VERSION 5.7 ;
  NOWIREEXTENSIONATPIN ON ;
  DIVIDERCHAR "/" ;
  BUSBITCHARS "[]" ;
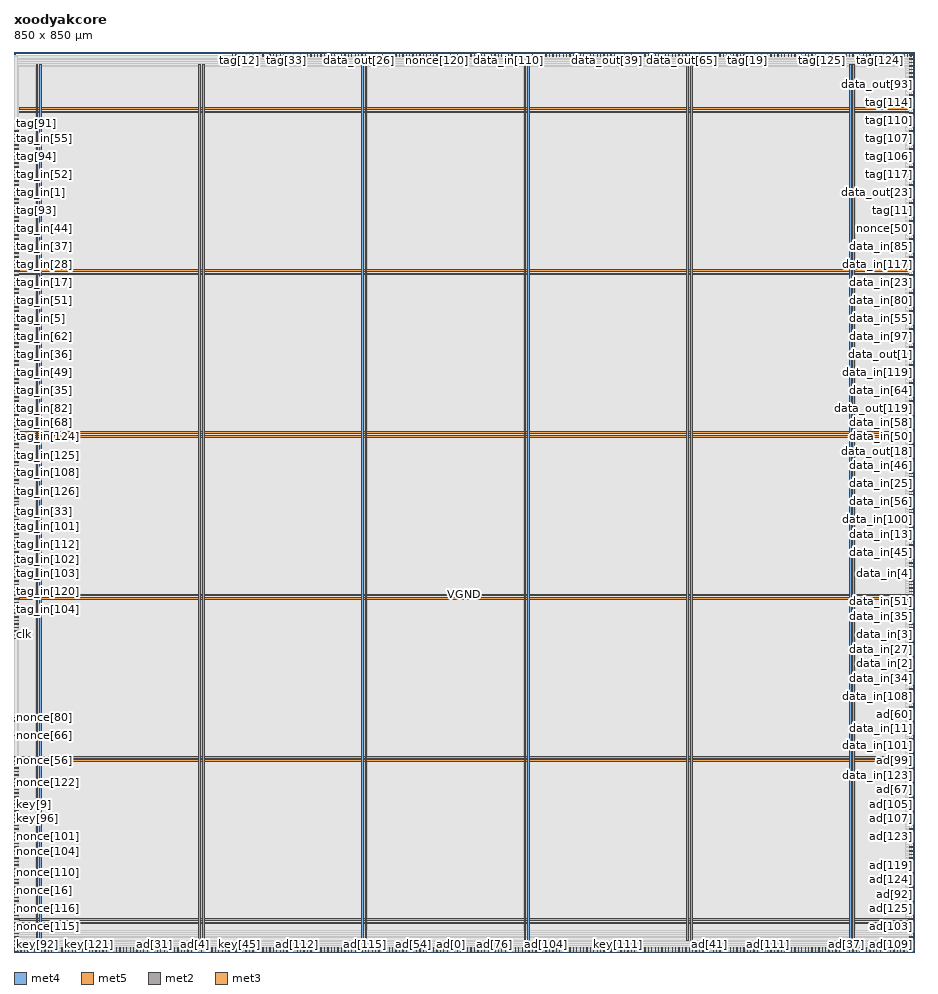
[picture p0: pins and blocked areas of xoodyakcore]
MACRO xoodyakcore
  CLASS BLOCK ;
  FOREIGN xoodyakcore ;
  ORIGIN 0.000 0.000 ;
  SIZE 850.000 BY 850.000 ;
  PIN VGND
    DIRECTION INOUT ;
    USE GROUND ;
    PORT
      LAYER met4 ;
        RECT 24.340 10.640 25.940 838.000 ;
    END
    PORT
      LAYER met4 ;
        RECT 177.940 10.640 179.540 838.000 ;
    END
    PORT
      LAYER met4 ;
        RECT 331.540 10.640 333.140 838.000 ;
    END
    PORT
      LAYER met4 ;
        RECT 485.140 10.640 486.740 838.000 ;
    END
    PORT
      LAYER met4 ;
        RECT 638.740 10.640 640.340 838.000 ;
    END
    PORT
      LAYER met4 ;
        RECT 792.340 10.640 793.940 838.000 ;
    END
    PORT
      LAYER met5 ;
        RECT 5.280 30.030 844.340 31.630 ;
    END
    PORT
      LAYER met5 ;
        RECT 5.280 183.210 844.340 184.810 ;
    END
    PORT
      LAYER met5 ;
        RECT 5.280 336.390 844.340 337.990 ;
    END
    PORT
      LAYER met5 ;
        RECT 5.280 489.570 844.340 491.170 ;
    END
    PORT
      LAYER met5 ;
        RECT 5.280 642.750 844.340 644.350 ;
    END
    PORT
      LAYER met5 ;
        RECT 5.280 795.930 844.340 797.530 ;
    END
  END VGND
  PIN VPWR
    DIRECTION INOUT ;
    USE POWER ;
    PORT
      LAYER met4 ;
        RECT 21.040 10.640 22.640 838.000 ;
    END
    PORT
      LAYER met4 ;
        RECT 174.640 10.640 176.240 838.000 ;
    END
    PORT
      LAYER met4 ;
        RECT 328.240 10.640 329.840 838.000 ;
    END
    PORT
      LAYER met4 ;
        RECT 481.840 10.640 483.440 838.000 ;
    END
    PORT
      LAYER met4 ;
        RECT 635.440 10.640 637.040 838.000 ;
    END
    PORT
      LAYER met4 ;
        RECT 789.040 10.640 790.640 838.000 ;
    END
    PORT
      LAYER met5 ;
        RECT 5.280 26.730 844.340 28.330 ;
    END
    PORT
      LAYER met5 ;
        RECT 5.280 179.910 844.340 181.510 ;
    END
    PORT
      LAYER met5 ;
        RECT 5.280 333.090 844.340 334.690 ;
    END
    PORT
      LAYER met5 ;
        RECT 5.280 486.270 844.340 487.870 ;
    END
    PORT
      LAYER met5 ;
        RECT 5.280 639.450 844.340 641.050 ;
    END
    PORT
      LAYER met5 ;
        RECT 5.280 792.630 844.340 794.230 ;
    END
  END VPWR
  PIN ad[0]
    DIRECTION INPUT ;
    USE SIGNAL ;
    ANTENNAGATEAREA 0.196500 ;
    PORT
      LAYER met2 ;
        RECT 412.250 0.000 412.530 4.000 ;
    END
  END ad[0]
  PIN ad[100]
    DIRECTION INPUT ;
    USE SIGNAL ;
    ANTENNAGATEAREA 0.196500 ;
    PORT
      LAYER met2 ;
        RECT 135.330 0.000 135.610 4.000 ;
    END
  END ad[100]
  PIN ad[101]
    DIRECTION INPUT ;
    USE SIGNAL ;
    ANTENNAGATEAREA 0.159000 ;
    PORT
      LAYER met2 ;
        RECT 808.310 0.000 808.590 4.000 ;
    END
  END ad[101]
  PIN ad[102]
    DIRECTION INPUT ;
    USE SIGNAL ;
    ANTENNAGATEAREA 0.213000 ;
    PORT
      LAYER met3 ;
        RECT 846.000 78.240 850.000 78.840 ;
    END
  END ad[102]
  PIN ad[103]
    DIRECTION INPUT ;
    USE SIGNAL ;
    ANTENNAGATEAREA 0.247500 ;
    PORT
      LAYER met3 ;
        RECT 846.000 30.640 850.000 31.240 ;
    END
  END ad[103]
  PIN ad[104]
    DIRECTION INPUT ;
    USE SIGNAL ;
    ANTENNAGATEAREA 0.196500 ;
    PORT
      LAYER met2 ;
        RECT 502.410 0.000 502.690 4.000 ;
    END
  END ad[104]
  PIN ad[105]
    DIRECTION INPUT ;
    USE SIGNAL ;
    ANTENNAGATEAREA 0.213000 ;
    PORT
      LAYER met3 ;
        RECT 846.000 139.440 850.000 140.040 ;
    END
  END ad[105]
  PIN ad[106]
    DIRECTION INPUT ;
    USE SIGNAL ;
    ANTENNAGATEAREA 0.196500 ;
    PORT
      LAYER met2 ;
        RECT 225.490 0.000 225.770 4.000 ;
    END
  END ad[106]
  PIN ad[107]
    DIRECTION INPUT ;
    USE SIGNAL ;
    ANTENNAGATEAREA 0.213000 ;
    PORT
      LAYER met3 ;
        RECT 846.000 125.840 850.000 126.440 ;
    END
  END ad[107]
  PIN ad[108]
    DIRECTION INPUT ;
    USE SIGNAL ;
    ANTENNAGATEAREA 0.196500 ;
    PORT
      LAYER met2 ;
        RECT 447.670 0.000 447.950 4.000 ;
    END
  END ad[108]
  PIN ad[109]
    DIRECTION INPUT ;
    USE SIGNAL ;
    ANTENNAGATEAREA 0.159000 ;
    PORT
      LAYER met2 ;
        RECT 830.850 0.000 831.130 4.000 ;
    END
  END ad[109]
  PIN ad[10]
    DIRECTION INPUT ;
    USE SIGNAL ;
    ANTENNAGATEAREA 0.196500 ;
    PORT
      LAYER met2 ;
        RECT 251.250 0.000 251.530 4.000 ;
    END
  END ad[10]
  PIN ad[110]
    DIRECTION INPUT ;
    USE SIGNAL ;
    ANTENNAGATEAREA 0.196500 ;
    PORT
      LAYER met2 ;
        RECT 363.950 0.000 364.230 4.000 ;
    END
  END ad[110]
  PIN ad[111]
    DIRECTION INPUT ;
    USE SIGNAL ;
    ANTENNAGATEAREA 0.196500 ;
    PORT
      LAYER met2 ;
        RECT 711.710 0.000 711.990 4.000 ;
    END
  END ad[111]
  PIN ad[112]
    DIRECTION INPUT ;
    USE SIGNAL ;
    ANTENNAGATEAREA 0.196500 ;
    PORT
      LAYER met2 ;
        RECT 267.350 0.000 267.630 4.000 ;
    END
  END ad[112]
  PIN ad[113]
    DIRECTION INPUT ;
    USE SIGNAL ;
    ANTENNAGATEAREA 0.159000 ;
    PORT
      LAYER met3 ;
        RECT 846.000 200.640 850.000 201.240 ;
    END
  END ad[113]
  PIN ad[114]
    DIRECTION INPUT ;
    USE SIGNAL ;
    ANTENNAGATEAREA 0.196500 ;
    PORT
      LAYER met2 ;
        RECT 788.990 0.000 789.270 4.000 ;
    END
  END ad[114]
  PIN ad[115]
    DIRECTION INPUT ;
    USE SIGNAL ;
    ANTENNAGATEAREA 0.196500 ;
    PORT
      LAYER met2 ;
        RECT 331.750 0.000 332.030 4.000 ;
    END
  END ad[115]
  PIN ad[116]
    DIRECTION INPUT ;
    USE SIGNAL ;
    ANTENNAGATEAREA 0.196500 ;
    PORT
      LAYER met2 ;
        RECT 386.490 0.000 386.770 4.000 ;
    END
  END ad[116]
  PIN ad[117]
    DIRECTION INPUT ;
    USE SIGNAL ;
    ANTENNAGATEAREA 0.196500 ;
    PORT
      LAYER met2 ;
        RECT 109.570 0.000 109.850 4.000 ;
    END
  END ad[117]
  PIN ad[118]
    DIRECTION INPUT ;
    USE SIGNAL ;
    ANTENNAGATEAREA 0.196500 ;
    PORT
      LAYER met2 ;
        RECT 512.070 0.000 512.350 4.000 ;
    END
  END ad[118]
  PIN ad[119]
    DIRECTION INPUT ;
    USE SIGNAL ;
    ANTENNAGATEAREA 0.159000 ;
    PORT
      LAYER met3 ;
        RECT 846.000 81.640 850.000 82.240 ;
    END
  END ad[119]
  PIN ad[11]
    DIRECTION INPUT ;
    USE SIGNAL ;
    ANTENNAGATEAREA 0.196500 ;
    PORT
      LAYER met2 ;
        RECT 798.650 0.000 798.930 4.000 ;
    END
  END ad[11]
  PIN ad[120]
    DIRECTION INPUT ;
    USE SIGNAL ;
    ANTENNAGATEAREA 0.213000 ;
    PORT
      LAYER met3 ;
        RECT 846.000 13.640 850.000 14.240 ;
    END
  END ad[120]
  PIN ad[121]
    DIRECTION INPUT ;
    USE SIGNAL ;
    ANTENNAGATEAREA 0.196500 ;
    PORT
      LAYER met2 ;
        RECT 286.670 0.000 286.950 4.000 ;
    END
  END ad[121]
  PIN ad[122]
    DIRECTION INPUT ;
    USE SIGNAL ;
    ANTENNAGATEAREA 0.196500 ;
    PORT
      LAYER met2 ;
        RECT 743.910 0.000 744.190 4.000 ;
    END
  END ad[122]
  PIN ad[123]
    DIRECTION INPUT ;
    USE SIGNAL ;
    ANTENNAGATEAREA 0.213000 ;
    PORT
      LAYER met3 ;
        RECT 846.000 115.640 850.000 116.240 ;
    END
  END ad[123]
  PIN ad[124]
    DIRECTION INPUT ;
    USE SIGNAL ;
    ANTENNAGATEAREA 0.213000 ;
    PORT
      LAYER met3 ;
        RECT 846.000 68.040 850.000 68.640 ;
    END
  END ad[124]
  PIN ad[125]
    DIRECTION INPUT ;
    USE SIGNAL ;
    ANTENNAGATEAREA 0.213000 ;
    PORT
      LAYER met3 ;
        RECT 846.000 40.840 850.000 41.440 ;
    END
  END ad[125]
  PIN ad[126]
    DIRECTION INPUT ;
    USE SIGNAL ;
    ANTENNAGATEAREA 0.196500 ;
    PORT
      LAYER met2 ;
        RECT 29.070 0.000 29.350 4.000 ;
    END
  END ad[126]
  PIN ad[127]
    DIRECTION INPUT ;
    USE SIGNAL ;
    ANTENNAGATEAREA 0.196500 ;
    PORT
      LAYER met2 ;
        RECT 219.050 0.000 219.330 4.000 ;
    END
  END ad[127]
  PIN ad[12]
    DIRECTION INPUT ;
    USE SIGNAL ;
    ANTENNAGATEAREA 0.196500 ;
    PORT
      LAYER met2 ;
        RECT 444.450 0.000 444.730 4.000 ;
    END
  END ad[12]
  PIN ad[13]
    DIRECTION INPUT ;
    USE SIGNAL ;
    ANTENNAGATEAREA 0.196500 ;
    PORT
      LAYER met2 ;
        RECT 718.150 0.000 718.430 4.000 ;
    END
  END ad[13]
  PIN ad[14]
    DIRECTION INPUT ;
    USE SIGNAL ;
    ANTENNAGATEAREA 0.196500 ;
    PORT
      LAYER met2 ;
        RECT 199.730 0.000 200.010 4.000 ;
    END
  END ad[14]
  PIN ad[15]
    DIRECTION INPUT ;
    USE SIGNAL ;
    ANTENNAGATEAREA 0.196500 ;
    PORT
      LAYER met2 ;
        RECT 814.750 0.000 815.030 4.000 ;
    END
  END ad[15]
  PIN ad[16]
    DIRECTION INPUT ;
    USE SIGNAL ;
    ANTENNAGATEAREA 0.196500 ;
    PORT
      LAYER met2 ;
        RECT 344.630 0.000 344.910 4.000 ;
    END
  END ad[16]
  PIN ad[17]
    DIRECTION INPUT ;
    USE SIGNAL ;
    ANTENNAGATEAREA 0.196500 ;
    PORT
      LAYER met2 ;
        RECT 682.730 0.000 683.010 4.000 ;
    END
  END ad[17]
  PIN ad[18]
    DIRECTION INPUT ;
    USE SIGNAL ;
    ANTENNAGATEAREA 0.196500 ;
    PORT
      LAYER met2 ;
        RECT 782.550 0.000 782.830 4.000 ;
    END
  END ad[18]
  PIN ad[19]
    DIRECTION INPUT ;
    USE SIGNAL ;
    ANTENNAGATEAREA 0.196500 ;
    PORT
      LAYER met2 ;
        RECT 347.850 0.000 348.130 4.000 ;
    END
  END ad[19]
  PIN ad[1]
    DIRECTION INPUT ;
    USE SIGNAL ;
    ANTENNAGATEAREA 0.196500 ;
    PORT
      LAYER met2 ;
        RECT 495.970 0.000 496.250 4.000 ;
    END
  END ad[1]
  PIN ad[20]
    DIRECTION INPUT ;
    USE SIGNAL ;
    ANTENNAGATEAREA 0.196500 ;
    PORT
      LAYER met2 ;
        RECT 299.550 0.000 299.830 4.000 ;
    END
  END ad[20]
  PIN ad[21]
    DIRECTION INPUT ;
    USE SIGNAL ;
    ANTENNAGATEAREA 0.196500 ;
    PORT
      LAYER met2 ;
        RECT 248.030 0.000 248.310 4.000 ;
    END
  END ad[21]
  PIN ad[22]
    DIRECTION INPUT ;
    USE SIGNAL ;
    ANTENNAGATEAREA 0.196500 ;
    PORT
      LAYER met2 ;
        RECT 260.910 0.000 261.190 4.000 ;
    END
  END ad[22]
  PIN ad[23]
    DIRECTION INPUT ;
    USE SIGNAL ;
    ANTENNAGATEAREA 0.196500 ;
    PORT
      LAYER met2 ;
        RECT 521.730 0.000 522.010 4.000 ;
    END
  END ad[23]
  PIN ad[24]
    DIRECTION INPUT ;
    USE SIGNAL ;
    ANTENNAGATEAREA 0.196500 ;
    PORT
      LAYER met2 ;
        RECT 418.690 0.000 418.970 4.000 ;
    END
  END ad[24]
  PIN ad[25]
    DIRECTION INPUT ;
    USE SIGNAL ;
    ANTENNAGATEAREA 0.196500 ;
    PORT
      LAYER met2 ;
        RECT 125.670 0.000 125.950 4.000 ;
    END
  END ad[25]
  PIN ad[26]
    DIRECTION INPUT ;
    USE SIGNAL ;
    ANTENNAGATEAREA 0.196500 ;
    PORT
      LAYER met2 ;
        RECT 756.790 0.000 757.070 4.000 ;
    END
  END ad[26]
  PIN ad[27]
    DIRECTION INPUT ;
    USE SIGNAL ;
    ANTENNAGATEAREA 0.196500 ;
    PORT
      LAYER met3 ;
        RECT 846.000 44.240 850.000 44.840 ;
    END
  END ad[27]
  PIN ad[28]
    DIRECTION INPUT ;
    USE SIGNAL ;
    ANTENNAGATEAREA 0.196500 ;
    PORT
      LAYER met3 ;
        RECT 846.000 102.040 850.000 102.640 ;
    END
  END ad[28]
  PIN ad[29]
    DIRECTION INPUT ;
    USE SIGNAL ;
    ANTENNAGATEAREA 0.196500 ;
    PORT
      LAYER met3 ;
        RECT 846.000 183.640 850.000 184.240 ;
    END
  END ad[29]
  PIN ad[2]
    DIRECTION INPUT ;
    USE SIGNAL ;
    ANTENNAGATEAREA 0.196500 ;
    PORT
      LAYER met2 ;
        RECT 383.270 0.000 383.550 4.000 ;
    END
  END ad[2]
  PIN ad[30]
    DIRECTION INPUT ;
    USE SIGNAL ;
    ANTENNAGATEAREA 0.196500 ;
    PORT
      LAYER met2 ;
        RECT 328.530 0.000 328.810 4.000 ;
    END
  END ad[30]
  PIN ad[31]
    DIRECTION INPUT ;
    USE SIGNAL ;
    ANTENNAGATEAREA 0.196500 ;
    PORT
      LAYER met2 ;
        RECT 132.110 0.000 132.390 4.000 ;
    END
  END ad[31]
  PIN ad[32]
    DIRECTION INPUT ;
    USE SIGNAL ;
    ANTENNAGATEAREA 0.196500 ;
    PORT
      LAYER met2 ;
        RECT 428.350 0.000 428.630 4.000 ;
    END
  END ad[32]
  PIN ad[33]
    DIRECTION INPUT ;
    USE SIGNAL ;
    ANTENNAGATEAREA 0.196500 ;
    PORT
      LAYER met2 ;
        RECT 254.470 0.000 254.750 4.000 ;
    END
  END ad[33]
  PIN ad[34]
    DIRECTION INPUT ;
    USE SIGNAL ;
    ANTENNAGATEAREA 0.196500 ;
    PORT
      LAYER met2 ;
        RECT 396.150 0.000 396.430 4.000 ;
    END
  END ad[34]
  PIN ad[35]
    DIRECTION INPUT ;
    USE SIGNAL ;
    ANTENNAGATEAREA 0.196500 ;
    PORT
      LAYER met3 ;
        RECT 846.000 37.440 850.000 38.040 ;
    END
  END ad[35]
  PIN ad[36]
    DIRECTION INPUT ;
    USE SIGNAL ;
    ANTENNAGATEAREA 0.196500 ;
    PORT
      LAYER met2 ;
        RECT 231.930 0.000 232.210 4.000 ;
    END
  END ad[36]
  PIN ad[37]
    DIRECTION INPUT ;
    USE SIGNAL ;
    ANTENNAGATEAREA 0.213000 ;
    PORT
      LAYER met2 ;
        RECT 785.770 0.000 786.050 4.000 ;
    END
  END ad[37]
  PIN ad[38]
    DIRECTION INPUT ;
    USE SIGNAL ;
    ANTENNAGATEAREA 0.196500 ;
    PORT
      LAYER met2 ;
        RECT 708.490 0.000 708.770 4.000 ;
    END
  END ad[38]
  PIN ad[39]
    DIRECTION INPUT ;
    USE SIGNAL ;
    ANTENNAGATEAREA 0.196500 ;
    PORT
      LAYER met2 ;
        RECT 766.450 0.000 766.730 4.000 ;
    END
  END ad[39]
  PIN ad[3]
    DIRECTION INPUT ;
    USE SIGNAL ;
    ANTENNAGATEAREA 0.196500 ;
    PORT
      LAYER met3 ;
        RECT 846.000 27.240 850.000 27.840 ;
    END
  END ad[3]
  PIN ad[40]
    DIRECTION INPUT ;
    USE SIGNAL ;
    ANTENNAGATEAREA 0.196500 ;
    PORT
      LAYER met2 ;
        RECT 505.630 0.000 505.910 4.000 ;
    END
  END ad[40]
  PIN ad[41]
    DIRECTION INPUT ;
    USE SIGNAL ;
    ANTENNAGATEAREA 0.196500 ;
    PORT
      LAYER met2 ;
        RECT 656.970 0.000 657.250 4.000 ;
    END
  END ad[41]
  PIN ad[42]
    DIRECTION INPUT ;
    USE SIGNAL ;
    ANTENNAGATEAREA 0.196500 ;
    PORT
      LAYER met2 ;
        RECT 128.890 0.000 129.170 4.000 ;
    END
  END ad[42]
  PIN ad[43]
    DIRECTION INPUT ;
    USE SIGNAL ;
    ANTENNAGATEAREA 0.196500 ;
    PORT
      LAYER met2 ;
        RECT 763.230 0.000 763.510 4.000 ;
    END
  END ad[43]
  PIN ad[44]
    DIRECTION INPUT ;
    USE SIGNAL ;
    ANTENNAGATEAREA 0.196500 ;
    PORT
      LAYER met2 ;
        RECT 450.890 0.000 451.170 4.000 ;
    END
  END ad[44]
  PIN ad[45]
    DIRECTION INPUT ;
    USE SIGNAL ;
    ANTENNAGATEAREA 0.196500 ;
    PORT
      LAYER met2 ;
        RECT 702.050 0.000 702.330 4.000 ;
    END
  END ad[45]
  PIN ad[46]
    DIRECTION INPUT ;
    USE SIGNAL ;
    ANTENNAGATEAREA 0.196500 ;
    PORT
      LAYER met2 ;
        RECT 241.590 0.000 241.870 4.000 ;
    END
  END ad[46]
  PIN ad[47]
    DIRECTION INPUT ;
    USE SIGNAL ;
    ANTENNAGATEAREA 0.196500 ;
    PORT
      LAYER met2 ;
        RECT 676.290 0.000 676.570 4.000 ;
    END
  END ad[47]
  PIN ad[48]
    DIRECTION INPUT ;
    USE SIGNAL ;
    ANTENNAGATEAREA 0.196500 ;
    PORT
      LAYER met2 ;
        RECT 244.810 0.000 245.090 4.000 ;
    END
  END ad[48]
  PIN ad[49]
    DIRECTION INPUT ;
    USE SIGNAL ;
    ANTENNAGATEAREA 0.196500 ;
    PORT
      LAYER met2 ;
        RECT 666.630 0.000 666.910 4.000 ;
    END
  END ad[49]
  PIN ad[4]
    DIRECTION INPUT ;
    USE SIGNAL ;
    ANTENNAGATEAREA 0.196500 ;
    PORT
      LAYER met2 ;
        RECT 170.750 0.000 171.030 4.000 ;
    END
  END ad[4]
  PIN ad[50]
    DIRECTION INPUT ;
    USE SIGNAL ;
    ANTENNAGATEAREA 0.196500 ;
    PORT
      LAYER met2 ;
        RECT 821.190 0.000 821.470 4.000 ;
    END
  END ad[50]
  PIN ad[51]
    DIRECTION INPUT ;
    USE SIGNAL ;
    ANTENNAGATEAREA 0.196500 ;
    PORT
      LAYER met2 ;
        RECT 157.870 0.000 158.150 4.000 ;
    END
  END ad[51]
  PIN ad[52]
    DIRECTION INPUT ;
    USE SIGNAL ;
    ANTENNAGATEAREA 0.196500 ;
    PORT
      LAYER met2 ;
        RECT 476.650 0.000 476.930 4.000 ;
    END
  END ad[52]
  PIN ad[53]
    DIRECTION INPUT ;
    USE SIGNAL ;
    ANTENNAGATEAREA 0.196500 ;
    PORT
      LAYER met2 ;
        RECT 180.410 0.000 180.690 4.000 ;
    END
  END ad[53]
  PIN ad[54]
    DIRECTION INPUT ;
    USE SIGNAL ;
    ANTENNAGATEAREA 0.196500 ;
    PORT
      LAYER met2 ;
        RECT 376.830 0.000 377.110 4.000 ;
    END
  END ad[54]
  PIN ad[55]
    DIRECTION INPUT ;
    USE SIGNAL ;
    ANTENNAGATEAREA 0.196500 ;
    PORT
      LAYER met2 ;
        RECT 750.350 0.000 750.630 4.000 ;
    END
  END ad[55]
  PIN ad[56]
    DIRECTION INPUT ;
    USE SIGNAL ;
    ANTENNAGATEAREA 0.196500 ;
    PORT
      LAYER met2 ;
        RECT 421.910 0.000 422.190 4.000 ;
    END
  END ad[56]
  PIN ad[57]
    DIRECTION INPUT ;
    USE SIGNAL ;
    ANTENNAGATEAREA 0.196500 ;
    PORT
      LAYER met2 ;
        RECT 334.970 0.000 335.250 4.000 ;
    END
  END ad[57]
  PIN ad[58]
    DIRECTION INPUT ;
    USE SIGNAL ;
    ANTENNAGATEAREA 0.196500 ;
    PORT
      LAYER met2 ;
        RECT 811.530 0.000 811.810 4.000 ;
    END
  END ad[58]
  PIN ad[59]
    DIRECTION INPUT ;
    USE SIGNAL ;
    ANTENNAGATEAREA 0.196500 ;
    PORT
      LAYER met3 ;
        RECT 846.000 122.440 850.000 123.040 ;
    END
  END ad[59]
  PIN ad[5]
    DIRECTION INPUT ;
    USE SIGNAL ;
    ANTENNAGATEAREA 0.196500 ;
    PORT
      LAYER met2 ;
        RECT 731.030 0.000 731.310 4.000 ;
    END
  END ad[5]
  PIN ad[60]
    DIRECTION INPUT ;
    USE SIGNAL ;
    ANTENNAGATEAREA 0.196500 ;
    PORT
      LAYER met3 ;
        RECT 846.000 224.440 850.000 225.040 ;
    END
  END ad[60]
  PIN ad[61]
    DIRECTION INPUT ;
    USE SIGNAL ;
    ANTENNAGATEAREA 0.196500 ;
    PORT
      LAYER met3 ;
        RECT 846.000 227.840 850.000 228.440 ;
    END
  END ad[61]
  PIN ad[62]
    DIRECTION INPUT ;
    USE SIGNAL ;
    ANTENNAGATEAREA 0.196500 ;
    PORT
      LAYER met2 ;
        RECT 402.590 0.000 402.870 4.000 ;
    END
  END ad[62]
  PIN ad[63]
    DIRECTION INPUT ;
    USE SIGNAL ;
    ANTENNAGATEAREA 0.196500 ;
    PORT
      LAYER met2 ;
        RECT 119.230 0.000 119.510 4.000 ;
    END
  END ad[63]
  PIN ad[64]
    DIRECTION INPUT ;
    USE SIGNAL ;
    ANTENNAGATEAREA 0.196500 ;
    PORT
      LAYER met2 ;
        RECT 425.130 0.000 425.410 4.000 ;
    END
  END ad[64]
  PIN ad[65]
    DIRECTION INPUT ;
    USE SIGNAL ;
    ANTENNAGATEAREA 0.126000 ;
    PORT
      LAYER met2 ;
        RECT 202.950 0.000 203.230 4.000 ;
    END
  END ad[65]
  PIN ad[66]
    DIRECTION INPUT ;
    USE SIGNAL ;
    ANTENNAGATEAREA 0.196500 ;
    PORT
      LAYER met2 ;
        RECT 222.270 0.000 222.550 4.000 ;
    END
  END ad[66]
  PIN ad[67]
    DIRECTION INPUT ;
    USE SIGNAL ;
    ANTENNAGATEAREA 0.196500 ;
    PORT
      LAYER met3 ;
        RECT 846.000 153.040 850.000 153.640 ;
    END
  END ad[67]
  PIN ad[68]
    DIRECTION INPUT ;
    USE SIGNAL ;
    ANTENNAGATEAREA 0.196500 ;
    PORT
      LAYER met2 ;
        RECT 309.210 0.000 309.490 4.000 ;
    END
  END ad[68]
  PIN ad[69]
    DIRECTION INPUT ;
    USE SIGNAL ;
    ANTENNAGATEAREA 0.196500 ;
    PORT
      LAYER met2 ;
        RECT 528.170 0.000 528.450 4.000 ;
    END
  END ad[69]
  PIN ad[6]
    DIRECTION INPUT ;
    USE SIGNAL ;
    ANTENNAGATEAREA 0.196500 ;
    PORT
      LAYER met2 ;
        RECT 772.890 0.000 773.170 4.000 ;
    END
  END ad[6]
  PIN ad[70]
    DIRECTION INPUT ;
    USE SIGNAL ;
    ANTENNAGATEAREA 0.196500 ;
    PORT
      LAYER met2 ;
        RECT 753.570 0.000 753.850 4.000 ;
    END
  END ad[70]
  PIN ad[71]
    DIRECTION INPUT ;
    USE SIGNAL ;
    ANTENNAGATEAREA 0.196500 ;
    PORT
      LAYER met2 ;
        RECT 846.950 0.000 847.230 4.000 ;
    END
  END ad[71]
  PIN ad[72]
    DIRECTION INPUT ;
    USE SIGNAL ;
    ANTENNAGATEAREA 0.196500 ;
    PORT
      LAYER met2 ;
        RECT 515.290 0.000 515.570 4.000 ;
    END
  END ad[72]
  PIN ad[73]
    DIRECTION INPUT ;
    USE SIGNAL ;
    ANTENNAGATEAREA 0.196500 ;
    PORT
      LAYER met2 ;
        RECT 760.010 0.000 760.290 4.000 ;
    END
  END ad[73]
  PIN ad[74]
    DIRECTION INPUT ;
    USE SIGNAL ;
    ANTENNAGATEAREA 0.196500 ;
    PORT
      LAYER met2 ;
        RECT 173.970 0.000 174.250 4.000 ;
    END
  END ad[74]
  PIN ad[75]
    DIRECTION INPUT ;
    USE SIGNAL ;
    ANTENNAGATEAREA 0.196500 ;
    PORT
      LAYER met2 ;
        RECT 837.290 0.000 837.570 4.000 ;
    END
  END ad[75]
  PIN ad[76]
    DIRECTION INPUT ;
    USE SIGNAL ;
    ANTENNAGATEAREA 0.196500 ;
    PORT
      LAYER met2 ;
        RECT 454.110 0.000 454.390 4.000 ;
    END
  END ad[76]
  PIN ad[77]
    DIRECTION INPUT ;
    USE SIGNAL ;
    ANTENNAGATEAREA 0.196500 ;
    PORT
      LAYER met2 ;
        RECT 695.610 0.000 695.890 4.000 ;
    END
  END ad[77]
  PIN ad[78]
    DIRECTION INPUT ;
    USE SIGNAL ;
    ANTENNAGATEAREA 0.196500 ;
    PORT
      LAYER met2 ;
        RECT 315.650 0.000 315.930 4.000 ;
    END
  END ad[78]
  PIN ad[79]
    DIRECTION INPUT ;
    USE SIGNAL ;
    ANTENNAGATEAREA 0.196500 ;
    PORT
      LAYER met2 ;
        RECT 673.070 0.000 673.350 4.000 ;
    END
  END ad[79]
  PIN ad[7]
    DIRECTION INPUT ;
    USE SIGNAL ;
    ANTENNAGATEAREA 0.196500 ;
    PORT
      LAYER met2 ;
        RECT 792.210 0.000 792.490 4.000 ;
    END
  END ad[7]
  PIN ad[80]
    DIRECTION INPUT ;
    USE SIGNAL ;
    ANTENNAGATEAREA 0.196500 ;
    PORT
      LAYER met2 ;
        RECT 238.370 0.000 238.650 4.000 ;
    END
  END ad[80]
  PIN ad[81]
    DIRECTION INPUT ;
    USE SIGNAL ;
    ANTENNAGATEAREA 0.196500 ;
    PORT
      LAYER met2 ;
        RECT 705.270 0.000 705.550 4.000 ;
    END
  END ad[81]
  PIN ad[82]
    DIRECTION INPUT ;
    USE SIGNAL ;
    ANTENNAGATEAREA 0.196500 ;
    PORT
      LAYER met2 ;
        RECT 714.930 0.000 715.210 4.000 ;
    END
  END ad[82]
  PIN ad[83]
    DIRECTION INPUT ;
    USE SIGNAL ;
    ANTENNAGATEAREA 0.196500 ;
    PORT
      LAYER met2 ;
        RECT 296.330 0.000 296.610 4.000 ;
    END
  END ad[83]
  PIN ad[84]
    DIRECTION INPUT ;
    USE SIGNAL ;
    ANTENNAGATEAREA 0.196500 ;
    PORT
      LAYER met2 ;
        RECT 486.310 0.000 486.590 4.000 ;
    END
  END ad[84]
  PIN ad[85]
    DIRECTION INPUT ;
    USE SIGNAL ;
    ANTENNAGATEAREA 0.196500 ;
    PORT
      LAYER met2 ;
        RECT 154.650 0.000 154.930 4.000 ;
    END
  END ad[85]
  PIN ad[86]
    DIRECTION INPUT ;
    USE SIGNAL ;
    ANTENNAGATEAREA 0.196500 ;
    PORT
      LAYER met2 ;
        RECT 518.510 0.000 518.790 4.000 ;
    END
  END ad[86]
  PIN ad[87]
    DIRECTION INPUT ;
    USE SIGNAL ;
    ANTENNAGATEAREA 0.159000 ;
    PORT
      LAYER met2 ;
        RECT 843.730 0.000 844.010 4.000 ;
    END
  END ad[87]
  PIN ad[88]
    DIRECTION INPUT ;
    USE SIGNAL ;
    ANTENNAGATEAREA 0.196500 ;
    PORT
      LAYER met2 ;
        RECT 431.570 0.000 431.850 4.000 ;
    END
  END ad[88]
  PIN ad[89]
    DIRECTION INPUT ;
    USE SIGNAL ;
    ANTENNAGATEAREA 0.196500 ;
    PORT
      LAYER met2 ;
        RECT 392.930 0.000 393.210 4.000 ;
    END
  END ad[89]
  PIN ad[8]
    DIRECTION INPUT ;
    USE SIGNAL ;
    ANTENNAGATEAREA 0.196500 ;
    PORT
      LAYER met2 ;
        RECT 499.190 0.000 499.470 4.000 ;
    END
  END ad[8]
  PIN ad[90]
    DIRECTION INPUT ;
    USE SIGNAL ;
    ANTENNAGATEAREA 0.196500 ;
    PORT
      LAYER met2 ;
        RECT 724.590 0.000 724.870 4.000 ;
    END
  END ad[90]
  PIN ad[91]
    DIRECTION INPUT ;
    USE SIGNAL ;
    ANTENNAGATEAREA 0.196500 ;
    PORT
      LAYER met3 ;
        RECT 846.000 34.040 850.000 34.640 ;
    END
  END ad[91]
  PIN ad[92]
    DIRECTION INPUT ;
    USE SIGNAL ;
    ANTENNAGATEAREA 0.196500 ;
    PORT
      LAYER met3 ;
        RECT 846.000 54.440 850.000 55.040 ;
    END
  END ad[92]
  PIN ad[93]
    DIRECTION INPUT ;
    USE SIGNAL ;
    ANTENNAGATEAREA 0.196500 ;
    PORT
      LAYER met3 ;
        RECT 846.000 71.440 850.000 72.040 ;
    END
  END ad[93]
  PIN ad[94]
    DIRECTION INPUT ;
    USE SIGNAL ;
    ANTENNAGATEAREA 0.196500 ;
    PORT
      LAYER met2 ;
        RECT 409.030 0.000 409.310 4.000 ;
    END
  END ad[94]
  PIN ad[95]
    DIRECTION INPUT ;
    USE SIGNAL ;
    ANTENNAGATEAREA 0.196500 ;
    PORT
      LAYER met2 ;
        RECT 196.510 0.000 196.790 4.000 ;
    END
  END ad[95]
  PIN ad[96]
    DIRECTION INPUT ;
    USE SIGNAL ;
    ANTENNAGATEAREA 0.196500 ;
    PORT
      LAYER met2 ;
        RECT 399.370 0.000 399.650 4.000 ;
    END
  END ad[96]
  PIN ad[97]
    DIRECTION INPUT ;
    USE SIGNAL ;
    ANTENNAGATEAREA 0.196500 ;
    PORT
      LAYER met2 ;
        RECT 38.730 0.000 39.010 4.000 ;
    END
  END ad[97]
  PIN ad[98]
    DIRECTION INPUT ;
    USE SIGNAL ;
    ANTENNAGATEAREA 0.213000 ;
    PORT
      LAYER met2 ;
        RECT 283.450 0.000 283.730 4.000 ;
    END
  END ad[98]
  PIN ad[99]
    DIRECTION INPUT ;
    USE SIGNAL ;
    ANTENNAGATEAREA 0.159000 ;
    PORT
      LAYER met3 ;
        RECT 846.000 180.240 850.000 180.840 ;
    END
  END ad[99]
  PIN ad[9]
    DIRECTION INPUT ;
    USE SIGNAL ;
    ANTENNAGATEAREA 0.196500 ;
    PORT
      LAYER met2 ;
        RECT 824.410 0.000 824.690 4.000 ;
    END
  END ad[9]
  PIN ad_length[0]
    DIRECTION INPUT ;
    USE SIGNAL ;
    ANTENNAGATEAREA 0.213000 ;
    PORT
      LAYER met3 ;
        RECT 846.000 3.440 850.000 4.040 ;
    END
  END ad_length[0]
  PIN ad_length[1]
    DIRECTION INPUT ;
    USE SIGNAL ;
    ANTENNAGATEAREA 0.213000 ;
    PORT
      LAYER met3 ;
        RECT 846.000 6.840 850.000 7.440 ;
    END
  END ad_length[1]
  PIN ad_length[2]
    DIRECTION INPUT ;
    USE SIGNAL ;
    ANTENNAGATEAREA 0.213000 ;
    PORT
      LAYER met3 ;
        RECT 846.000 17.040 850.000 17.640 ;
    END
  END ad_length[2]
  PIN ad_length[3]
    DIRECTION INPUT ;
    USE SIGNAL ;
    ANTENNAGATEAREA 0.213000 ;
    PORT
      LAYER met3 ;
        RECT 846.000 0.040 850.000 0.640 ;
    END
  END ad_length[3]
  PIN ad_length[4]
    DIRECTION INPUT ;
    USE SIGNAL ;
    ANTENNAGATEAREA 0.159000 ;
    PORT
      LAYER met3 ;
        RECT 846.000 394.440 850.000 395.040 ;
    END
  END ad_length[4]
  PIN clk
    DIRECTION INPUT ;
    USE SIGNAL ;
    ANTENNAGATEAREA 0.852000 ;
    PORT
      LAYER met3 ;
        RECT 0.000 299.240 4.000 299.840 ;
    END
  END clk
  PIN data_in[0]
    DIRECTION INPUT ;
    USE SIGNAL ;
    ANTENNAGATEAREA 0.196500 ;
    PORT
      LAYER met3 ;
        RECT 846.000 591.640 850.000 592.240 ;
    END
  END data_in[0]
  PIN data_in[100]
    DIRECTION INPUT ;
    USE SIGNAL ;
    ANTENNAGATEAREA 0.196500 ;
    PORT
      LAYER met3 ;
        RECT 846.000 408.040 850.000 408.640 ;
    END
  END data_in[100]
  PIN data_in[101]
    DIRECTION INPUT ;
    USE SIGNAL ;
    ANTENNAGATEAREA 0.196500 ;
    PORT
      LAYER met3 ;
        RECT 846.000 187.040 850.000 187.640 ;
    END
  END data_in[101]
  PIN data_in[102]
    DIRECTION INPUT ;
    USE SIGNAL ;
    ANTENNAGATEAREA 0.196500 ;
    PORT
      LAYER met3 ;
        RECT 846.000 261.840 850.000 262.440 ;
    END
  END data_in[102]
  PIN data_in[103]
    DIRECTION INPUT ;
    USE SIGNAL ;
    ANTENNAGATEAREA 0.196500 ;
    PORT
      LAYER met3 ;
        RECT 846.000 370.640 850.000 371.240 ;
    END
  END data_in[103]
  PIN data_in[104]
    DIRECTION INPUT ;
    USE SIGNAL ;
    ANTENNAGATEAREA 0.196500 ;
    PORT
      LAYER met3 ;
        RECT 846.000 567.840 850.000 568.440 ;
    END
  END data_in[104]
  PIN data_in[105]
    DIRECTION INPUT ;
    USE SIGNAL ;
    ANTENNAGATEAREA 0.196500 ;
    PORT
      LAYER met3 ;
        RECT 846.000 336.640 850.000 337.240 ;
    END
  END data_in[105]
  PIN data_in[106]
    DIRECTION INPUT ;
    USE SIGNAL ;
    ANTENNAGATEAREA 0.196500 ;
    PORT
      LAYER met3 ;
        RECT 846.000 136.040 850.000 136.640 ;
    END
  END data_in[106]
  PIN data_in[107]
    DIRECTION INPUT ;
    USE SIGNAL ;
    ANTENNAGATEAREA 0.196500 ;
    PORT
      LAYER met3 ;
        RECT 846.000 85.040 850.000 85.640 ;
    END
  END data_in[107]
  PIN data_in[108]
    DIRECTION INPUT ;
    USE SIGNAL ;
    ANTENNAGATEAREA 0.196500 ;
    PORT
      LAYER met3 ;
        RECT 846.000 241.440 850.000 242.040 ;
    END
  END data_in[108]
  PIN data_in[109]
    DIRECTION INPUT ;
    USE SIGNAL ;
    ANTENNAGATEAREA 0.196500 ;
    PORT
      LAYER met3 ;
        RECT 846.000 404.640 850.000 405.240 ;
    END
  END data_in[109]
  PIN data_in[10]
    DIRECTION INPUT ;
    USE SIGNAL ;
    ANTENNAGATEAREA 0.196500 ;
    PORT
      LAYER met3 ;
        RECT 846.000 176.840 850.000 177.440 ;
    END
  END data_in[10]
  PIN data_in[110]
    DIRECTION INPUT ;
    USE SIGNAL ;
    ANTENNAGATEAREA 0.196500 ;
    PORT
      LAYER met2 ;
        RECT 466.990 846.000 467.270 850.000 ;
    END
  END data_in[110]
  PIN data_in[111]
    DIRECTION INPUT ;
    USE SIGNAL ;
    ANTENNAGATEAREA 0.196500 ;
    PORT
      LAYER met3 ;
        RECT 846.000 544.040 850.000 544.640 ;
    END
  END data_in[111]
  PIN data_in[112]
    DIRECTION INPUT ;
    USE SIGNAL ;
    ANTENNAGATEAREA 0.196500 ;
    PORT
      LAYER met3 ;
        RECT 846.000 618.840 850.000 619.440 ;
    END
  END data_in[112]
  PIN data_in[113]
    DIRECTION INPUT ;
    USE SIGNAL ;
    ANTENNAGATEAREA 0.196500 ;
    PORT
      LAYER met3 ;
        RECT 846.000 231.240 850.000 231.840 ;
    END
  END data_in[113]
  PIN data_in[114]
    DIRECTION INPUT ;
    USE SIGNAL ;
    ANTENNAGATEAREA 0.126000 ;
    PORT
      LAYER met3 ;
        RECT 846.000 601.840 850.000 602.440 ;
    END
  END data_in[114]
  PIN data_in[115]
    DIRECTION INPUT ;
    USE SIGNAL ;
    ANTENNAGATEAREA 0.126000 ;
    PORT
      LAYER met3 ;
        RECT 846.000 142.840 850.000 143.440 ;
    END
  END data_in[115]
  PIN data_in[116]
    DIRECTION INPUT ;
    USE SIGNAL ;
    ANTENNAGATEAREA 0.196500 ;
    PORT
      LAYER met3 ;
        RECT 846.000 95.240 850.000 95.840 ;
    END
  END data_in[116]
  PIN data_in[117]
    DIRECTION INPUT ;
    USE SIGNAL ;
    ANTENNAGATEAREA 0.196500 ;
    PORT
      LAYER met3 ;
        RECT 846.000 649.440 850.000 650.040 ;
    END
  END data_in[117]
  PIN data_in[118]
    DIRECTION INPUT ;
    USE SIGNAL ;
    ANTENNAGATEAREA 0.196500 ;
    PORT
      LAYER met3 ;
        RECT 846.000 561.040 850.000 561.640 ;
    END
  END data_in[118]
  PIN data_in[119]
    DIRECTION INPUT ;
    USE SIGNAL ;
    ANTENNAGATEAREA 0.196500 ;
    PORT
      LAYER met3 ;
        RECT 846.000 547.440 850.000 548.040 ;
    END
  END data_in[119]
  PIN data_in[11]
    DIRECTION INPUT ;
    USE SIGNAL ;
    ANTENNAGATEAREA 0.196500 ;
    PORT
      LAYER met3 ;
        RECT 846.000 210.840 850.000 211.440 ;
    END
  END data_in[11]
  PIN data_in[120]
    DIRECTION INPUT ;
    USE SIGNAL ;
    ANTENNAGATEAREA 0.196500 ;
    PORT
      LAYER met3 ;
        RECT 846.000 411.440 850.000 412.040 ;
    END
  END data_in[120]
  PIN data_in[121]
    DIRECTION INPUT ;
    USE SIGNAL ;
    ANTENNAGATEAREA 0.196500 ;
    PORT
      LAYER met3 ;
        RECT 846.000 540.640 850.000 541.240 ;
    END
  END data_in[121]
  PIN data_in[122]
    DIRECTION INPUT ;
    USE SIGNAL ;
    ANTENNAGATEAREA 0.196500 ;
    PORT
      LAYER met3 ;
        RECT 846.000 595.040 850.000 595.640 ;
    END
  END data_in[122]
  PIN data_in[123]
    DIRECTION INPUT ;
    USE SIGNAL ;
    ANTENNAGATEAREA 0.196500 ;
    PORT
      LAYER met3 ;
        RECT 846.000 166.640 850.000 167.240 ;
    END
  END data_in[123]
  PIN data_in[124]
    DIRECTION INPUT ;
    USE SIGNAL ;
    ANTENNAGATEAREA 0.213000 ;
    PORT
      LAYER met2 ;
        RECT 450.890 846.000 451.170 850.000 ;
    END
  END data_in[124]
  PIN data_in[125]
    DIRECTION INPUT ;
    USE SIGNAL ;
    ANTENNAGATEAREA 0.196500 ;
    PORT
      LAYER met3 ;
        RECT 846.000 159.840 850.000 160.440 ;
    END
  END data_in[125]
  PIN data_in[126]
    DIRECTION INPUT ;
    USE SIGNAL ;
    ANTENNAGATEAREA 0.126000 ;
    PORT
      LAYER met3 ;
        RECT 846.000 238.040 850.000 238.640 ;
    END
  END data_in[126]
  PIN data_in[127]
    DIRECTION INPUT ;
    USE SIGNAL ;
    ANTENNAGATEAREA 0.196500 ;
    PORT
      LAYER met3 ;
        RECT 846.000 360.440 850.000 361.040 ;
    END
  END data_in[127]
  PIN data_in[12]
    DIRECTION INPUT ;
    USE SIGNAL ;
    ANTENNAGATEAREA 0.196500 ;
    PORT
      LAYER met3 ;
        RECT 846.000 204.040 850.000 204.640 ;
    END
  END data_in[12]
  PIN data_in[13]
    DIRECTION INPUT ;
    USE SIGNAL ;
    ANTENNAGATEAREA 0.196500 ;
    PORT
      LAYER met3 ;
        RECT 846.000 401.240 850.000 401.840 ;
    END
  END data_in[13]
  PIN data_in[14]
    DIRECTION INPUT ;
    USE SIGNAL ;
    ANTENNAGATEAREA 0.196500 ;
    PORT
      LAYER met3 ;
        RECT 846.000 506.640 850.000 507.240 ;
    END
  END data_in[14]
  PIN data_in[15]
    DIRECTION INPUT ;
    USE SIGNAL ;
    ANTENNAGATEAREA 0.196500 ;
    PORT
      LAYER met3 ;
        RECT 846.000 496.440 850.000 497.040 ;
    END
  END data_in[15]
  PIN data_in[16]
    DIRECTION INPUT ;
    USE SIGNAL ;
    ANTENNAGATEAREA 0.196500 ;
    PORT
      LAYER met3 ;
        RECT 846.000 510.040 850.000 510.640 ;
    END
  END data_in[16]
  PIN data_in[17]
    DIRECTION INPUT ;
    USE SIGNAL ;
    ANTENNAGATEAREA 0.196500 ;
    PORT
      LAYER met3 ;
        RECT 846.000 248.240 850.000 248.840 ;
    END
  END data_in[17]
  PIN data_in[18]
    DIRECTION INPUT ;
    USE SIGNAL ;
    ANTENNAGATEAREA 0.196500 ;
    PORT
      LAYER met3 ;
        RECT 846.000 397.840 850.000 398.440 ;
    END
  END data_in[18]
  PIN data_in[19]
    DIRECTION INPUT ;
    USE SIGNAL ;
    ANTENNAGATEAREA 0.196500 ;
    PORT
      LAYER met3 ;
        RECT 846.000 326.440 850.000 327.040 ;
    END
  END data_in[19]
  PIN data_in[1]
    DIRECTION INPUT ;
    USE SIGNAL ;
    ANTENNAGATEAREA 0.196500 ;
    PORT
      LAYER met3 ;
        RECT 846.000 659.640 850.000 660.240 ;
    END
  END data_in[1]
  PIN data_in[20]
    DIRECTION INPUT ;
    USE SIGNAL ;
    ANTENNAGATEAREA 0.196500 ;
    PORT
      LAYER met3 ;
        RECT 846.000 57.840 850.000 58.440 ;
    END
  END data_in[20]
  PIN data_in[21]
    DIRECTION INPUT ;
    USE SIGNAL ;
    ANTENNAGATEAREA 0.196500 ;
    PORT
      LAYER met3 ;
        RECT 846.000 550.840 850.000 551.440 ;
    END
  END data_in[21]
  PIN data_in[22]
    DIRECTION INPUT ;
    USE SIGNAL ;
    ANTENNAGATEAREA 0.196500 ;
    PORT
      LAYER met3 ;
        RECT 846.000 462.440 850.000 463.040 ;
    END
  END data_in[22]
  PIN data_in[23]
    DIRECTION INPUT ;
    USE SIGNAL ;
    ANTENNAGATEAREA 0.196500 ;
    PORT
      LAYER met3 ;
        RECT 846.000 632.440 850.000 633.040 ;
    END
  END data_in[23]
  PIN data_in[24]
    DIRECTION INPUT ;
    USE SIGNAL ;
    ANTENNAGATEAREA 0.196500 ;
    PORT
      LAYER met3 ;
        RECT 846.000 438.640 850.000 439.240 ;
    END
  END data_in[24]
  PIN data_in[25]
    DIRECTION INPUT ;
    USE SIGNAL ;
    ANTENNAGATEAREA 0.196500 ;
    PORT
      LAYER met3 ;
        RECT 846.000 442.040 850.000 442.640 ;
    END
  END data_in[25]
  PIN data_in[26]
    DIRECTION INPUT ;
    USE SIGNAL ;
    ANTENNAGATEAREA 0.196500 ;
    PORT
      LAYER met3 ;
        RECT 846.000 445.440 850.000 446.040 ;
    END
  END data_in[26]
  PIN data_in[27]
    DIRECTION INPUT ;
    USE SIGNAL ;
    ANTENNAGATEAREA 0.196500 ;
    PORT
      LAYER met3 ;
        RECT 846.000 285.640 850.000 286.240 ;
    END
  END data_in[27]
  PIN data_in[28]
    DIRECTION INPUT ;
    USE SIGNAL ;
    ANTENNAGATEAREA 0.196500 ;
    PORT
      LAYER met3 ;
        RECT 846.000 608.640 850.000 609.240 ;
    END
  END data_in[28]
  PIN data_in[29]
    DIRECTION INPUT ;
    USE SIGNAL ;
    ANTENNAGATEAREA 0.196500 ;
    PORT
      LAYER met3 ;
        RECT 846.000 61.240 850.000 61.840 ;
    END
  END data_in[29]
  PIN data_in[2]
    DIRECTION INPUT ;
    USE SIGNAL ;
    ANTENNAGATEAREA 0.196500 ;
    PORT
      LAYER met3 ;
        RECT 846.000 272.040 850.000 272.640 ;
    END
  END data_in[2]
  PIN data_in[30]
    DIRECTION INPUT ;
    USE SIGNAL ;
    ANTENNAGATEAREA 0.196500 ;
    PORT
      LAYER met3 ;
        RECT 846.000 173.440 850.000 174.040 ;
    END
  END data_in[30]
  PIN data_in[31]
    DIRECTION INPUT ;
    USE SIGNAL ;
    ANTENNAGATEAREA 0.159000 ;
    PORT
      LAYER met3 ;
        RECT 846.000 10.240 850.000 10.840 ;
    END
  END data_in[31]
  PIN data_in[32]
    DIRECTION INPUT ;
    USE SIGNAL ;
    ANTENNAGATEAREA 0.196500 ;
    PORT
      LAYER met3 ;
        RECT 846.000 656.240 850.000 656.840 ;
    END
  END data_in[32]
  PIN data_in[33]
    DIRECTION INPUT ;
    USE SIGNAL ;
    ANTENNAGATEAREA 0.196500 ;
    PORT
      LAYER met3 ;
        RECT 846.000 516.840 850.000 517.440 ;
    END
  END data_in[33]
  PIN data_in[34]
    DIRECTION INPUT ;
    USE SIGNAL ;
    ANTENNAGATEAREA 0.196500 ;
    PORT
      LAYER met3 ;
        RECT 846.000 265.240 850.000 265.840 ;
    END
  END data_in[34]
  PIN data_in[35]
    DIRECTION INPUT ;
    USE SIGNAL ;
    ANTENNAGATEAREA 0.196500 ;
    PORT
      LAYER met3 ;
        RECT 846.000 316.240 850.000 316.840 ;
    END
  END data_in[35]
  PIN data_in[36]
    DIRECTION INPUT ;
    USE SIGNAL ;
    ANTENNAGATEAREA 0.196500 ;
    PORT
      LAYER met3 ;
        RECT 846.000 380.840 850.000 381.440 ;
    END
  END data_in[36]
  PIN data_in[37]
    DIRECTION INPUT ;
    USE SIGNAL ;
    ANTENNAGATEAREA 0.196500 ;
    PORT
      LAYER met3 ;
        RECT 846.000 170.040 850.000 170.640 ;
    END
  END data_in[37]
  PIN data_in[38]
    DIRECTION INPUT ;
    USE SIGNAL ;
    ANTENNAGATEAREA 0.196500 ;
    PORT
      LAYER met3 ;
        RECT 846.000 91.840 850.000 92.440 ;
    END
  END data_in[38]
  PIN data_in[39]
    DIRECTION INPUT ;
    USE SIGNAL ;
    ANTENNAGATEAREA 0.196500 ;
    PORT
      LAYER met3 ;
        RECT 846.000 663.040 850.000 663.640 ;
    END
  END data_in[39]
  PIN data_in[3]
    DIRECTION INPUT ;
    USE SIGNAL ;
    ANTENNAGATEAREA 0.196500 ;
    PORT
      LAYER met3 ;
        RECT 846.000 299.240 850.000 299.840 ;
    END
  END data_in[3]
  PIN data_in[40]
    DIRECTION INPUT ;
    USE SIGNAL ;
    ANTENNAGATEAREA 0.196500 ;
    PORT
      LAYER met3 ;
        RECT 846.000 523.640 850.000 524.240 ;
    END
  END data_in[40]
  PIN data_in[41]
    DIRECTION INPUT ;
    USE SIGNAL ;
    ANTENNAGATEAREA 0.196500 ;
    PORT
      LAYER met3 ;
        RECT 846.000 353.640 850.000 354.240 ;
    END
  END data_in[41]
  PIN data_in[42]
    DIRECTION INPUT ;
    USE SIGNAL ;
    ANTENNAGATEAREA 0.196500 ;
    PORT
      LAYER met3 ;
        RECT 846.000 74.840 850.000 75.440 ;
    END
  END data_in[42]
  PIN data_in[43]
    DIRECTION INPUT ;
    USE SIGNAL ;
    ANTENNAGATEAREA 0.196500 ;
    PORT
      LAYER met3 ;
        RECT 846.000 258.440 850.000 259.040 ;
    END
  END data_in[43]
  PIN data_in[44]
    DIRECTION INPUT ;
    USE SIGNAL ;
    ANTENNAGATEAREA 0.196500 ;
    PORT
      LAYER met3 ;
        RECT 846.000 207.440 850.000 208.040 ;
    END
  END data_in[44]
  PIN data_in[45]
    DIRECTION INPUT ;
    USE SIGNAL ;
    ANTENNAGATEAREA 0.196500 ;
    PORT
      LAYER met3 ;
        RECT 846.000 384.240 850.000 384.840 ;
    END
  END data_in[45]
  PIN data_in[46]
    DIRECTION INPUT ;
    USE SIGNAL ;
    ANTENNAGATEAREA 0.196500 ;
    PORT
      LAYER met3 ;
        RECT 846.000 459.040 850.000 459.640 ;
    END
  END data_in[46]
  PIN data_in[47]
    DIRECTION INPUT ;
    USE SIGNAL ;
    ANTENNAGATEAREA 0.213000 ;
    PORT
      LAYER met2 ;
        RECT 309.210 846.000 309.490 850.000 ;
    END
  END data_in[47]
  PIN data_in[48]
    DIRECTION INPUT ;
    USE SIGNAL ;
    ANTENNAGATEAREA 0.196500 ;
    PORT
      LAYER met3 ;
        RECT 846.000 557.640 850.000 558.240 ;
    END
  END data_in[48]
  PIN data_in[49]
    DIRECTION INPUT ;
    USE SIGNAL ;
    ANTENNAGATEAREA 0.196500 ;
    PORT
      LAYER met3 ;
        RECT 846.000 255.040 850.000 255.640 ;
    END
  END data_in[49]
  PIN data_in[4]
    DIRECTION INPUT ;
    USE SIGNAL ;
    ANTENNAGATEAREA 0.196500 ;
    PORT
      LAYER met3 ;
        RECT 846.000 357.040 850.000 357.640 ;
    END
  END data_in[4]
  PIN data_in[50]
    DIRECTION INPUT ;
    USE SIGNAL ;
    ANTENNAGATEAREA 0.196500 ;
    PORT
      LAYER met3 ;
        RECT 846.000 486.240 850.000 486.840 ;
    END
  END data_in[50]
  PIN data_in[51]
    DIRECTION INPUT ;
    USE SIGNAL ;
    ANTENNAGATEAREA 0.196500 ;
    PORT
      LAYER met3 ;
        RECT 846.000 323.040 850.000 323.640 ;
    END
  END data_in[51]
  PIN data_in[52]
    DIRECTION INPUT ;
    USE SIGNAL ;
    ANTENNAGATEAREA 0.196500 ;
    PORT
      LAYER met3 ;
        RECT 846.000 64.640 850.000 65.240 ;
    END
  END data_in[52]
  PIN data_in[53]
    DIRECTION INPUT ;
    USE SIGNAL ;
    ANTENNAGATEAREA 0.196500 ;
    PORT
      LAYER met3 ;
        RECT 846.000 493.040 850.000 493.640 ;
    END
  END data_in[53]
  PIN data_in[54]
    DIRECTION INPUT ;
    USE SIGNAL ;
    ANTENNAGATEAREA 0.126000 ;
    PORT
      LAYER met3 ;
        RECT 846.000 669.840 850.000 670.440 ;
    END
  END data_in[54]
  PIN data_in[55]
    DIRECTION INPUT ;
    USE SIGNAL ;
    ANTENNAGATEAREA 0.196500 ;
    PORT
      LAYER met3 ;
        RECT 846.000 598.440 850.000 599.040 ;
    END
  END data_in[55]
  PIN data_in[56]
    DIRECTION INPUT ;
    USE SIGNAL ;
    ANTENNAGATEAREA 0.196500 ;
    PORT
      LAYER met3 ;
        RECT 846.000 418.240 850.000 418.840 ;
    END
  END data_in[56]
  PIN data_in[57]
    DIRECTION INPUT ;
    USE SIGNAL ;
    ANTENNAGATEAREA 0.196500 ;
    PORT
      LAYER met3 ;
        RECT 846.000 588.240 850.000 588.840 ;
    END
  END data_in[57]
  PIN data_in[58]
    DIRECTION INPUT ;
    USE SIGNAL ;
    ANTENNAGATEAREA 0.196500 ;
    PORT
      LAYER met3 ;
        RECT 846.000 499.840 850.000 500.440 ;
    END
  END data_in[58]
  PIN data_in[59]
    DIRECTION INPUT ;
    USE SIGNAL ;
    ANTENNAGATEAREA 0.196500 ;
    PORT
      LAYER met3 ;
        RECT 846.000 282.240 850.000 282.840 ;
    END
  END data_in[59]
  PIN data_in[5]
    DIRECTION INPUT ;
    USE SIGNAL ;
    ANTENNAGATEAREA 0.196500 ;
    PORT
      LAYER met3 ;
        RECT 846.000 234.640 850.000 235.240 ;
    END
  END data_in[5]
  PIN data_in[60]
    DIRECTION INPUT ;
    USE SIGNAL ;
    ANTENNAGATEAREA 0.196500 ;
    PORT
      LAYER met3 ;
        RECT 846.000 625.640 850.000 626.240 ;
    END
  END data_in[60]
  PIN data_in[61]
    DIRECTION INPUT ;
    USE SIGNAL ;
    ANTENNAGATEAREA 0.196500 ;
    PORT
      LAYER met3 ;
        RECT 846.000 132.640 850.000 133.240 ;
    END
  END data_in[61]
  PIN data_in[62]
    DIRECTION INPUT ;
    USE SIGNAL ;
    ANTENNAGATEAREA 0.196500 ;
    PORT
      LAYER met3 ;
        RECT 846.000 105.440 850.000 106.040 ;
    END
  END data_in[62]
  PIN data_in[63]
    DIRECTION INPUT ;
    USE SIGNAL ;
    ANTENNAGATEAREA 0.196500 ;
    PORT
      LAYER met3 ;
        RECT 846.000 431.840 850.000 432.440 ;
    END
  END data_in[63]
  PIN data_in[64]
    DIRECTION INPUT ;
    USE SIGNAL ;
    ANTENNAGATEAREA 0.196500 ;
    PORT
      LAYER met3 ;
        RECT 846.000 530.440 850.000 531.040 ;
    END
  END data_in[64]
  PIN data_in[65]
    DIRECTION INPUT ;
    USE SIGNAL ;
    ANTENNAGATEAREA 0.196500 ;
    PORT
      LAYER met3 ;
        RECT 846.000 584.840 850.000 585.440 ;
    END
  END data_in[65]
  PIN data_in[66]
    DIRECTION INPUT ;
    USE SIGNAL ;
    ANTENNAGATEAREA 0.196500 ;
    PORT
      LAYER met3 ;
        RECT 846.000 278.840 850.000 279.440 ;
    END
  END data_in[66]
  PIN data_in[67]
    DIRECTION INPUT ;
    USE SIGNAL ;
    ANTENNAGATEAREA 0.196500 ;
    PORT
      LAYER met3 ;
        RECT 846.000 306.040 850.000 306.640 ;
    END
  END data_in[67]
  PIN data_in[68]
    DIRECTION INPUT ;
    USE SIGNAL ;
    ANTENNAGATEAREA 0.196500 ;
    PORT
      LAYER met3 ;
        RECT 846.000 367.240 850.000 367.840 ;
    END
  END data_in[68]
  PIN data_in[69]
    DIRECTION INPUT ;
    USE SIGNAL ;
    ANTENNAGATEAREA 0.196500 ;
    PORT
      LAYER met3 ;
        RECT 846.000 129.240 850.000 129.840 ;
    END
  END data_in[69]
  PIN data_in[6]
    DIRECTION INPUT ;
    USE SIGNAL ;
    ANTENNAGATEAREA 0.196500 ;
    PORT
      LAYER met3 ;
        RECT 846.000 112.240 850.000 112.840 ;
    END
  END data_in[6]
  PIN data_in[70]
    DIRECTION INPUT ;
    USE SIGNAL ;
    ANTENNAGATEAREA 0.126000 ;
    PORT
      LAYER met3 ;
        RECT 846.000 251.640 850.000 252.240 ;
    END
  END data_in[70]
  PIN data_in[71]
    DIRECTION INPUT ;
    USE SIGNAL ;
    ANTENNAGATEAREA 0.213000 ;
    PORT
      LAYER met3 ;
        RECT 846.000 374.040 850.000 374.640 ;
    END
  END data_in[71]
  PIN data_in[72]
    DIRECTION INPUT ;
    USE SIGNAL ;
    ANTENNAGATEAREA 0.126000 ;
    PORT
      LAYER met3 ;
        RECT 846.000 479.440 850.000 480.040 ;
    END
  END data_in[72]
  PIN data_in[73]
    DIRECTION INPUT ;
    USE SIGNAL ;
    ANTENNAGATEAREA 0.196500 ;
    PORT
      LAYER met3 ;
        RECT 846.000 343.440 850.000 344.040 ;
    END
  END data_in[73]
  PIN data_in[74]
    DIRECTION INPUT ;
    USE SIGNAL ;
    ANTENNAGATEAREA 0.196500 ;
    PORT
      LAYER met3 ;
        RECT 846.000 98.640 850.000 99.240 ;
    END
  END data_in[74]
  PIN data_in[75]
    DIRECTION INPUT ;
    USE SIGNAL ;
    ANTENNAGATEAREA 0.196500 ;
    PORT
      LAYER met3 ;
        RECT 846.000 214.240 850.000 214.840 ;
    END
  END data_in[75]
  PIN data_in[76]
    DIRECTION INPUT ;
    USE SIGNAL ;
    ANTENNAGATEAREA 0.196500 ;
    PORT
      LAYER met3 ;
        RECT 846.000 221.040 850.000 221.640 ;
    END
  END data_in[76]
  PIN data_in[77]
    DIRECTION INPUT ;
    USE SIGNAL ;
    ANTENNAGATEAREA 0.196500 ;
    PORT
      LAYER met3 ;
        RECT 846.000 465.840 850.000 466.440 ;
    END
  END data_in[77]
  PIN data_in[78]
    DIRECTION INPUT ;
    USE SIGNAL ;
    ANTENNAGATEAREA 0.196500 ;
    PORT
      LAYER met3 ;
        RECT 846.000 448.840 850.000 449.440 ;
    END
  END data_in[78]
  PIN data_in[79]
    DIRECTION INPUT ;
    USE SIGNAL ;
    ANTENNAGATEAREA 0.196500 ;
    PORT
      LAYER met3 ;
        RECT 846.000 574.640 850.000 575.240 ;
    END
  END data_in[79]
  PIN data_in[7]
    DIRECTION INPUT ;
    USE SIGNAL ;
    ANTENNAGATEAREA 0.196500 ;
    PORT
      LAYER met3 ;
        RECT 846.000 676.640 850.000 677.240 ;
    END
  END data_in[7]
  PIN data_in[80]
    DIRECTION INPUT ;
    USE SIGNAL ;
    ANTENNAGATEAREA 0.196500 ;
    PORT
      LAYER met3 ;
        RECT 846.000 615.440 850.000 616.040 ;
    END
  END data_in[80]
  PIN data_in[81]
    DIRECTION INPUT ;
    USE SIGNAL ;
    ANTENNAGATEAREA 0.196500 ;
    PORT
      LAYER met3 ;
        RECT 846.000 149.640 850.000 150.240 ;
    END
  END data_in[81]
  PIN data_in[82]
    DIRECTION INPUT ;
    USE SIGNAL ;
    ANTENNAGATEAREA 0.196500 ;
    PORT
      LAYER met3 ;
        RECT 846.000 391.040 850.000 391.640 ;
    END
  END data_in[82]
  PIN data_in[83]
    DIRECTION INPUT ;
    USE SIGNAL ;
    ANTENNAGATEAREA 0.196500 ;
    PORT
      LAYER met3 ;
        RECT 846.000 329.840 850.000 330.440 ;
    END
  END data_in[83]
  PIN data_in[84]
    DIRECTION INPUT ;
    USE SIGNAL ;
    ANTENNAGATEAREA 0.196500 ;
    PORT
      LAYER met3 ;
        RECT 846.000 108.840 850.000 109.440 ;
    END
  END data_in[84]
  PIN data_in[85]
    DIRECTION INPUT ;
    USE SIGNAL ;
    ANTENNAGATEAREA 0.196500 ;
    PORT
      LAYER met3 ;
        RECT 846.000 666.440 850.000 667.040 ;
    END
  END data_in[85]
  PIN data_in[86]
    DIRECTION INPUT ;
    USE SIGNAL ;
    ANTENNAGATEAREA 0.196500 ;
    PORT
      LAYER met3 ;
        RECT 846.000 425.040 850.000 425.640 ;
    END
  END data_in[86]
  PIN data_in[87]
    DIRECTION INPUT ;
    USE SIGNAL ;
    ANTENNAGATEAREA 0.196500 ;
    PORT
      LAYER met3 ;
        RECT 846.000 554.240 850.000 554.840 ;
    END
  END data_in[87]
  PIN data_in[88]
    DIRECTION INPUT ;
    USE SIGNAL ;
    ANTENNAGATEAREA 0.196500 ;
    PORT
      LAYER met3 ;
        RECT 846.000 414.840 850.000 415.440 ;
    END
  END data_in[88]
  PIN data_in[89]
    DIRECTION INPUT ;
    USE SIGNAL ;
    ANTENNAGATEAREA 0.196500 ;
    PORT
      LAYER met3 ;
        RECT 846.000 482.840 850.000 483.440 ;
    END
  END data_in[89]
  PIN data_in[8]
    DIRECTION INPUT ;
    USE SIGNAL ;
    ANTENNAGATEAREA 0.196500 ;
    PORT
      LAYER met3 ;
        RECT 846.000 612.040 850.000 612.640 ;
    END
  END data_in[8]
  PIN data_in[90]
    DIRECTION INPUT ;
    USE SIGNAL ;
    ANTENNAGATEAREA 0.196500 ;
    PORT
      LAYER met3 ;
        RECT 846.000 455.640 850.000 456.240 ;
    END
  END data_in[90]
  PIN data_in[91]
    DIRECTION INPUT ;
    USE SIGNAL ;
    ANTENNAGATEAREA 0.196500 ;
    PORT
      LAYER met3 ;
        RECT 846.000 275.440 850.000 276.040 ;
    END
  END data_in[91]
  PIN data_in[92]
    DIRECTION INPUT ;
    USE SIGNAL ;
    ANTENNAGATEAREA 0.196500 ;
    PORT
      LAYER met3 ;
        RECT 846.000 537.240 850.000 537.840 ;
    END
  END data_in[92]
  PIN data_in[93]
    DIRECTION INPUT ;
    USE SIGNAL ;
    ANTENNAGATEAREA 0.196500 ;
    PORT
      LAYER met3 ;
        RECT 846.000 309.440 850.000 310.040 ;
    END
  END data_in[93]
  PIN data_in[94]
    DIRECTION INPUT ;
    USE SIGNAL ;
    ANTENNAGATEAREA 0.196500 ;
    PORT
      LAYER met3 ;
        RECT 846.000 47.640 850.000 48.240 ;
    END
  END data_in[94]
  PIN data_in[95]
    DIRECTION INPUT ;
    USE SIGNAL ;
    ANTENNAGATEAREA 0.196500 ;
    PORT
      LAYER met3 ;
        RECT 846.000 387.640 850.000 388.240 ;
    END
  END data_in[95]
  PIN data_in[96]
    DIRECTION INPUT ;
    USE SIGNAL ;
    ANTENNAGATEAREA 0.196500 ;
    PORT
      LAYER met3 ;
        RECT 846.000 622.240 850.000 622.840 ;
    END
  END data_in[96]
  PIN data_in[97]
    DIRECTION INPUT ;
    USE SIGNAL ;
    ANTENNAGATEAREA 0.196500 ;
    PORT
      LAYER met3 ;
        RECT 846.000 581.440 850.000 582.040 ;
    END
  END data_in[97]
  PIN data_in[98]
    DIRECTION INPUT ;
    USE SIGNAL ;
    ANTENNAGATEAREA 0.196500 ;
    PORT
      LAYER met3 ;
        RECT 846.000 289.040 850.000 289.640 ;
    END
  END data_in[98]
  PIN data_in[99]
    DIRECTION INPUT ;
    USE SIGNAL ;
    ANTENNAGATEAREA 0.196500 ;
    PORT
      LAYER met3 ;
        RECT 846.000 302.640 850.000 303.240 ;
    END
  END data_in[99]
  PIN data_in[9]
    DIRECTION INPUT ;
    USE SIGNAL ;
    ANTENNAGATEAREA 0.196500 ;
    PORT
      LAYER met3 ;
        RECT 846.000 340.040 850.000 340.640 ;
    END
  END data_in[9]
  PIN data_length[0]
    DIRECTION INPUT ;
    USE SIGNAL ;
    ANTENNAGATEAREA 0.159000 ;
    PORT
      LAYER met3 ;
        RECT 846.000 163.240 850.000 163.840 ;
    END
  END data_length[0]
  PIN data_length[1]
    DIRECTION INPUT ;
    USE SIGNAL ;
    ANTENNAGATEAREA 0.213000 ;
    PORT
      LAYER met3 ;
        RECT 846.000 20.440 850.000 21.040 ;
    END
  END data_length[1]
  PIN data_length[2]
    DIRECTION INPUT ;
    USE SIGNAL ;
    ANTENNAGATEAREA 0.196500 ;
    PORT
      LAYER met3 ;
        RECT 846.000 377.440 850.000 378.040 ;
    END
  END data_length[2]
  PIN data_length[3]
    DIRECTION INPUT ;
    USE SIGNAL ;
    ANTENNAGATEAREA 0.196500 ;
    PORT
      LAYER met3 ;
        RECT 846.000 363.840 850.000 364.440 ;
    END
  END data_length[3]
  PIN data_length[4]
    DIRECTION INPUT ;
    USE SIGNAL ;
    ANTENNAGATEAREA 0.126000 ;
    PORT
      LAYER met3 ;
        RECT 846.000 652.840 850.000 653.440 ;
    END
  END data_length[4]
  PIN data_out[0]
    DIRECTION OUTPUT ;
    USE SIGNAL ;
    ANTENNADIFFAREA 0.445500 ;
    PORT
      LAYER met3 ;
        RECT 846.000 642.640 850.000 643.240 ;
    END
  END data_out[0]
  PIN data_out[100]
    DIRECTION OUTPUT ;
    USE SIGNAL ;
    ANTENNADIFFAREA 0.445500 ;
    PORT
      LAYER met2 ;
        RECT 351.070 846.000 351.350 850.000 ;
    END
  END data_out[100]
  PIN data_out[101]
    DIRECTION OUTPUT ;
    USE SIGNAL ;
    ANTENNADIFFAREA 0.445500 ;
    PORT
      LAYER met3 ;
        RECT 846.000 295.840 850.000 296.440 ;
    END
  END data_out[101]
  PIN data_out[102]
    DIRECTION OUTPUT ;
    USE SIGNAL ;
    ANTENNADIFFAREA 0.445500 ;
    PORT
      LAYER met3 ;
        RECT 846.000 51.040 850.000 51.640 ;
    END
  END data_out[102]
  PIN data_out[103]
    DIRECTION OUTPUT ;
    USE SIGNAL ;
    ANTENNADIFFAREA 0.445500 ;
    PORT
      LAYER met3 ;
        RECT 846.000 489.640 850.000 490.240 ;
    END
  END data_out[103]
  PIN data_out[104]
    DIRECTION OUTPUT ;
    USE SIGNAL ;
    ANTENNADIFFAREA 0.445500 ;
    PORT
      LAYER met3 ;
        RECT 846.000 629.040 850.000 629.640 ;
    END
  END data_out[104]
  PIN data_out[105]
    DIRECTION OUTPUT ;
    USE SIGNAL ;
    ANTENNADIFFAREA 0.445500 ;
    PORT
      LAYER met3 ;
        RECT 846.000 333.240 850.000 333.840 ;
    END
  END data_out[105]
  PIN data_out[106]
    DIRECTION OUTPUT ;
    USE SIGNAL ;
    ANTENNADIFFAREA 0.445500 ;
    PORT
      LAYER met3 ;
        RECT 846.000 146.240 850.000 146.840 ;
    END
  END data_out[106]
  PIN data_out[107]
    DIRECTION OUTPUT ;
    USE SIGNAL ;
    ANTENNADIFFAREA 0.445500 ;
    PORT
      LAYER met3 ;
        RECT 846.000 156.440 850.000 157.040 ;
    END
  END data_out[107]
  PIN data_out[108]
    DIRECTION OUTPUT ;
    USE SIGNAL ;
    ANTENNADIFFAREA 0.445500 ;
    PORT
      LAYER met3 ;
        RECT 846.000 193.840 850.000 194.440 ;
    END
  END data_out[108]
  PIN data_out[109]
    DIRECTION OUTPUT ;
    USE SIGNAL ;
    ANTENNADIFFAREA 0.445500 ;
    PORT
      LAYER met3 ;
        RECT 846.000 520.240 850.000 520.840 ;
    END
  END data_out[109]
  PIN data_out[10]
    DIRECTION OUTPUT ;
    USE SIGNAL ;
    ANTENNADIFFAREA 0.445500 ;
    PORT
      LAYER met3 ;
        RECT 846.000 119.040 850.000 119.640 ;
    END
  END data_out[10]
  PIN data_out[110]
    DIRECTION OUTPUT ;
    USE SIGNAL ;
    ANTENNADIFFAREA 0.445500 ;
    PORT
      LAYER met3 ;
        RECT 846.000 435.240 850.000 435.840 ;
    END
  END data_out[110]
  PIN data_out[111]
    DIRECTION OUTPUT ;
    USE SIGNAL ;
    ANTENNADIFFAREA 0.445500 ;
    PORT
      LAYER met3 ;
        RECT 846.000 527.040 850.000 527.640 ;
    END
  END data_out[111]
  PIN data_out[112]
    DIRECTION OUTPUT ;
    USE SIGNAL ;
    ANTENNADIFFAREA 0.445500 ;
    PORT
      LAYER met3 ;
        RECT 846.000 476.040 850.000 476.640 ;
    END
  END data_out[112]
  PIN data_out[113]
    DIRECTION OUTPUT ;
    USE SIGNAL ;
    ANTENNADIFFAREA 0.445500 ;
    PORT
      LAYER met3 ;
        RECT 846.000 268.640 850.000 269.240 ;
    END
  END data_out[113]
  PIN data_out[114]
    DIRECTION OUTPUT ;
    USE SIGNAL ;
    ANTENNADIFFAREA 0.445500 ;
    PORT
      LAYER met3 ;
        RECT 846.000 469.240 850.000 469.840 ;
    END
  END data_out[114]
  PIN data_out[115]
    DIRECTION OUTPUT ;
    USE SIGNAL ;
    ANTENNADIFFAREA 0.445500 ;
    PORT
      LAYER met3 ;
        RECT 846.000 312.840 850.000 313.440 ;
    END
  END data_out[115]
  PIN data_out[116]
    DIRECTION OUTPUT ;
    USE SIGNAL ;
    ANTENNADIFFAREA 0.445500 ;
    PORT
      LAYER met3 ;
        RECT 846.000 190.440 850.000 191.040 ;
    END
  END data_out[116]
  PIN data_out[117]
    DIRECTION OUTPUT ;
    USE SIGNAL ;
    ANTENNADIFFAREA 0.445500 ;
    PORT
      LAYER met3 ;
        RECT 846.000 452.240 850.000 452.840 ;
    END
  END data_out[117]
  PIN data_out[118]
    DIRECTION OUTPUT ;
    USE SIGNAL ;
    ANTENNADIFFAREA 0.445500 ;
    PORT
      LAYER met3 ;
        RECT 846.000 673.240 850.000 673.840 ;
    END
  END data_out[118]
  PIN data_out[119]
    DIRECTION OUTPUT ;
    USE SIGNAL ;
    ANTENNADIFFAREA 0.445500 ;
    PORT
      LAYER met3 ;
        RECT 846.000 513.440 850.000 514.040 ;
    END
  END data_out[119]
  PIN data_out[11]
    DIRECTION OUTPUT ;
    USE SIGNAL ;
    ANTENNADIFFAREA 0.445500 ;
    PORT
      LAYER met3 ;
        RECT 846.000 244.840 850.000 245.440 ;
    END
  END data_out[11]
  PIN data_out[120]
    DIRECTION OUTPUT ;
    USE SIGNAL ;
    ANTENNADIFFAREA 0.445500 ;
    PORT
      LAYER met3 ;
        RECT 846.000 421.640 850.000 422.240 ;
    END
  END data_out[120]
  PIN data_out[121]
    DIRECTION OUTPUT ;
    USE SIGNAL ;
    ANTENNADIFFAREA 0.445500 ;
    PORT
      LAYER met3 ;
        RECT 846.000 503.240 850.000 503.840 ;
    END
  END data_out[121]
  PIN data_out[122]
    DIRECTION OUTPUT ;
    USE SIGNAL ;
    ANTENNADIFFAREA 0.445500 ;
    PORT
      LAYER met3 ;
        RECT 846.000 578.040 850.000 578.640 ;
    END
  END data_out[122]
  PIN data_out[123]
    DIRECTION OUTPUT ;
    USE SIGNAL ;
    ANTENNADIFFAREA 0.445500 ;
    PORT
      LAYER met3 ;
        RECT 846.000 292.440 850.000 293.040 ;
    END
  END data_out[123]
  PIN data_out[124]
    DIRECTION OUTPUT ;
    USE SIGNAL ;
    ANTENNADIFFAREA 0.445500 ;
    PORT
      LAYER met3 ;
        RECT 846.000 646.040 850.000 646.640 ;
    END
  END data_out[124]
  PIN data_out[125]
    DIRECTION OUTPUT ;
    USE SIGNAL ;
    ANTENNADIFFAREA 0.445500 ;
    PORT
      LAYER met3 ;
        RECT 846.000 350.240 850.000 350.840 ;
    END
  END data_out[125]
  PIN data_out[126]
    DIRECTION OUTPUT ;
    USE SIGNAL ;
    ANTENNADIFFAREA 0.445500 ;
    PORT
      LAYER met3 ;
        RECT 846.000 23.840 850.000 24.440 ;
    END
  END data_out[126]
  PIN data_out[127]
    DIRECTION OUTPUT ;
    USE SIGNAL ;
    ANTENNADIFFAREA 0.445500 ;
    PORT
      LAYER met3 ;
        RECT 846.000 346.840 850.000 347.440 ;
    END
  END data_out[127]
  PIN data_out[12]
    DIRECTION OUTPUT ;
    USE SIGNAL ;
    ANTENNADIFFAREA 0.445500 ;
    PORT
      LAYER met3 ;
        RECT 846.000 217.640 850.000 218.240 ;
    END
  END data_out[12]
  PIN data_out[13]
    DIRECTION OUTPUT ;
    USE SIGNAL ;
    ANTENNADIFFAREA 0.445500 ;
    PORT
      LAYER met3 ;
        RECT 846.000 605.240 850.000 605.840 ;
    END
  END data_out[13]
  PIN data_out[14]
    DIRECTION OUTPUT ;
    USE SIGNAL ;
    ANTENNADIFFAREA 0.445500 ;
    PORT
      LAYER met3 ;
        RECT 846.000 571.240 850.000 571.840 ;
    END
  END data_out[14]
  PIN data_out[15]
    DIRECTION OUTPUT ;
    USE SIGNAL ;
    ANTENNADIFFAREA 0.445500 ;
    PORT
      LAYER met3 ;
        RECT 846.000 533.840 850.000 534.440 ;
    END
  END data_out[15]
  PIN data_out[16]
    DIRECTION OUTPUT ;
    USE SIGNAL ;
    ANTENNADIFFAREA 0.445500 ;
    PORT
      LAYER met3 ;
        RECT 846.000 639.240 850.000 639.840 ;
    END
  END data_out[16]
  PIN data_out[17]
    DIRECTION OUTPUT ;
    USE SIGNAL ;
    ANTENNADIFFAREA 0.445500 ;
    PORT
      LAYER met3 ;
        RECT 846.000 197.240 850.000 197.840 ;
    END
  END data_out[17]
  PIN data_out[18]
    DIRECTION OUTPUT ;
    USE SIGNAL ;
    ANTENNADIFFAREA 0.445500 ;
    PORT
      LAYER met3 ;
        RECT 846.000 472.640 850.000 473.240 ;
    END
  END data_out[18]
  PIN data_out[19]
    DIRECTION OUTPUT ;
    USE SIGNAL ;
    ANTENNADIFFAREA 0.445500 ;
    PORT
      LAYER met3 ;
        RECT 846.000 319.640 850.000 320.240 ;
    END
  END data_out[19]
  PIN data_out[1]
    DIRECTION OUTPUT ;
    USE SIGNAL ;
    ANTENNADIFFAREA 0.445500 ;
    PORT
      LAYER met3 ;
        RECT 846.000 564.440 850.000 565.040 ;
    END
  END data_out[1]
  PIN data_out[20]
    DIRECTION OUTPUT ;
    USE SIGNAL ;
    ANTENNADIFFAREA 0.445500 ;
    PORT
      LAYER met3 ;
        RECT 846.000 88.440 850.000 89.040 ;
    END
  END data_out[20]
  PIN data_out[21]
    DIRECTION OUTPUT ;
    USE SIGNAL ;
    ANTENNADIFFAREA 0.445500 ;
    PORT
      LAYER met3 ;
        RECT 846.000 635.840 850.000 636.440 ;
    END
  END data_out[21]
  PIN data_out[22]
    DIRECTION OUTPUT ;
    USE SIGNAL ;
    ANTENNADIFFAREA 0.445500 ;
    PORT
      LAYER met3 ;
        RECT 846.000 428.440 850.000 429.040 ;
    END
  END data_out[22]
  PIN data_out[23]
    DIRECTION OUTPUT ;
    USE SIGNAL ;
    ANTENNADIFFAREA 0.445500 ;
    PORT
      LAYER met3 ;
        RECT 846.000 717.440 850.000 718.040 ;
    END
  END data_out[23]
  PIN data_out[24]
    DIRECTION OUTPUT ;
    USE SIGNAL ;
    ANTENNADIFFAREA 0.445500 ;
    PORT
      LAYER met2 ;
        RECT 454.110 846.000 454.390 850.000 ;
    END
  END data_out[24]
  PIN data_out[25]
    DIRECTION OUTPUT ;
    USE SIGNAL ;
    ANTENNADIFFAREA 0.445500 ;
    PORT
      LAYER met2 ;
        RECT 669.850 0.000 670.130 4.000 ;
    END
  END data_out[25]
  PIN data_out[26]
    DIRECTION OUTPUT ;
    USE SIGNAL ;
    ANTENNADIFFAREA 0.445500 ;
    PORT
      LAYER met2 ;
        RECT 325.310 846.000 325.590 850.000 ;
    END
  END data_out[26]
  PIN data_out[27]
    DIRECTION OUTPUT ;
    USE SIGNAL ;
    ANTENNADIFFAREA 0.445500 ;
    PORT
      LAYER met2 ;
        RECT 740.690 0.000 740.970 4.000 ;
    END
  END data_out[27]
  PIN data_out[28]
    DIRECTION OUTPUT ;
    USE SIGNAL ;
    ANTENNADIFFAREA 0.445500 ;
    PORT
      LAYER met3 ;
        RECT 846.000 805.840 850.000 806.440 ;
    END
  END data_out[28]
  PIN data_out[29]
    DIRECTION OUTPUT ;
    USE SIGNAL ;
    ANTENNADIFFAREA 0.445500 ;
    PORT
      LAYER met2 ;
        RECT 663.410 0.000 663.690 4.000 ;
    END
  END data_out[29]
  PIN data_out[2]
    DIRECTION OUTPUT ;
    USE SIGNAL ;
    ANTENNADIFFAREA 0.445500 ;
    PORT
      LAYER met2 ;
        RECT 827.630 0.000 827.910 4.000 ;
    END
  END data_out[2]
  PIN data_out[30]
    DIRECTION OUTPUT ;
    USE SIGNAL ;
    ANTENNADIFFAREA 0.445500 ;
    PORT
      LAYER met2 ;
        RECT 727.810 0.000 728.090 4.000 ;
    END
  END data_out[30]
  PIN data_out[31]
    DIRECTION OUTPUT ;
    USE SIGNAL ;
    ANTENNADIFFAREA 0.445500 ;
    PORT
      LAYER met2 ;
        RECT 660.190 0.000 660.470 4.000 ;
    END
  END data_out[31]
  PIN data_out[32]
    DIRECTION OUTPUT ;
    USE SIGNAL ;
    ANTENNADIFFAREA 0.445500 ;
    PORT
      LAYER met2 ;
        RECT 653.750 0.000 654.030 4.000 ;
    END
  END data_out[32]
  PIN data_out[33]
    DIRECTION OUTPUT ;
    USE SIGNAL ;
    ANTENNADIFFAREA 0.445500 ;
    PORT
      LAYER met3 ;
        RECT 846.000 724.240 850.000 724.840 ;
    END
  END data_out[33]
  PIN data_out[34]
    DIRECTION OUTPUT ;
    USE SIGNAL ;
    ANTENNADIFFAREA 0.445500 ;
    PORT
      LAYER met2 ;
        RECT 747.130 0.000 747.410 4.000 ;
    END
  END data_out[34]
  PIN data_out[35]
    DIRECTION OUTPUT ;
    USE SIGNAL ;
    ANTENNADIFFAREA 0.445500 ;
    PORT
      LAYER met2 ;
        RECT 795.430 0.000 795.710 4.000 ;
    END
  END data_out[35]
  PIN data_out[36]
    DIRECTION OUTPUT ;
    USE SIGNAL ;
    ANTENNADIFFAREA 0.445500 ;
    PORT
      LAYER met2 ;
        RECT 776.110 0.000 776.390 4.000 ;
    END
  END data_out[36]
  PIN data_out[37]
    DIRECTION OUTPUT ;
    USE SIGNAL ;
    ANTENNADIFFAREA 0.445500 ;
    PORT
      LAYER met2 ;
        RECT 734.250 0.000 734.530 4.000 ;
    END
  END data_out[37]
  PIN data_out[38]
    DIRECTION OUTPUT ;
    USE SIGNAL ;
    ANTENNADIFFAREA 0.445500 ;
    PORT
      LAYER met2 ;
        RECT 801.870 0.000 802.150 4.000 ;
    END
  END data_out[38]
  PIN data_out[39]
    DIRECTION OUTPUT ;
    USE SIGNAL ;
    ANTENNADIFFAREA 0.445500 ;
    PORT
      LAYER met2 ;
        RECT 560.370 846.000 560.650 850.000 ;
    END
  END data_out[39]
  PIN data_out[3]
    DIRECTION OUTPUT ;
    USE SIGNAL ;
    ANTENNADIFFAREA 0.445500 ;
    PORT
      LAYER met2 ;
        RECT 769.670 0.000 769.950 4.000 ;
    END
  END data_out[3]
  PIN data_out[40]
    DIRECTION OUTPUT ;
    USE SIGNAL ;
    ANTENNADIFFAREA 0.445500 ;
    PORT
      LAYER met3 ;
        RECT 846.000 754.840 850.000 755.440 ;
    END
  END data_out[40]
  PIN data_out[41]
    DIRECTION OUTPUT ;
    USE SIGNAL ;
    ANTENNADIFFAREA 0.445500 ;
    PORT
      LAYER met2 ;
        RECT 805.090 0.000 805.370 4.000 ;
    END
  END data_out[41]
  PIN data_out[42]
    DIRECTION OUTPUT ;
    USE SIGNAL ;
    ANTENNADIFFAREA 0.445500 ;
    PORT
      LAYER met2 ;
        RECT 647.310 0.000 647.590 4.000 ;
    END
  END data_out[42]
  PIN data_out[43]
    DIRECTION OUTPUT ;
    USE SIGNAL ;
    ANTENNADIFFAREA 0.445500 ;
    PORT
      LAYER met2 ;
        RECT 840.510 0.000 840.790 4.000 ;
    END
  END data_out[43]
  PIN data_out[44]
    DIRECTION OUTPUT ;
    USE SIGNAL ;
    ANTENNADIFFAREA 0.445500 ;
    PORT
      LAYER met2 ;
        RECT 679.510 0.000 679.790 4.000 ;
    END
  END data_out[44]
  PIN data_out[45]
    DIRECTION OUTPUT ;
    USE SIGNAL ;
    ANTENNADIFFAREA 0.445500 ;
    PORT
      LAYER met2 ;
        RECT 689.170 0.000 689.450 4.000 ;
    END
  END data_out[45]
  PIN data_out[46]
    DIRECTION OUTPUT ;
    USE SIGNAL ;
    ANTENNADIFFAREA 0.445500 ;
    PORT
      LAYER met3 ;
        RECT 846.000 782.040 850.000 782.640 ;
    END
  END data_out[46]
  PIN data_out[47]
    DIRECTION OUTPUT ;
    USE SIGNAL ;
    ANTENNADIFFAREA 0.445500 ;
    PORT
      LAYER met2 ;
        RECT 264.130 846.000 264.410 850.000 ;
    END
  END data_out[47]
  PIN data_out[48]
    DIRECTION OUTPUT ;
    USE SIGNAL ;
    ANTENNADIFFAREA 0.445500 ;
    PORT
      LAYER met2 ;
        RECT 698.830 0.000 699.110 4.000 ;
    END
  END data_out[48]
  PIN data_out[49]
    DIRECTION OUTPUT ;
    USE SIGNAL ;
    ANTENNADIFFAREA 0.445500 ;
    PORT
      LAYER met2 ;
        RECT 834.070 0.000 834.350 4.000 ;
    END
  END data_out[49]
  PIN data_out[4]
    DIRECTION OUTPUT ;
    USE SIGNAL ;
    ANTENNADIFFAREA 0.445500 ;
    PORT
      LAYER met2 ;
        RECT 817.970 0.000 818.250 4.000 ;
    END
  END data_out[4]
  PIN data_out[50]
    DIRECTION OUTPUT ;
    USE SIGNAL ;
    ANTENNADIFFAREA 0.445500 ;
    PORT
      LAYER met2 ;
        RECT 721.370 0.000 721.650 4.000 ;
    END
  END data_out[50]
  PIN data_out[51]
    DIRECTION OUTPUT ;
    USE SIGNAL ;
    ANTENNADIFFAREA 0.445500 ;
    PORT
      LAYER met2 ;
        RECT 779.330 0.000 779.610 4.000 ;
    END
  END data_out[51]
  PIN data_out[52]
    DIRECTION OUTPUT ;
    USE SIGNAL ;
    ANTENNADIFFAREA 0.445500 ;
    PORT
      LAYER met2 ;
        RECT 650.530 0.000 650.810 4.000 ;
    END
  END data_out[52]
  PIN data_out[53]
    DIRECTION OUTPUT ;
    USE SIGNAL ;
    ANTENNADIFFAREA 0.445500 ;
    PORT
      LAYER met3 ;
        RECT 846.000 795.640 850.000 796.240 ;
    END
  END data_out[53]
  PIN data_out[54]
    DIRECTION OUTPUT ;
    USE SIGNAL ;
    ANTENNADIFFAREA 0.445500 ;
    PORT
      LAYER met2 ;
        RECT 644.090 0.000 644.370 4.000 ;
    END
  END data_out[54]
  PIN data_out[55]
    DIRECTION OUTPUT ;
    USE SIGNAL ;
    ANTENNADIFFAREA 0.445500 ;
    PORT
      LAYER met3 ;
        RECT 846.000 758.240 850.000 758.840 ;
    END
  END data_out[55]
  PIN data_out[56]
    DIRECTION OUTPUT ;
    USE SIGNAL ;
    ANTENNADIFFAREA 0.445500 ;
    PORT
      LAYER met2 ;
        RECT 254.470 846.000 254.750 850.000 ;
    END
  END data_out[56]
  PIN data_out[57]
    DIRECTION OUTPUT ;
    USE SIGNAL ;
    ANTENNADIFFAREA 0.445500 ;
    PORT
      LAYER met3 ;
        RECT 846.000 771.840 850.000 772.440 ;
    END
  END data_out[57]
  PIN data_out[58]
    DIRECTION OUTPUT ;
    USE SIGNAL ;
    ANTENNADIFFAREA 0.445500 ;
    PORT
      LAYER met2 ;
        RECT 489.530 846.000 489.810 850.000 ;
    END
  END data_out[58]
  PIN data_out[59]
    DIRECTION OUTPUT ;
    USE SIGNAL ;
    ANTENNADIFFAREA 0.445500 ;
    PORT
      LAYER met2 ;
        RECT 737.470 0.000 737.750 4.000 ;
    END
  END data_out[59]
  PIN data_out[5]
    DIRECTION OUTPUT ;
    USE SIGNAL ;
    ANTENNADIFFAREA 0.445500 ;
    PORT
      LAYER met2 ;
        RECT 685.950 0.000 686.230 4.000 ;
    END
  END data_out[5]
  PIN data_out[60]
    DIRECTION OUTPUT ;
    USE SIGNAL ;
    ANTENNADIFFAREA 0.445500 ;
    PORT
      LAYER met3 ;
        RECT 846.000 775.240 850.000 775.840 ;
    END
  END data_out[60]
  PIN data_out[61]
    DIRECTION OUTPUT ;
    USE SIGNAL ;
    ANTENNADIFFAREA 0.445500 ;
    PORT
      LAYER met2 ;
        RECT 692.390 0.000 692.670 4.000 ;
    END
  END data_out[61]
  PIN data_out[62]
    DIRECTION OUTPUT ;
    USE SIGNAL ;
    ANTENNADIFFAREA 0.445500 ;
    PORT
      LAYER met2 ;
        RECT 32.290 0.000 32.570 4.000 ;
    END
  END data_out[62]
  PIN data_out[63]
    DIRECTION OUTPUT ;
    USE SIGNAL ;
    ANTENNADIFFAREA 0.445500 ;
    PORT
      LAYER met2 ;
        RECT 322.090 846.000 322.370 850.000 ;
    END
  END data_out[63]
  PIN data_out[64]
    DIRECTION OUTPUT ;
    USE SIGNAL ;
    ANTENNADIFFAREA 0.445500 ;
    PORT
      LAYER met3 ;
        RECT 846.000 812.640 850.000 813.240 ;
    END
  END data_out[64]
  PIN data_out[65]
    DIRECTION OUTPUT ;
    USE SIGNAL ;
    ANTENNADIFFAREA 0.445500 ;
    PORT
      LAYER met2 ;
        RECT 631.210 846.000 631.490 850.000 ;
    END
  END data_out[65]
  PIN data_out[66]
    DIRECTION OUTPUT ;
    USE SIGNAL ;
    ANTENNADIFFAREA 0.445500 ;
    PORT
      LAYER met3 ;
        RECT 846.000 686.840 850.000 687.440 ;
    END
  END data_out[66]
  PIN data_out[67]
    DIRECTION OUTPUT ;
    USE SIGNAL ;
    ANTENNADIFFAREA 0.445500 ;
    PORT
      LAYER met3 ;
        RECT 846.000 720.840 850.000 721.440 ;
    END
  END data_out[67]
  PIN data_out[68]
    DIRECTION OUTPUT ;
    USE SIGNAL ;
    ANTENNADIFFAREA 0.445500 ;
    PORT
      LAYER met2 ;
        RECT 328.530 846.000 328.810 850.000 ;
    END
  END data_out[68]
  PIN data_out[69]
    DIRECTION OUTPUT ;
    USE SIGNAL ;
    ANTENNADIFFAREA 0.445500 ;
    PORT
      LAYER met2 ;
        RECT 74.150 0.000 74.430 4.000 ;
    END
  END data_out[69]
  PIN data_out[6]
    DIRECTION OUTPUT ;
    USE SIGNAL ;
    ANTENNADIFFAREA 0.445500 ;
    PORT
      LAYER met2 ;
        RECT 3.310 0.000 3.590 4.000 ;
    END
  END data_out[6]
  PIN data_out[70]
    DIRECTION OUTPUT ;
    USE SIGNAL ;
    ANTENNADIFFAREA 0.445500 ;
    PORT
      LAYER met2 ;
        RECT 627.990 0.000 628.270 4.000 ;
    END
  END data_out[70]
  PIN data_out[71]
    DIRECTION OUTPUT ;
    USE SIGNAL ;
    ANTENNADIFFAREA 0.445500 ;
    PORT
      LAYER met2 ;
        RECT 553.930 846.000 554.210 850.000 ;
    END
  END data_out[71]
  PIN data_out[72]
    DIRECTION OUTPUT ;
    USE SIGNAL ;
    ANTENNADIFFAREA 0.445500 ;
    PORT
      LAYER met2 ;
        RECT 267.350 846.000 267.630 850.000 ;
    END
  END data_out[72]
  PIN data_out[73]
    DIRECTION OUTPUT ;
    USE SIGNAL ;
    ANTENNADIFFAREA 0.445500 ;
    PORT
      LAYER met3 ;
        RECT 846.000 809.240 850.000 809.840 ;
    END
  END data_out[73]
  PIN data_out[74]
    DIRECTION OUTPUT ;
    USE SIGNAL ;
    ANTENNADIFFAREA 0.445500 ;
    PORT
      LAYER met2 ;
        RECT 16.190 0.000 16.470 4.000 ;
    END
  END data_out[74]
  PIN data_out[75]
    DIRECTION OUTPUT ;
    USE SIGNAL ;
    ANTENNADIFFAREA 0.445500 ;
    PORT
      LAYER met2 ;
        RECT 6.530 0.000 6.810 4.000 ;
    END
  END data_out[75]
  PIN data_out[76]
    DIRECTION OUTPUT ;
    USE SIGNAL ;
    ANTENNADIFFAREA 0.445500 ;
    PORT
      LAYER met2 ;
        RECT 9.750 0.000 10.030 4.000 ;
    END
  END data_out[76]
  PIN data_out[77]
    DIRECTION OUTPUT ;
    USE SIGNAL ;
    ANTENNADIFFAREA 0.445500 ;
    PORT
      LAYER met3 ;
        RECT 846.000 697.040 850.000 697.640 ;
    END
  END data_out[77]
  PIN data_out[78]
    DIRECTION OUTPUT ;
    USE SIGNAL ;
    ANTENNADIFFAREA 0.445500 ;
    PORT
      LAYER met3 ;
        RECT 846.000 693.640 850.000 694.240 ;
    END
  END data_out[78]
  PIN data_out[79]
    DIRECTION OUTPUT ;
    USE SIGNAL ;
    ANTENNADIFFAREA 0.445500 ;
    PORT
      LAYER met2 ;
        RECT 219.050 846.000 219.330 850.000 ;
    END
  END data_out[79]
  PIN data_out[7]
    DIRECTION OUTPUT ;
    USE SIGNAL ;
    ANTENNADIFFAREA 0.445500 ;
    PORT
      LAYER met2 ;
        RECT 260.910 846.000 261.190 850.000 ;
    END
  END data_out[7]
  PIN data_out[80]
    DIRECTION OUTPUT ;
    USE SIGNAL ;
    ANTENNADIFFAREA 0.445500 ;
    PORT
      LAYER met3 ;
        RECT 846.000 748.040 850.000 748.640 ;
    END
  END data_out[80]
  PIN data_out[81]
    DIRECTION OUTPUT ;
    USE SIGNAL ;
    ANTENNADIFFAREA 0.445500 ;
    PORT
      LAYER met2 ;
        RECT 0.090 0.000 0.370 4.000 ;
    END
  END data_out[81]
  PIN data_out[82]
    DIRECTION OUTPUT ;
    USE SIGNAL ;
    ANTENNADIFFAREA 0.445500 ;
    PORT
      LAYER met3 ;
        RECT 846.000 731.040 850.000 731.640 ;
    END
  END data_out[82]
  PIN data_out[83]
    DIRECTION OUTPUT ;
    USE SIGNAL ;
    ANTENNADIFFAREA 0.445500 ;
    PORT
      LAYER met3 ;
        RECT 846.000 690.240 850.000 690.840 ;
    END
  END data_out[83]
  PIN data_out[84]
    DIRECTION OUTPUT ;
    USE SIGNAL ;
    ANTENNADIFFAREA 0.445500 ;
    PORT
      LAYER met2 ;
        RECT 61.270 0.000 61.550 4.000 ;
    END
  END data_out[84]
  PIN data_out[85]
    DIRECTION OUTPUT ;
    USE SIGNAL ;
    ANTENNADIFFAREA 0.445500 ;
    PORT
      LAYER met3 ;
        RECT 846.000 816.040 850.000 816.640 ;
    END
  END data_out[85]
  PIN data_out[86]
    DIRECTION OUTPUT ;
    USE SIGNAL ;
    ANTENNADIFFAREA 0.445500 ;
    PORT
      LAYER met2 ;
        RECT 634.430 846.000 634.710 850.000 ;
    END
  END data_out[86]
  PIN data_out[87]
    DIRECTION OUTPUT ;
    USE SIGNAL ;
    ANTENNADIFFAREA 0.445500 ;
    PORT
      LAYER met3 ;
        RECT 846.000 741.240 850.000 741.840 ;
    END
  END data_out[87]
  PIN data_out[88]
    DIRECTION OUTPUT ;
    USE SIGNAL ;
    ANTENNADIFFAREA 0.445500 ;
    PORT
      LAYER met2 ;
        RECT 570.030 846.000 570.310 850.000 ;
    END
  END data_out[88]
  PIN data_out[89]
    DIRECTION OUTPUT ;
    USE SIGNAL ;
    ANTENNADIFFAREA 0.445500 ;
    PORT
      LAYER met2 ;
        RECT 363.950 846.000 364.230 850.000 ;
    END
  END data_out[89]
  PIN data_out[8]
    DIRECTION OUTPUT ;
    USE SIGNAL ;
    ANTENNADIFFAREA 0.445500 ;
    PORT
      LAYER met2 ;
        RECT 318.870 846.000 319.150 850.000 ;
    END
  END data_out[8]
  PIN data_out[90]
    DIRECTION OUTPUT ;
    USE SIGNAL ;
    ANTENNADIFFAREA 0.445500 ;
    PORT
      LAYER met2 ;
        RECT 251.250 846.000 251.530 850.000 ;
    END
  END data_out[90]
  PIN data_out[91]
    DIRECTION OUTPUT ;
    USE SIGNAL ;
    ANTENNADIFFAREA 0.445500 ;
    PORT
      LAYER met3 ;
        RECT 846.000 839.840 850.000 840.440 ;
    END
  END data_out[91]
  PIN data_out[92]
    DIRECTION OUTPUT ;
    USE SIGNAL ;
    ANTENNADIFFAREA 0.445500 ;
    PORT
      LAYER met3 ;
        RECT 846.000 744.640 850.000 745.240 ;
    END
  END data_out[92]
  PIN data_out[93]
    DIRECTION OUTPUT ;
    USE SIGNAL ;
    ANTENNADIFFAREA 0.445500 ;
    PORT
      LAYER met3 ;
        RECT 846.000 819.440 850.000 820.040 ;
    END
  END data_out[93]
  PIN data_out[94]
    DIRECTION OUTPUT ;
    USE SIGNAL ;
    ANTENNADIFFAREA 0.445500 ;
    PORT
      LAYER met2 ;
        RECT 331.750 846.000 332.030 850.000 ;
    END
  END data_out[94]
  PIN data_out[95]
    DIRECTION OUTPUT ;
    USE SIGNAL ;
    ANTENNADIFFAREA 0.445500 ;
    PORT
      LAYER met2 ;
        RECT 576.470 846.000 576.750 850.000 ;
    END
  END data_out[95]
  PIN data_out[96]
    DIRECTION OUTPUT ;
    USE SIGNAL ;
    ANTENNADIFFAREA 0.445500 ;
    PORT
      LAYER met3 ;
        RECT 846.000 846.640 850.000 847.240 ;
    END
  END data_out[96]
  PIN data_out[97]
    DIRECTION OUTPUT ;
    USE SIGNAL ;
    ANTENNADIFFAREA 0.445500 ;
    PORT
      LAYER met2 ;
        RECT 547.490 846.000 547.770 850.000 ;
    END
  END data_out[97]
  PIN data_out[98]
    DIRECTION OUTPUT ;
    USE SIGNAL ;
    ANTENNADIFFAREA 0.445500 ;
    PORT
      LAYER met2 ;
        RECT 22.630 0.000 22.910 4.000 ;
    END
  END data_out[98]
  PIN data_out[99]
    DIRECTION OUTPUT ;
    USE SIGNAL ;
    ANTENNADIFFAREA 0.445500 ;
    PORT
      LAYER met3 ;
        RECT 846.000 826.240 850.000 826.840 ;
    END
  END data_out[99]
  PIN data_out[9]
    DIRECTION OUTPUT ;
    USE SIGNAL ;
    ANTENNADIFFAREA 0.445500 ;
    PORT
      LAYER met3 ;
        RECT 846.000 822.840 850.000 823.440 ;
    END
  END data_out[9]
  PIN done
    DIRECTION OUTPUT ;
    USE SIGNAL ;
    ANTENNADIFFAREA 0.445500 ;
    PORT
      LAYER met2 ;
        RECT 383.270 846.000 383.550 850.000 ;
    END
  END done
  PIN ena
    DIRECTION INPUT ;
    USE SIGNAL ;
    ANTENNAGATEAREA 0.213000 ;
    PORT
      LAYER met2 ;
        RECT 409.030 846.000 409.310 850.000 ;
    END
  END ena
  PIN key[0]
    DIRECTION INPUT ;
    USE SIGNAL ;
    ANTENNAGATEAREA 0.196500 ;
    PORT
      LAYER met2 ;
        RECT 405.810 0.000 406.090 4.000 ;
    END
  END key[0]
  PIN key[100]
    DIRECTION INPUT ;
    USE SIGNAL ;
    ANTENNAGATEAREA 0.196500 ;
    PORT
      LAYER met2 ;
        RECT 83.810 0.000 84.090 4.000 ;
    END
  END key[100]
  PIN key[101]
    DIRECTION INPUT ;
    USE SIGNAL ;
    ANTENNAGATEAREA 0.213000 ;
    PORT
      LAYER met2 ;
        RECT 64.490 0.000 64.770 4.000 ;
    END
  END key[101]
  PIN key[102]
    DIRECTION INPUT ;
    USE SIGNAL ;
    ANTENNAGATEAREA 0.196500 ;
    PORT
      LAYER met2 ;
        RECT 566.810 0.000 567.090 4.000 ;
    END
  END key[102]
  PIN key[103]
    DIRECTION INPUT ;
    USE SIGNAL ;
    ANTENNAGATEAREA 0.159000 ;
    PORT
      LAYER met2 ;
        RECT 412.250 846.000 412.530 850.000 ;
    END
  END key[103]
  PIN key[104]
    DIRECTION INPUT ;
    USE SIGNAL ;
    ANTENNAGATEAREA 0.213000 ;
    PORT
      LAYER met2 ;
        RECT 87.030 0.000 87.310 4.000 ;
    END
  END key[104]
  PIN key[105]
    DIRECTION INPUT ;
    USE SIGNAL ;
    ANTENNAGATEAREA 0.159000 ;
    PORT
      LAYER met2 ;
        RECT 209.390 846.000 209.670 850.000 ;
    END
  END key[105]
  PIN key[106]
    DIRECTION INPUT ;
    USE SIGNAL ;
    ANTENNAGATEAREA 0.196500 ;
    PORT
      LAYER met2 ;
        RECT 206.170 0.000 206.450 4.000 ;
    END
  END key[106]
  PIN key[107]
    DIRECTION INPUT ;
    USE SIGNAL ;
    ANTENNAGATEAREA 0.247500 ;
    PORT
      LAYER met2 ;
        RECT 25.850 0.000 26.130 4.000 ;
    END
  END key[107]
  PIN key[108]
    DIRECTION INPUT ;
    USE SIGNAL ;
    ANTENNAGATEAREA 0.196500 ;
    PORT
      LAYER met2 ;
        RECT 434.790 0.000 435.070 4.000 ;
    END
  END key[108]
  PIN key[109]
    DIRECTION INPUT ;
    USE SIGNAL ;
    ANTENNAGATEAREA 0.196500 ;
    PORT
      LAYER met2 ;
        RECT 531.390 0.000 531.670 4.000 ;
    END
  END key[109]
  PIN key[10]
    DIRECTION INPUT ;
    USE SIGNAL ;
    ANTENNAGATEAREA 0.196500 ;
    PORT
      LAYER met2 ;
        RECT 228.710 0.000 228.990 4.000 ;
    END
  END key[10]
  PIN key[110]
    DIRECTION INPUT ;
    USE SIGNAL ;
    ANTENNAGATEAREA 0.196500 ;
    PORT
      LAYER met2 ;
        RECT 360.730 0.000 361.010 4.000 ;
    END
  END key[110]
  PIN key[111]
    DIRECTION INPUT ;
    USE SIGNAL ;
    ANTENNAGATEAREA 0.196500 ;
    PORT
      LAYER met2 ;
        RECT 570.030 0.000 570.310 4.000 ;
    END
  END key[111]
  PIN key[112]
    DIRECTION INPUT ;
    USE SIGNAL ;
    ANTENNAGATEAREA 0.196500 ;
    PORT
      LAYER met2 ;
        RECT 325.310 0.000 325.590 4.000 ;
    END
  END key[112]
  PIN key[113]
    DIRECTION INPUT ;
    USE SIGNAL ;
    ANTENNAGATEAREA 0.247500 ;
    PORT
      LAYER met2 ;
        RECT 96.690 0.000 96.970 4.000 ;
    END
  END key[113]
  PIN key[114]
    DIRECTION INPUT ;
    USE SIGNAL ;
    ANTENNAGATEAREA 0.196500 ;
    PORT
      LAYER met2 ;
        RECT 573.250 0.000 573.530 4.000 ;
    END
  END key[114]
  PIN key[115]
    DIRECTION INPUT ;
    USE SIGNAL ;
    ANTENNAGATEAREA 0.196500 ;
    PORT
      LAYER met2 ;
        RECT 141.770 0.000 142.050 4.000 ;
    END
  END key[115]
  PIN key[116]
    DIRECTION INPUT ;
    USE SIGNAL ;
    ANTENNAGATEAREA 0.196500 ;
    PORT
      LAYER met2 ;
        RECT 466.990 0.000 467.270 4.000 ;
    END
  END key[116]
  PIN key[117]
    DIRECTION INPUT ;
    USE SIGNAL ;
    ANTENNAGATEAREA 0.196500 ;
    PORT
      LAYER met2 ;
        RECT 54.830 0.000 55.110 4.000 ;
    END
  END key[117]
  PIN key[118]
    DIRECTION INPUT ;
    USE SIGNAL ;
    ANTENNAGATEAREA 0.196500 ;
    PORT
      LAYER met2 ;
        RECT 508.850 0.000 509.130 4.000 ;
    END
  END key[118]
  PIN key[119]
    DIRECTION INPUT ;
    USE SIGNAL ;
    ANTENNAGATEAREA 0.196500 ;
    PORT
      LAYER met2 ;
        RECT 541.050 0.000 541.330 4.000 ;
    END
  END key[119]
  PIN key[11]
    DIRECTION INPUT ;
    USE SIGNAL ;
    ANTENNAGATEAREA 0.196500 ;
    PORT
      LAYER met2 ;
        RECT 618.330 0.000 618.610 4.000 ;
    END
  END key[11]
  PIN key[120]
    DIRECTION INPUT ;
    USE SIGNAL ;
    ANTENNAGATEAREA 0.159000 ;
    PORT
      LAYER met2 ;
        RECT 116.010 0.000 116.290 4.000 ;
    END
  END key[120]
  PIN key[121]
    DIRECTION INPUT ;
    USE SIGNAL ;
    ANTENNAGATEAREA 0.196500 ;
    PORT
      LAYER met2 ;
        RECT 70.930 0.000 71.210 4.000 ;
    END
  END key[121]
  PIN key[122]
    DIRECTION INPUT ;
    USE SIGNAL ;
    ANTENNAGATEAREA 0.196500 ;
    PORT
      LAYER met2 ;
        RECT 615.110 0.000 615.390 4.000 ;
    END
  END key[122]
  PIN key[123]
    DIRECTION INPUT ;
    USE SIGNAL ;
    ANTENNAGATEAREA 0.196500 ;
    PORT
      LAYER met2 ;
        RECT 524.950 0.000 525.230 4.000 ;
    END
  END key[123]
  PIN key[124]
    DIRECTION INPUT ;
    USE SIGNAL ;
    ANTENNAGATEAREA 0.159000 ;
    PORT
      LAYER met2 ;
        RECT 322.090 0.000 322.370 4.000 ;
    END
  END key[124]
  PIN key[125]
    DIRECTION INPUT ;
    USE SIGNAL ;
    ANTENNAGATEAREA 0.159000 ;
    PORT
      LAYER met2 ;
        RECT 112.790 0.000 113.070 4.000 ;
    END
  END key[125]
  PIN key[126]
    DIRECTION INPUT ;
    USE SIGNAL ;
    ANTENNAGATEAREA 0.196500 ;
    PORT
      LAYER met2 ;
        RECT 99.910 0.000 100.190 4.000 ;
    END
  END key[126]
  PIN key[127]
    DIRECTION INPUT ;
    USE SIGNAL ;
    ANTENNAGATEAREA 0.196500 ;
    PORT
      LAYER met2 ;
        RECT 354.290 0.000 354.570 4.000 ;
    END
  END key[127]
  PIN key[12]
    DIRECTION INPUT ;
    USE SIGNAL ;
    ANTENNAGATEAREA 0.196500 ;
    PORT
      LAYER met2 ;
        RECT 441.230 0.000 441.510 4.000 ;
    END
  END key[12]
  PIN key[13]
    DIRECTION INPUT ;
    USE SIGNAL ;
    ANTENNAGATEAREA 0.196500 ;
    PORT
      LAYER met2 ;
        RECT 563.590 0.000 563.870 4.000 ;
    END
  END key[13]
  PIN key[14]
    DIRECTION INPUT ;
    USE SIGNAL ;
    ANTENNAGATEAREA 0.196500 ;
    PORT
      LAYER met2 ;
        RECT 190.070 0.000 190.350 4.000 ;
    END
  END key[14]
  PIN key[15]
    DIRECTION INPUT ;
    USE SIGNAL ;
    ANTENNAGATEAREA 0.196500 ;
    PORT
      LAYER met2 ;
        RECT 576.470 0.000 576.750 4.000 ;
    END
  END key[15]
  PIN key[16]
    DIRECTION INPUT ;
    USE SIGNAL ;
    ANTENNAGATEAREA 0.196500 ;
    PORT
      LAYER met2 ;
        RECT 215.830 0.000 216.110 4.000 ;
    END
  END key[16]
  PIN key[17]
    DIRECTION INPUT ;
    USE SIGNAL ;
    ANTENNAGATEAREA 0.196500 ;
    PORT
      LAYER met2 ;
        RECT 544.270 0.000 544.550 4.000 ;
    END
  END key[17]
  PIN key[18]
    DIRECTION INPUT ;
    USE SIGNAL ;
    ANTENNAGATEAREA 0.196500 ;
    PORT
      LAYER met2 ;
        RECT 186.850 0.000 187.130 4.000 ;
    END
  END key[18]
  PIN key[19]
    DIRECTION INPUT ;
    USE SIGNAL ;
    ANTENNAGATEAREA 0.196500 ;
    PORT
      LAYER met2 ;
        RECT 106.350 0.000 106.630 4.000 ;
    END
  END key[19]
  PIN key[1]
    DIRECTION INPUT ;
    USE SIGNAL ;
    ANTENNAGATEAREA 0.213000 ;
    PORT
      LAYER met2 ;
        RECT 167.530 0.000 167.810 4.000 ;
    END
  END key[1]
  PIN key[20]
    DIRECTION INPUT ;
    USE SIGNAL ;
    ANTENNAGATEAREA 0.196500 ;
    PORT
      LAYER met2 ;
        RECT 457.330 0.000 457.610 4.000 ;
    END
  END key[20]
  PIN key[21]
    DIRECTION INPUT ;
    USE SIGNAL ;
    ANTENNAGATEAREA 0.196500 ;
    PORT
      LAYER met2 ;
        RECT 122.450 0.000 122.730 4.000 ;
    END
  END key[21]
  PIN key[22]
    DIRECTION INPUT ;
    USE SIGNAL ;
    ANTENNAGATEAREA 0.196500 ;
    PORT
      LAYER met2 ;
        RECT 380.050 0.000 380.330 4.000 ;
    END
  END key[22]
  PIN key[23]
    DIRECTION INPUT ;
    USE SIGNAL ;
    ANTENNAGATEAREA 0.196500 ;
    PORT
      LAYER met2 ;
        RECT 553.930 0.000 554.210 4.000 ;
    END
  END key[23]
  PIN key[24]
    DIRECTION INPUT ;
    USE SIGNAL ;
    ANTENNAGATEAREA 0.213000 ;
    PORT
      LAYER met2 ;
        RECT 67.710 0.000 67.990 4.000 ;
    END
  END key[24]
  PIN key[25]
    DIRECTION INPUT ;
    USE SIGNAL ;
    ANTENNAGATEAREA 0.196500 ;
    PORT
      LAYER met2 ;
        RECT 305.990 0.000 306.270 4.000 ;
    END
  END key[25]
  PIN key[26]
    DIRECTION INPUT ;
    USE SIGNAL ;
    ANTENNAGATEAREA 0.196500 ;
    PORT
      LAYER met2 ;
        RECT 631.210 0.000 631.490 4.000 ;
    END
  END key[26]
  PIN key[27]
    DIRECTION INPUT ;
    USE SIGNAL ;
    ANTENNAGATEAREA 0.196500 ;
    PORT
      LAYER met2 ;
        RECT 93.470 0.000 93.750 4.000 ;
    END
  END key[27]
  PIN key[28]
    DIRECTION INPUT ;
    USE SIGNAL ;
    ANTENNAGATEAREA 0.196500 ;
    PORT
      LAYER met2 ;
        RECT 605.450 0.000 605.730 4.000 ;
    END
  END key[28]
  PIN key[29]
    DIRECTION INPUT ;
    USE SIGNAL ;
    ANTENNAGATEAREA 0.196500 ;
    PORT
      LAYER met2 ;
        RECT 41.950 0.000 42.230 4.000 ;
    END
  END key[29]
  PIN key[2]
    DIRECTION INPUT ;
    USE SIGNAL ;
    ANTENNAGATEAREA 0.196500 ;
    PORT
      LAYER met2 ;
        RECT 77.370 0.000 77.650 4.000 ;
    END
  END key[2]
  PIN key[30]
    DIRECTION INPUT ;
    USE SIGNAL ;
    ANTENNAGATEAREA 0.196500 ;
    PORT
      LAYER met2 ;
        RECT 370.390 0.000 370.670 4.000 ;
    END
  END key[30]
  PIN key[31]
    DIRECTION INPUT ;
    USE SIGNAL ;
    ANTENNAGATEAREA 0.196500 ;
    PORT
      LAYER met2 ;
        RECT 289.890 0.000 290.170 4.000 ;
    END
  END key[31]
  PIN key[32]
    DIRECTION INPUT ;
    USE SIGNAL ;
    ANTENNAGATEAREA 0.196500 ;
    PORT
      LAYER met2 ;
        RECT 415.470 0.000 415.750 4.000 ;
    END
  END key[32]
  PIN key[33]
    DIRECTION INPUT ;
    USE SIGNAL ;
    ANTENNAGATEAREA 0.196500 ;
    PORT
      LAYER met2 ;
        RECT 479.870 0.000 480.150 4.000 ;
    END
  END key[33]
  PIN key[34]
    DIRECTION INPUT ;
    USE SIGNAL ;
    ANTENNAGATEAREA 0.196500 ;
    PORT
      LAYER met2 ;
        RECT 138.550 0.000 138.830 4.000 ;
    END
  END key[34]
  PIN key[35]
    DIRECTION INPUT ;
    USE SIGNAL ;
    ANTENNAGATEAREA 0.196500 ;
    PORT
      LAYER met2 ;
        RECT 373.610 0.000 373.890 4.000 ;
    END
  END key[35]
  PIN key[36]
    DIRECTION INPUT ;
    USE SIGNAL ;
    ANTENNAGATEAREA 0.196500 ;
    PORT
      LAYER met2 ;
        RECT 193.290 0.000 193.570 4.000 ;
    END
  END key[36]
  PIN key[37]
    DIRECTION INPUT ;
    USE SIGNAL ;
    ANTENNAGATEAREA 0.213000 ;
    PORT
      LAYER met2 ;
        RECT 264.130 0.000 264.410 4.000 ;
    END
  END key[37]
  PIN key[38]
    DIRECTION INPUT ;
    USE SIGNAL ;
    ANTENNAGATEAREA 0.196500 ;
    PORT
      LAYER met2 ;
        RECT 624.770 0.000 625.050 4.000 ;
    END
  END key[38]
  PIN key[39]
    DIRECTION INPUT ;
    USE SIGNAL ;
    ANTENNAGATEAREA 0.196500 ;
    PORT
      LAYER met2 ;
        RECT 589.350 0.000 589.630 4.000 ;
    END
  END key[39]
  PIN key[3]
    DIRECTION INPUT ;
    USE SIGNAL ;
    ANTENNAGATEAREA 0.196500 ;
    PORT
      LAYER met2 ;
        RECT 161.090 0.000 161.370 4.000 ;
    END
  END key[3]
  PIN key[40]
    DIRECTION INPUT ;
    USE SIGNAL ;
    ANTENNAGATEAREA 0.196500 ;
    PORT
      LAYER met2 ;
        RECT 483.090 0.000 483.370 4.000 ;
    END
  END key[40]
  PIN key[41]
    DIRECTION INPUT ;
    USE SIGNAL ;
    ANTENNAGATEAREA 0.196500 ;
    PORT
      LAYER met2 ;
        RECT 586.130 0.000 586.410 4.000 ;
    END
  END key[41]
  PIN key[42]
    DIRECTION INPUT ;
    USE SIGNAL ;
    ANTENNAGATEAREA 0.196500 ;
    PORT
      LAYER met2 ;
        RECT 148.210 0.000 148.490 4.000 ;
    END
  END key[42]
  PIN key[43]
    DIRECTION INPUT ;
    USE SIGNAL ;
    ANTENNAGATEAREA 0.196500 ;
    PORT
      LAYER met2 ;
        RECT 608.670 0.000 608.950 4.000 ;
    END
  END key[43]
  PIN key[44]
    DIRECTION INPUT ;
    USE SIGNAL ;
    ANTENNAGATEAREA 0.196500 ;
    PORT
      LAYER met2 ;
        RECT 438.010 0.000 438.290 4.000 ;
    END
  END key[44]
  PIN key[45]
    DIRECTION INPUT ;
    USE SIGNAL ;
    ANTENNAGATEAREA 0.159000 ;
    PORT
      LAYER met2 ;
        RECT 212.610 0.000 212.890 4.000 ;
    END
  END key[45]
  PIN key[46]
    DIRECTION INPUT ;
    USE SIGNAL ;
    ANTENNAGATEAREA 0.196500 ;
    PORT
      LAYER met2 ;
        RECT 177.190 0.000 177.470 4.000 ;
    END
  END key[46]
  PIN key[47]
    DIRECTION INPUT ;
    USE SIGNAL ;
    ANTENNAGATEAREA 0.196500 ;
    PORT
      LAYER met2 ;
        RECT 592.570 0.000 592.850 4.000 ;
    END
  END key[47]
  PIN key[48]
    DIRECTION INPUT ;
    USE SIGNAL ;
    ANTENNAGATEAREA 0.196500 ;
    PORT
      LAYER met2 ;
        RECT 389.710 0.000 389.990 4.000 ;
    END
  END key[48]
  PIN key[49]
    DIRECTION INPUT ;
    USE SIGNAL ;
    ANTENNAGATEAREA 0.196500 ;
    PORT
      LAYER met2 ;
        RECT 547.490 0.000 547.770 4.000 ;
    END
  END key[49]
  PIN key[4]
    DIRECTION INPUT ;
    USE SIGNAL ;
    ANTENNAGATEAREA 0.196500 ;
    PORT
      LAYER met2 ;
        RECT 103.130 0.000 103.410 4.000 ;
    END
  END key[4]
  PIN key[50]
    DIRECTION INPUT ;
    USE SIGNAL ;
    ANTENNAGATEAREA 0.196500 ;
    PORT
      LAYER met2 ;
        RECT 45.170 0.000 45.450 4.000 ;
    END
  END key[50]
  PIN key[51]
    DIRECTION INPUT ;
    USE SIGNAL ;
    ANTENNAGATEAREA 0.196500 ;
    PORT
      LAYER met2 ;
        RECT 273.790 0.000 274.070 4.000 ;
    END
  END key[51]
  PIN key[52]
    DIRECTION INPUT ;
    USE SIGNAL ;
    ANTENNAGATEAREA 0.196500 ;
    PORT
      LAYER met2 ;
        RECT 470.210 0.000 470.490 4.000 ;
    END
  END key[52]
  PIN key[53]
    DIRECTION INPUT ;
    USE SIGNAL ;
    ANTENNAGATEAREA 0.196500 ;
    PORT
      LAYER met2 ;
        RECT 209.390 0.000 209.670 4.000 ;
    END
  END key[53]
  PIN key[54]
    DIRECTION INPUT ;
    USE SIGNAL ;
    ANTENNAGATEAREA 0.196500 ;
    PORT
      LAYER met2 ;
        RECT 183.630 0.000 183.910 4.000 ;
    END
  END key[54]
  PIN key[55]
    DIRECTION INPUT ;
    USE SIGNAL ;
    ANTENNAGATEAREA 0.196500 ;
    PORT
      LAYER met2 ;
        RECT 550.710 0.000 550.990 4.000 ;
    END
  END key[55]
  PIN key[56]
    DIRECTION INPUT ;
    USE SIGNAL ;
    ANTENNAGATEAREA 0.196500 ;
    PORT
      LAYER met2 ;
        RECT 463.770 0.000 464.050 4.000 ;
    END
  END key[56]
  PIN key[57]
    DIRECTION INPUT ;
    USE SIGNAL ;
    ANTENNAGATEAREA 0.196500 ;
    PORT
      LAYER met2 ;
        RECT 144.990 0.000 145.270 4.000 ;
    END
  END key[57]
  PIN key[58]
    DIRECTION INPUT ;
    USE SIGNAL ;
    ANTENNAGATEAREA 0.196500 ;
    PORT
      LAYER met2 ;
        RECT 634.430 0.000 634.710 4.000 ;
    END
  END key[58]
  PIN key[59]
    DIRECTION INPUT ;
    USE SIGNAL ;
    ANTENNAGATEAREA 0.196500 ;
    PORT
      LAYER met2 ;
        RECT 357.510 0.000 357.790 4.000 ;
    END
  END key[59]
  PIN key[5]
    DIRECTION INPUT ;
    USE SIGNAL ;
    ANTENNAGATEAREA 0.196500 ;
    PORT
      LAYER met2 ;
        RECT 534.610 0.000 534.890 4.000 ;
    END
  END key[5]
  PIN key[60]
    DIRECTION INPUT ;
    USE SIGNAL ;
    ANTENNAGATEAREA 0.213000 ;
    PORT
      LAYER met2 ;
        RECT 58.050 0.000 58.330 4.000 ;
    END
  END key[60]
  PIN key[61]
    DIRECTION INPUT ;
    USE SIGNAL ;
    ANTENNAGATEAREA 0.196500 ;
    PORT
      LAYER met2 ;
        RECT 35.510 0.000 35.790 4.000 ;
    END
  END key[61]
  PIN key[62]
    DIRECTION INPUT ;
    USE SIGNAL ;
    ANTENNAGATEAREA 0.196500 ;
    PORT
      LAYER met2 ;
        RECT 318.870 0.000 319.150 4.000 ;
    END
  END key[62]
  PIN key[63]
    DIRECTION INPUT ;
    USE SIGNAL ;
    ANTENNAGATEAREA 0.196500 ;
    PORT
      LAYER met2 ;
        RECT 235.150 0.000 235.430 4.000 ;
    END
  END key[63]
  PIN key[64]
    DIRECTION INPUT ;
    USE SIGNAL ;
    ANTENNAGATEAREA 0.196500 ;
    PORT
      LAYER met2 ;
        RECT 270.570 0.000 270.850 4.000 ;
    END
  END key[64]
  PIN key[65]
    DIRECTION INPUT ;
    USE SIGNAL ;
    ANTENNAGATEAREA 0.196500 ;
    PORT
      LAYER met2 ;
        RECT 492.750 0.000 493.030 4.000 ;
    END
  END key[65]
  PIN key[66]
    DIRECTION INPUT ;
    USE SIGNAL ;
    ANTENNAGATEAREA 0.196500 ;
    PORT
      LAYER met2 ;
        RECT 312.430 0.000 312.710 4.000 ;
    END
  END key[66]
  PIN key[67]
    DIRECTION INPUT ;
    USE SIGNAL ;
    ANTENNAGATEAREA 0.159000 ;
    PORT
      LAYER met2 ;
        RECT 51.610 0.000 51.890 4.000 ;
    END
  END key[67]
  PIN key[68]
    DIRECTION INPUT ;
    USE SIGNAL ;
    ANTENNAGATEAREA 0.196500 ;
    PORT
      LAYER met2 ;
        RECT 277.010 0.000 277.290 4.000 ;
    END
  END key[68]
  PIN key[69]
    DIRECTION INPUT ;
    USE SIGNAL ;
    ANTENNAGATEAREA 0.196500 ;
    PORT
      LAYER met2 ;
        RECT 537.830 0.000 538.110 4.000 ;
    END
  END key[69]
  PIN key[6]
    DIRECTION INPUT ;
    USE SIGNAL ;
    ANTENNAGATEAREA 0.196500 ;
    PORT
      LAYER met2 ;
        RECT 611.890 0.000 612.170 4.000 ;
    END
  END key[6]
  PIN key[70]
    DIRECTION INPUT ;
    USE SIGNAL ;
    ANTENNAGATEAREA 0.196500 ;
    PORT
      LAYER met2 ;
        RECT 637.650 0.000 637.930 4.000 ;
    END
  END key[70]
  PIN key[71]
    DIRECTION INPUT ;
    USE SIGNAL ;
    ANTENNAGATEAREA 0.196500 ;
    PORT
      LAYER met2 ;
        RECT 595.790 0.000 596.070 4.000 ;
    END
  END key[71]
  PIN key[72]
    DIRECTION INPUT ;
    USE SIGNAL ;
    ANTENNAGATEAREA 0.196500 ;
    PORT
      LAYER met2 ;
        RECT 489.530 0.000 489.810 4.000 ;
    END
  END key[72]
  PIN key[73]
    DIRECTION INPUT ;
    USE SIGNAL ;
    ANTENNAGATEAREA 0.196500 ;
    PORT
      LAYER met2 ;
        RECT 599.010 0.000 599.290 4.000 ;
    END
  END key[73]
  PIN key[74]
    DIRECTION INPUT ;
    USE SIGNAL ;
    ANTENNAGATEAREA 0.196500 ;
    PORT
      LAYER met2 ;
        RECT 257.690 0.000 257.970 4.000 ;
    END
  END key[74]
  PIN key[75]
    DIRECTION INPUT ;
    USE SIGNAL ;
    ANTENNAGATEAREA 0.196500 ;
    PORT
      LAYER met2 ;
        RECT 621.550 0.000 621.830 4.000 ;
    END
  END key[75]
  PIN key[76]
    DIRECTION INPUT ;
    USE SIGNAL ;
    ANTENNAGATEAREA 0.196500 ;
    PORT
      LAYER met2 ;
        RECT 293.110 0.000 293.390 4.000 ;
    END
  END key[76]
  PIN key[77]
    DIRECTION INPUT ;
    USE SIGNAL ;
    ANTENNAGATEAREA 0.196500 ;
    PORT
      LAYER met2 ;
        RECT 579.690 0.000 579.970 4.000 ;
    END
  END key[77]
  PIN key[78]
    DIRECTION INPUT ;
    USE SIGNAL ;
    ANTENNAGATEAREA 0.196500 ;
    PORT
      LAYER met2 ;
        RECT 302.770 0.000 303.050 4.000 ;
    END
  END key[78]
  PIN key[79]
    DIRECTION INPUT ;
    USE SIGNAL ;
    ANTENNAGATEAREA 0.196500 ;
    PORT
      LAYER met2 ;
        RECT 602.230 0.000 602.510 4.000 ;
    END
  END key[79]
  PIN key[7]
    DIRECTION INPUT ;
    USE SIGNAL ;
    ANTENNAGATEAREA 0.196500 ;
    PORT
      LAYER met2 ;
        RECT 582.910 0.000 583.190 4.000 ;
    END
  END key[7]
  PIN key[80]
    DIRECTION INPUT ;
    USE SIGNAL ;
    ANTENNAGATEAREA 0.196500 ;
    PORT
      LAYER met2 ;
        RECT 280.230 0.000 280.510 4.000 ;
    END
  END key[80]
  PIN key[81]
    DIRECTION INPUT ;
    USE SIGNAL ;
    ANTENNAGATEAREA 0.196500 ;
    PORT
      LAYER met2 ;
        RECT 560.370 0.000 560.650 4.000 ;
    END
  END key[81]
  PIN key[82]
    DIRECTION INPUT ;
    USE SIGNAL ;
    ANTENNAGATEAREA 0.196500 ;
    PORT
      LAYER met2 ;
        RECT 19.410 0.000 19.690 4.000 ;
    END
  END key[82]
  PIN key[83]
    DIRECTION INPUT ;
    USE SIGNAL ;
    ANTENNAGATEAREA 0.196500 ;
    PORT
      LAYER met2 ;
        RECT 48.390 0.000 48.670 4.000 ;
    END
  END key[83]
  PIN key[84]
    DIRECTION INPUT ;
    USE SIGNAL ;
    ANTENNAGATEAREA 0.196500 ;
    PORT
      LAYER met2 ;
        RECT 460.550 0.000 460.830 4.000 ;
    END
  END key[84]
  PIN key[85]
    DIRECTION INPUT ;
    USE SIGNAL ;
    ANTENNAGATEAREA 0.196500 ;
    PORT
      LAYER met2 ;
        RECT 341.410 0.000 341.690 4.000 ;
    END
  END key[85]
  PIN key[86]
    DIRECTION INPUT ;
    USE SIGNAL ;
    ANTENNAGATEAREA 0.196500 ;
    PORT
      LAYER met2 ;
        RECT 90.250 0.000 90.530 4.000 ;
    END
  END key[86]
  PIN key[87]
    DIRECTION INPUT ;
    USE SIGNAL ;
    ANTENNAGATEAREA 0.196500 ;
    PORT
      LAYER met2 ;
        RECT 557.150 0.000 557.430 4.000 ;
    END
  END key[87]
  PIN key[88]
    DIRECTION INPUT ;
    USE SIGNAL ;
    ANTENNAGATEAREA 0.196500 ;
    PORT
      LAYER met2 ;
        RECT 473.430 0.000 473.710 4.000 ;
    END
  END key[88]
  PIN key[89]
    DIRECTION INPUT ;
    USE SIGNAL ;
    ANTENNAGATEAREA 0.196500 ;
    PORT
      LAYER met2 ;
        RECT 367.170 0.000 367.450 4.000 ;
    END
  END key[89]
  PIN key[8]
    DIRECTION INPUT ;
    USE SIGNAL ;
    ANTENNAGATEAREA 0.196500 ;
    PORT
      LAYER met2 ;
        RECT 338.190 0.000 338.470 4.000 ;
    END
  END key[8]
  PIN key[90]
    DIRECTION INPUT ;
    USE SIGNAL ;
    ANTENNAGATEAREA 0.196500 ;
    PORT
      LAYER met2 ;
        RECT 640.870 0.000 641.150 4.000 ;
    END
  END key[90]
  PIN key[91]
    DIRECTION INPUT ;
    USE SIGNAL ;
    ANTENNAGATEAREA 0.196500 ;
    PORT
      LAYER met2 ;
        RECT 80.590 0.000 80.870 4.000 ;
    END
  END key[91]
  PIN key[92]
    DIRECTION INPUT ;
    USE SIGNAL ;
    ANTENNAGATEAREA 0.247500 ;
    PORT
      LAYER met2 ;
        RECT 12.970 0.000 13.250 4.000 ;
    END
  END key[92]
  PIN key[93]
    DIRECTION INPUT ;
    USE SIGNAL ;
    ANTENNAGATEAREA 0.196500 ;
    PORT
      LAYER met2 ;
        RECT 351.070 0.000 351.350 4.000 ;
    END
  END key[93]
  PIN key[94]
    DIRECTION INPUT ;
    USE SIGNAL ;
    ANTENNAGATEAREA 0.196500 ;
    PORT
      LAYER met2 ;
        RECT 151.430 0.000 151.710 4.000 ;
    END
  END key[94]
  PIN key[95]
    DIRECTION INPUT ;
    USE SIGNAL ;
    ANTENNAGATEAREA 0.196500 ;
    PORT
      LAYER met2 ;
        RECT 164.310 0.000 164.590 4.000 ;
    END
  END key[95]
  PIN key[96]
    DIRECTION INPUT ;
    USE SIGNAL ;
    ANTENNAGATEAREA 0.213000 ;
    PORT
      LAYER met3 ;
        RECT 0.000 125.840 4.000 126.440 ;
    END
  END key[96]
  PIN key[97]
    DIRECTION INPUT ;
    USE SIGNAL ;
    ANTENNAGATEAREA 0.196500 ;
    PORT
      LAYER met3 ;
        RECT 0.000 10.240 4.000 10.840 ;
    END
  END key[97]
  PIN key[98]
    DIRECTION INPUT ;
    USE SIGNAL ;
    ANTENNAGATEAREA 0.196500 ;
    PORT
      LAYER met3 ;
        RECT 0.000 6.840 4.000 7.440 ;
    END
  END key[98]
  PIN key[99]
    DIRECTION INPUT ;
    USE SIGNAL ;
    ANTENNAGATEAREA 0.196500 ;
    PORT
      LAYER met2 ;
        RECT 460.550 846.000 460.830 850.000 ;
    END
  END key[99]
  PIN key[9]
    DIRECTION INPUT ;
    USE SIGNAL ;
    ANTENNAGATEAREA 0.247500 ;
    PORT
      LAYER met3 ;
        RECT 0.000 139.440 4.000 140.040 ;
    END
  END key[9]
  PIN nonce[0]
    DIRECTION INPUT ;
    USE SIGNAL ;
    ANTENNAGATEAREA 0.196500 ;
    PORT
      LAYER met2 ;
        RECT 396.150 846.000 396.430 850.000 ;
    END
  END nonce[0]
  PIN nonce[100]
    DIRECTION INPUT ;
    USE SIGNAL ;
    ANTENNAGATEAREA 0.196500 ;
    PORT
      LAYER met2 ;
        RECT 457.330 846.000 457.610 850.000 ;
    END
  END nonce[100]
  PIN nonce[101]
    DIRECTION INPUT ;
    USE SIGNAL ;
    ANTENNAGATEAREA 0.213000 ;
    PORT
      LAYER met3 ;
        RECT 0.000 108.840 4.000 109.440 ;
    END
  END nonce[101]
  PIN nonce[102]
    DIRECTION INPUT ;
    USE SIGNAL ;
    ANTENNAGATEAREA 0.495000 ;
    PORT
      LAYER met2 ;
        RECT 241.590 846.000 241.870 850.000 ;
    END
  END nonce[102]
  PIN nonce[103]
    DIRECTION INPUT ;
    USE SIGNAL ;
    ANTENNAGATEAREA 0.213000 ;
    PORT
      LAYER met2 ;
        RECT 402.590 846.000 402.870 850.000 ;
    END
  END nonce[103]
  PIN nonce[104]
    DIRECTION INPUT ;
    USE SIGNAL ;
    ANTENNAGATEAREA 0.213000 ;
    PORT
      LAYER met3 ;
        RECT 0.000 102.040 4.000 102.640 ;
    END
  END nonce[104]
  PIN nonce[105]
    DIRECTION INPUT ;
    USE SIGNAL ;
    ANTENNAGATEAREA 0.213000 ;
    PORT
      LAYER met2 ;
        RECT 405.810 846.000 406.090 850.000 ;
    END
  END nonce[105]
  PIN nonce[106]
    DIRECTION INPUT ;
    USE SIGNAL ;
    ANTENNAGATEAREA 0.213000 ;
    PORT
      LAYER met3 ;
        RECT 0.000 20.440 4.000 21.040 ;
    END
  END nonce[106]
  PIN nonce[107]
    DIRECTION INPUT ;
    USE SIGNAL ;
    ANTENNAGATEAREA 0.247500 ;
    PORT
      LAYER met2 ;
        RECT 541.050 846.000 541.330 850.000 ;
    END
  END nonce[107]
  PIN nonce[108]
    DIRECTION INPUT ;
    USE SIGNAL ;
    ANTENNAGATEAREA 0.213000 ;
    PORT
      LAYER met3 ;
        RECT 0.000 105.440 4.000 106.040 ;
    END
  END nonce[108]
  PIN nonce[109]
    DIRECTION INPUT ;
    USE SIGNAL ;
    ANTENNAGATEAREA 0.196500 ;
    PORT
      LAYER met3 ;
        RECT 0.000 17.040 4.000 17.640 ;
    END
  END nonce[109]
  PIN nonce[10]
    DIRECTION INPUT ;
    USE SIGNAL ;
    ANTENNAGATEAREA 0.196500 ;
    PORT
      LAYER met3 ;
        RECT 0.000 54.440 4.000 55.040 ;
    END
  END nonce[10]
  PIN nonce[110]
    DIRECTION INPUT ;
    USE SIGNAL ;
    ANTENNAGATEAREA 0.196500 ;
    PORT
      LAYER met3 ;
        RECT 0.000 74.840 4.000 75.440 ;
    END
  END nonce[110]
  PIN nonce[111]
    DIRECTION INPUT ;
    USE SIGNAL ;
    ANTENNAGATEAREA 0.196500 ;
    PORT
      LAYER met2 ;
        RECT 544.270 846.000 544.550 850.000 ;
    END
  END nonce[111]
  PIN nonce[112]
    DIRECTION INPUT ;
    USE SIGNAL ;
    ANTENNAGATEAREA 0.213000 ;
    PORT
      LAYER met3 ;
        RECT 0.000 27.240 4.000 27.840 ;
    END
  END nonce[112]
  PIN nonce[113]
    DIRECTION INPUT ;
    USE SIGNAL ;
    ANTENNAGATEAREA 0.426000 ;
    PORT
      LAYER met2 ;
        RECT 206.170 846.000 206.450 850.000 ;
    END
  END nonce[113]
  PIN nonce[114]
    DIRECTION INPUT ;
    USE SIGNAL ;
    ANTENNAGATEAREA 0.196500 ;
    PORT
      LAYER met2 ;
        RECT 644.090 846.000 644.370 850.000 ;
    END
  END nonce[114]
  PIN nonce[115]
    DIRECTION INPUT ;
    USE SIGNAL ;
    ANTENNAGATEAREA 0.196500 ;
    PORT
      LAYER met3 ;
        RECT 0.000 30.640 4.000 31.240 ;
    END
  END nonce[115]
  PIN nonce[116]
    DIRECTION INPUT ;
    USE SIGNAL ;
    ANTENNAGATEAREA 0.196500 ;
    PORT
      LAYER met3 ;
        RECT 0.000 40.840 4.000 41.440 ;
    END
  END nonce[116]
  PIN nonce[117]
    DIRECTION INPUT ;
    USE SIGNAL ;
    ANTENNAGATEAREA 0.196500 ;
    PORT
      LAYER met3 ;
        RECT 0.000 0.040 4.000 0.640 ;
    END
  END nonce[117]
  PIN nonce[118]
    DIRECTION INPUT ;
    USE SIGNAL ;
    ANTENNAGATEAREA 0.213000 ;
    PORT
      LAYER met3 ;
        RECT 0.000 98.640 4.000 99.240 ;
    END
  END nonce[118]
  PIN nonce[119]
    DIRECTION INPUT ;
    USE SIGNAL ;
    ANTENNAGATEAREA 0.196500 ;
    PORT
      LAYER met2 ;
        RECT 528.170 846.000 528.450 850.000 ;
    END
  END nonce[119]
  PIN nonce[11]
    DIRECTION INPUT ;
    USE SIGNAL ;
    ANTENNAGATEAREA 0.247500 ;
    PORT
      LAYER met3 ;
        RECT 0.000 129.240 4.000 129.840 ;
    END
  END nonce[11]
  PIN nonce[120]
    DIRECTION INPUT ;
    USE SIGNAL ;
    ANTENNAGATEAREA 0.196500 ;
    PORT
      LAYER met2 ;
        RECT 399.370 846.000 399.650 850.000 ;
    END
  END nonce[120]
  PIN nonce[121]
    DIRECTION INPUT ;
    USE SIGNAL ;
    ANTENNAGATEAREA 0.213000 ;
    PORT
      LAYER met3 ;
        RECT 0.000 132.640 4.000 133.240 ;
    END
  END nonce[121]
  PIN nonce[122]
    DIRECTION INPUT ;
    USE SIGNAL ;
    ANTENNAGATEAREA 0.247500 ;
    PORT
      LAYER met3 ;
        RECT 0.000 159.840 4.000 160.440 ;
    END
  END nonce[122]
  PIN nonce[123]
    DIRECTION INPUT ;
    USE SIGNAL ;
    ANTENNAGATEAREA 0.196500 ;
    PORT
      LAYER met2 ;
        RECT 505.630 846.000 505.910 850.000 ;
    END
  END nonce[123]
  PIN nonce[124]
    DIRECTION INPUT ;
    USE SIGNAL ;
    ANTENNAGATEAREA 0.196500 ;
    PORT
      LAYER met2 ;
        RECT 592.570 846.000 592.850 850.000 ;
    END
  END nonce[124]
  PIN nonce[125]
    DIRECTION INPUT ;
    USE SIGNAL ;
    ANTENNAGATEAREA 0.196500 ;
    PORT
      LAYER met2 ;
        RECT 473.430 846.000 473.710 850.000 ;
    END
  END nonce[125]
  PIN nonce[126]
    DIRECTION INPUT ;
    USE SIGNAL ;
    ANTENNAGATEAREA 0.213000 ;
    PORT
      LAYER met3 ;
        RECT 0.000 302.640 4.000 303.240 ;
    END
  END nonce[126]
  PIN nonce[127]
    DIRECTION INPUT ;
    USE SIGNAL ;
    ANTENNAGATEAREA 0.196500 ;
    PORT
      LAYER met3 ;
        RECT 0.000 44.240 4.000 44.840 ;
    END
  END nonce[127]
  PIN nonce[12]
    DIRECTION INPUT ;
    USE SIGNAL ;
    ANTENNAGATEAREA 0.213000 ;
    PORT
      LAYER met3 ;
        RECT 0.000 34.040 4.000 34.640 ;
    END
  END nonce[12]
  PIN nonce[13]
    DIRECTION INPUT ;
    USE SIGNAL ;
    ANTENNAGATEAREA 0.196500 ;
    PORT
      LAYER met3 ;
        RECT 0.000 122.440 4.000 123.040 ;
    END
  END nonce[13]
  PIN nonce[14]
    DIRECTION INPUT ;
    USE SIGNAL ;
    ANTENNAGATEAREA 0.196500 ;
    PORT
      LAYER met3 ;
        RECT 0.000 78.240 4.000 78.840 ;
    END
  END nonce[14]
  PIN nonce[15]
    DIRECTION INPUT ;
    USE SIGNAL ;
    ANTENNAGATEAREA 0.213000 ;
    PORT
      LAYER met3 ;
        RECT 0.000 146.240 4.000 146.840 ;
    END
  END nonce[15]
  PIN nonce[16]
    DIRECTION INPUT ;
    USE SIGNAL ;
    ANTENNAGATEAREA 0.196500 ;
    PORT
      LAYER met3 ;
        RECT 0.000 57.840 4.000 58.440 ;
    END
  END nonce[16]
  PIN nonce[17]
    DIRECTION INPUT ;
    USE SIGNAL ;
    ANTENNAGATEAREA 0.213000 ;
    PORT
      LAYER met3 ;
        RECT 0.000 51.040 4.000 51.640 ;
    END
  END nonce[17]
  PIN nonce[18]
    DIRECTION INPUT ;
    USE SIGNAL ;
    ANTENNAGATEAREA 0.196500 ;
    PORT
      LAYER met3 ;
        RECT 846.000 714.040 850.000 714.640 ;
    END
  END nonce[18]
  PIN nonce[19]
    DIRECTION INPUT ;
    USE SIGNAL ;
    ANTENNAGATEAREA 0.196500 ;
    PORT
      LAYER met3 ;
        RECT 0.000 23.840 4.000 24.440 ;
    END
  END nonce[19]
  PIN nonce[1]
    DIRECTION INPUT ;
    USE SIGNAL ;
    ANTENNAGATEAREA 0.196500 ;
    PORT
      LAYER met2 ;
        RECT 515.290 846.000 515.570 850.000 ;
    END
  END nonce[1]
  PIN nonce[20]
    DIRECTION INPUT ;
    USE SIGNAL ;
    ANTENNAGATEAREA 0.196500 ;
    PORT
      LAYER met3 ;
        RECT 0.000 115.640 4.000 116.240 ;
    END
  END nonce[20]
  PIN nonce[21]
    DIRECTION INPUT ;
    USE SIGNAL ;
    ANTENNAGATEAREA 0.196500 ;
    PORT
      LAYER met3 ;
        RECT 0.000 85.040 4.000 85.640 ;
    END
  END nonce[21]
  PIN nonce[22]
    DIRECTION INPUT ;
    USE SIGNAL ;
    ANTENNAGATEAREA 0.213000 ;
    PORT
      LAYER met3 ;
        RECT 0.000 64.640 4.000 65.240 ;
    END
  END nonce[22]
  PIN nonce[23]
    DIRECTION INPUT ;
    USE SIGNAL ;
    ANTENNAGATEAREA 0.196500 ;
    PORT
      LAYER met2 ;
        RECT 537.830 846.000 538.110 850.000 ;
    END
  END nonce[23]
  PIN nonce[24]
    DIRECTION INPUT ;
    USE SIGNAL ;
    ANTENNAGATEAREA 0.196500 ;
    PORT
      LAYER met3 ;
        RECT 0.000 68.040 4.000 68.640 ;
    END
  END nonce[24]
  PIN nonce[25]
    DIRECTION INPUT ;
    USE SIGNAL ;
    ANTENNAGATEAREA 0.213000 ;
    PORT
      LAYER met3 ;
        RECT 0.000 37.440 4.000 38.040 ;
    END
  END nonce[25]
  PIN nonce[26]
    DIRECTION INPUT ;
    USE SIGNAL ;
    ANTENNAGATEAREA 0.426000 ;
    PORT
      LAYER met3 ;
        RECT 0.000 166.640 4.000 167.240 ;
    END
  END nonce[26]
  PIN nonce[27]
    DIRECTION INPUT ;
    USE SIGNAL ;
    ANTENNAGATEAREA 0.196500 ;
    PORT
      LAYER met2 ;
        RECT 512.070 846.000 512.350 850.000 ;
    END
  END nonce[27]
  PIN nonce[28]
    DIRECTION INPUT ;
    USE SIGNAL ;
    ANTENNAGATEAREA 0.196500 ;
    PORT
      LAYER met2 ;
        RECT 640.870 846.000 641.150 850.000 ;
    END
  END nonce[28]
  PIN nonce[29]
    DIRECTION INPUT ;
    USE SIGNAL ;
    ANTENNAGATEAREA 0.196500 ;
    PORT
      LAYER met2 ;
        RECT 315.650 846.000 315.930 850.000 ;
    END
  END nonce[29]
  PIN nonce[2]
    DIRECTION INPUT ;
    USE SIGNAL ;
    ANTENNAGATEAREA 0.196500 ;
    PORT
      LAYER met3 ;
        RECT 0.000 71.440 4.000 72.040 ;
    END
  END nonce[2]
  PIN nonce[30]
    DIRECTION INPUT ;
    USE SIGNAL ;
    ANTENNAGATEAREA 0.196500 ;
    PORT
      LAYER met3 ;
        RECT 0.000 91.840 4.000 92.440 ;
    END
  END nonce[30]
  PIN nonce[31]
    DIRECTION INPUT ;
    USE SIGNAL ;
    ANTENNAGATEAREA 0.196500 ;
    PORT
      LAYER met3 ;
        RECT 0.000 156.440 4.000 157.040 ;
    END
  END nonce[31]
  PIN nonce[32]
    DIRECTION INPUT ;
    USE SIGNAL ;
    ANTENNAGATEAREA 0.196500 ;
    PORT
      LAYER met2 ;
        RECT 296.330 846.000 296.610 850.000 ;
    END
  END nonce[32]
  PIN nonce[33]
    DIRECTION INPUT ;
    USE SIGNAL ;
    ANTENNAGATEAREA 0.495000 ;
    PORT
      LAYER met3 ;
        RECT 0.000 136.040 4.000 136.640 ;
    END
  END nonce[33]
  PIN nonce[34]
    DIRECTION INPUT ;
    USE SIGNAL ;
    ANTENNAGATEAREA 0.196500 ;
    PORT
      LAYER met3 ;
        RECT 0.000 61.240 4.000 61.840 ;
    END
  END nonce[34]
  PIN nonce[35]
    DIRECTION INPUT ;
    USE SIGNAL ;
    ANTENNAGATEAREA 0.495000 ;
    PORT
      LAYER met3 ;
        RECT 0.000 153.040 4.000 153.640 ;
    END
  END nonce[35]
  PIN nonce[36]
    DIRECTION INPUT ;
    USE SIGNAL ;
    ANTENNAGATEAREA 0.196500 ;
    PORT
      LAYER met2 ;
        RECT 357.510 846.000 357.790 850.000 ;
    END
  END nonce[36]
  PIN nonce[37]
    DIRECTION INPUT ;
    USE SIGNAL ;
    ANTENNAGATEAREA 0.213000 ;
    PORT
      LAYER met3 ;
        RECT 0.000 95.240 4.000 95.840 ;
    END
  END nonce[37]
  PIN nonce[38]
    DIRECTION INPUT ;
    USE SIGNAL ;
    ANTENNAGATEAREA 0.247500 ;
    PORT
      LAYER met3 ;
        RECT 0.000 3.440 4.000 4.040 ;
    END
  END nonce[38]
  PIN nonce[39]
    DIRECTION INPUT ;
    USE SIGNAL ;
    ANTENNAGATEAREA 0.247500 ;
    PORT
      LAYER met3 ;
        RECT 0.000 163.240 4.000 163.840 ;
    END
  END nonce[39]
  PIN nonce[3]
    DIRECTION INPUT ;
    USE SIGNAL ;
    ANTENNAGATEAREA 0.196500 ;
    PORT
      LAYER met2 ;
        RECT 495.970 846.000 496.250 850.000 ;
    END
  END nonce[3]
  PIN nonce[40]
    DIRECTION INPUT ;
    USE SIGNAL ;
    ANTENNAGATEAREA 0.213000 ;
    PORT
      LAYER met3 ;
        RECT 0.000 112.240 4.000 112.840 ;
    END
  END nonce[40]
  PIN nonce[41]
    DIRECTION INPUT ;
    USE SIGNAL ;
    ANTENNAGATEAREA 0.247500 ;
    PORT
      LAYER met3 ;
        RECT 0.000 149.640 4.000 150.240 ;
    END
  END nonce[41]
  PIN nonce[42]
    DIRECTION INPUT ;
    USE SIGNAL ;
    ANTENNAGATEAREA 0.196500 ;
    PORT
      LAYER met3 ;
        RECT 0.000 88.440 4.000 89.040 ;
    END
  END nonce[42]
  PIN nonce[43]
    DIRECTION INPUT ;
    USE SIGNAL ;
    ANTENNAGATEAREA 0.247500 ;
    PORT
      LAYER met3 ;
        RECT 0.000 119.040 4.000 119.640 ;
    END
  END nonce[43]
  PIN nonce[44]
    DIRECTION INPUT ;
    USE SIGNAL ;
    ANTENNAGATEAREA 0.213000 ;
    PORT
      LAYER met3 ;
        RECT 0.000 47.640 4.000 48.240 ;
    END
  END nonce[44]
  PIN nonce[45]
    DIRECTION INPUT ;
    USE SIGNAL ;
    ANTENNAGATEAREA 0.247500 ;
    PORT
      LAYER met3 ;
        RECT 0.000 13.640 4.000 14.240 ;
    END
  END nonce[45]
  PIN nonce[46]
    DIRECTION INPUT ;
    USE SIGNAL ;
    ANTENNAGATEAREA 0.159000 ;
    PORT
      LAYER met3 ;
        RECT 0.000 81.640 4.000 82.240 ;
    END
  END nonce[46]
  PIN nonce[47]
    DIRECTION INPUT ;
    USE SIGNAL ;
    ANTENNAGATEAREA 0.213000 ;
    PORT
      LAYER met3 ;
        RECT 0.000 142.840 4.000 143.440 ;
    END
  END nonce[47]
  PIN nonce[48]
    DIRECTION INPUT ;
    USE SIGNAL ;
    ANTENNAGATEAREA 0.196500 ;
    PORT
      LAYER met3 ;
        RECT 0.000 217.640 4.000 218.240 ;
    END
  END nonce[48]
  PIN nonce[49]
    DIRECTION INPUT ;
    USE SIGNAL ;
    ANTENNAGATEAREA 0.247500 ;
    PORT
      LAYER met2 ;
        RECT 563.590 846.000 563.870 850.000 ;
    END
  END nonce[49]
  PIN nonce[4]
    DIRECTION INPUT ;
    USE SIGNAL ;
    ANTENNAGATEAREA 0.196500 ;
    PORT
      LAYER met2 ;
        RECT 367.170 846.000 367.450 850.000 ;
    END
  END nonce[4]
  PIN nonce[50]
    DIRECTION INPUT ;
    USE SIGNAL ;
    ANTENNAGATEAREA 0.196500 ;
    PORT
      LAYER met3 ;
        RECT 846.000 683.440 850.000 684.040 ;
    END
  END nonce[50]
  PIN nonce[51]
    DIRECTION INPUT ;
    USE SIGNAL ;
    ANTENNAGATEAREA 0.247500 ;
    PORT
      LAYER met2 ;
        RECT 293.110 846.000 293.390 850.000 ;
    END
  END nonce[51]
  PIN nonce[52]
    DIRECTION INPUT ;
    USE SIGNAL ;
    ANTENNAGATEAREA 0.247500 ;
    PORT
      LAYER met2 ;
        RECT 277.010 846.000 277.290 850.000 ;
    END
  END nonce[52]
  PIN nonce[53]
    DIRECTION INPUT ;
    USE SIGNAL ;
    ANTENNAGATEAREA 0.247500 ;
    PORT
      LAYER met2 ;
        RECT 354.290 846.000 354.570 850.000 ;
    END
  END nonce[53]
  PIN nonce[54]
    DIRECTION INPUT ;
    USE SIGNAL ;
    ANTENNAGATEAREA 0.247500 ;
    PORT
      LAYER met2 ;
        RECT 524.950 846.000 525.230 850.000 ;
    END
  END nonce[54]
  PIN nonce[55]
    DIRECTION INPUT ;
    USE SIGNAL ;
    ANTENNAGATEAREA 0.196500 ;
    PORT
      LAYER met2 ;
        RECT 415.470 846.000 415.750 850.000 ;
    END
  END nonce[55]
  PIN nonce[56]
    DIRECTION INPUT ;
    USE SIGNAL ;
    ANTENNAGATEAREA 0.196500 ;
    PORT
      LAYER met3 ;
        RECT 0.000 180.240 4.000 180.840 ;
    END
  END nonce[56]
  PIN nonce[57]
    DIRECTION INPUT ;
    USE SIGNAL ;
    ANTENNAGATEAREA 0.426000 ;
    PORT
      LAYER met2 ;
        RECT 476.650 846.000 476.930 850.000 ;
    END
  END nonce[57]
  PIN nonce[58]
    DIRECTION INPUT ;
    USE SIGNAL ;
    ANTENNAGATEAREA 0.213000 ;
    PORT
      LAYER met3 ;
        RECT 846.000 680.040 850.000 680.640 ;
    END
  END nonce[58]
  PIN nonce[59]
    DIRECTION INPUT ;
    USE SIGNAL ;
    ANTENNAGATEAREA 0.196500 ;
    PORT
      LAYER met2 ;
        RECT 338.190 846.000 338.470 850.000 ;
    END
  END nonce[59]
  PIN nonce[5]
    DIRECTION INPUT ;
    USE SIGNAL ;
    ANTENNAGATEAREA 0.247500 ;
    PORT
      LAYER met2 ;
        RECT 418.690 846.000 418.970 850.000 ;
    END
  END nonce[5]
  PIN nonce[60]
    DIRECTION INPUT ;
    USE SIGNAL ;
    ANTENNAGATEAREA 0.159000 ;
    PORT
      LAYER met3 ;
        RECT 846.000 829.640 850.000 830.240 ;
    END
  END nonce[60]
  PIN nonce[61]
    DIRECTION INPUT ;
    USE SIGNAL ;
    ANTENNAGATEAREA 0.196500 ;
    PORT
      LAYER met2 ;
        RECT 376.830 846.000 377.110 850.000 ;
    END
  END nonce[61]
  PIN nonce[62]
    DIRECTION INPUT ;
    USE SIGNAL ;
    ANTENNAGATEAREA 0.196500 ;
    PORT
      LAYER met3 ;
        RECT 0.000 170.040 4.000 170.640 ;
    END
  END nonce[62]
  PIN nonce[63]
    DIRECTION INPUT ;
    USE SIGNAL ;
    ANTENNAGATEAREA 0.196500 ;
    PORT
      LAYER met2 ;
        RECT 444.450 846.000 444.730 850.000 ;
    END
  END nonce[63]
  PIN nonce[64]
    DIRECTION INPUT ;
    USE SIGNAL ;
    ANTENNAGATEAREA 0.196500 ;
    PORT
      LAYER met2 ;
        RECT 222.270 846.000 222.550 850.000 ;
    END
  END nonce[64]
  PIN nonce[65]
    DIRECTION INPUT ;
    USE SIGNAL ;
    ANTENNAGATEAREA 0.196500 ;
    PORT
      LAYER met2 ;
        RECT 492.750 846.000 493.030 850.000 ;
    END
  END nonce[65]
  PIN nonce[66]
    DIRECTION INPUT ;
    USE SIGNAL ;
    ANTENNAGATEAREA 0.196500 ;
    PORT
      LAYER met3 ;
        RECT 0.000 204.040 4.000 204.640 ;
    END
  END nonce[66]
  PIN nonce[67]
    DIRECTION INPUT ;
    USE SIGNAL ;
    ANTENNAGATEAREA 0.196500 ;
    PORT
      LAYER met2 ;
        RECT 421.910 846.000 422.190 850.000 ;
    END
  END nonce[67]
  PIN nonce[68]
    DIRECTION INPUT ;
    USE SIGNAL ;
    ANTENNAGATEAREA 0.196500 ;
    PORT
      LAYER met2 ;
        RECT 286.670 846.000 286.950 850.000 ;
    END
  END nonce[68]
  PIN nonce[69]
    DIRECTION INPUT ;
    USE SIGNAL ;
    ANTENNAGATEAREA 0.247500 ;
    PORT
      LAYER met2 ;
        RECT 470.210 846.000 470.490 850.000 ;
    END
  END nonce[69]
  PIN nonce[6]
    DIRECTION INPUT ;
    USE SIGNAL ;
    ANTENNAGATEAREA 0.247500 ;
    PORT
      LAYER met2 ;
        RECT 624.770 846.000 625.050 850.000 ;
    END
  END nonce[6]
  PIN nonce[70]
    DIRECTION INPUT ;
    USE SIGNAL ;
    ANTENNAGATEAREA 0.426000 ;
    PORT
      LAYER met3 ;
        RECT 846.000 703.840 850.000 704.440 ;
    END
  END nonce[70]
  PIN nonce[71]
    DIRECTION INPUT ;
    USE SIGNAL ;
    ANTENNAGATEAREA 0.247500 ;
    PORT
      LAYER met2 ;
        RECT 605.450 846.000 605.730 850.000 ;
    END
  END nonce[71]
  PIN nonce[72]
    DIRECTION INPUT ;
    USE SIGNAL ;
    ANTENNAGATEAREA 0.247500 ;
    PORT
      LAYER met2 ;
        RECT 486.310 846.000 486.590 850.000 ;
    END
  END nonce[72]
  PIN nonce[73]
    DIRECTION INPUT ;
    USE SIGNAL ;
    ANTENNAGATEAREA 0.247500 ;
    PORT
      LAYER met2 ;
        RECT 579.690 846.000 579.970 850.000 ;
    END
  END nonce[73]
  PIN nonce[74]
    DIRECTION INPUT ;
    USE SIGNAL ;
    ANTENNAGATEAREA 0.196500 ;
    PORT
      LAYER met3 ;
        RECT 0.000 183.640 4.000 184.240 ;
    END
  END nonce[74]
  PIN nonce[75]
    DIRECTION INPUT ;
    USE SIGNAL ;
    ANTENNAGATEAREA 0.247500 ;
    PORT
      LAYER met2 ;
        RECT 599.010 846.000 599.290 850.000 ;
    END
  END nonce[75]
  PIN nonce[76]
    DIRECTION INPUT ;
    USE SIGNAL ;
    ANTENNAGATEAREA 0.247500 ;
    PORT
      LAYER met2 ;
        RECT 441.230 846.000 441.510 850.000 ;
    END
  END nonce[76]
  PIN nonce[77]
    DIRECTION INPUT ;
    USE SIGNAL ;
    ANTENNAGATEAREA 0.247500 ;
    PORT
      LAYER met2 ;
        RECT 521.730 846.000 522.010 850.000 ;
    END
  END nonce[77]
  PIN nonce[78]
    DIRECTION INPUT ;
    USE SIGNAL ;
    ANTENNAGATEAREA 0.426000 ;
    PORT
      LAYER met2 ;
        RECT 431.570 846.000 431.850 850.000 ;
    END
  END nonce[78]
  PIN nonce[79]
    DIRECTION INPUT ;
    USE SIGNAL ;
    ANTENNAGATEAREA 0.196500 ;
    PORT
      LAYER met2 ;
        RECT 534.610 846.000 534.890 850.000 ;
    END
  END nonce[79]
  PIN nonce[7]
    DIRECTION INPUT ;
    USE SIGNAL ;
    ANTENNAGATEAREA 0.247500 ;
    PORT
      LAYER met2 ;
        RECT 557.150 846.000 557.430 850.000 ;
    END
  END nonce[7]
  PIN nonce[80]
    DIRECTION INPUT ;
    USE SIGNAL ;
    ANTENNAGATEAREA 0.196500 ;
    PORT
      LAYER met3 ;
        RECT 0.000 221.040 4.000 221.640 ;
    END
  END nonce[80]
  PIN nonce[81]
    DIRECTION INPUT ;
    USE SIGNAL ;
    ANTENNAGATEAREA 0.247500 ;
    PORT
      LAYER met2 ;
        RECT 518.510 846.000 518.790 850.000 ;
    END
  END nonce[81]
  PIN nonce[82]
    DIRECTION INPUT ;
    USE SIGNAL ;
    ANTENNAGATEAREA 0.196500 ;
    PORT
      LAYER met3 ;
        RECT 846.000 707.240 850.000 707.840 ;
    END
  END nonce[82]
  PIN nonce[83]
    DIRECTION INPUT ;
    USE SIGNAL ;
    ANTENNAGATEAREA 0.247500 ;
    PORT
      LAYER met2 ;
        RECT 283.450 846.000 283.730 850.000 ;
    END
  END nonce[83]
  PIN nonce[84]
    DIRECTION INPUT ;
    USE SIGNAL ;
    ANTENNAGATEAREA 0.247500 ;
    PORT
      LAYER met2 ;
        RECT 373.610 846.000 373.890 850.000 ;
    END
  END nonce[84]
  PIN nonce[85]
    DIRECTION INPUT ;
    USE SIGNAL ;
    ANTENNAGATEAREA 0.426000 ;
    PORT
      LAYER met2 ;
        RECT 434.790 846.000 435.070 850.000 ;
    END
  END nonce[85]
  PIN nonce[86]
    DIRECTION INPUT ;
    USE SIGNAL ;
    ANTENNAGATEAREA 0.247500 ;
    PORT
      LAYER met2 ;
        RECT 508.850 846.000 509.130 850.000 ;
    END
  END nonce[86]
  PIN nonce[87]
    DIRECTION INPUT ;
    USE SIGNAL ;
    ANTENNAGATEAREA 0.126000 ;
    PORT
      LAYER met2 ;
        RECT 341.410 846.000 341.690 850.000 ;
    END
  END nonce[87]
  PIN nonce[88]
    DIRECTION INPUT ;
    USE SIGNAL ;
    ANTENNAGATEAREA 0.196500 ;
    PORT
      LAYER met3 ;
        RECT 0.000 173.440 4.000 174.040 ;
    END
  END nonce[88]
  PIN nonce[89]
    DIRECTION INPUT ;
    USE SIGNAL ;
    ANTENNAGATEAREA 0.247500 ;
    PORT
      LAYER met2 ;
        RECT 235.150 846.000 235.430 850.000 ;
    END
  END nonce[89]
  PIN nonce[8]
    DIRECTION INPUT ;
    USE SIGNAL ;
    ANTENNAGATEAREA 0.247500 ;
    PORT
      LAYER met2 ;
        RECT 289.890 846.000 290.170 850.000 ;
    END
  END nonce[8]
  PIN nonce[90]
    DIRECTION INPUT ;
    USE SIGNAL ;
    ANTENNAGATEAREA 0.247500 ;
    PORT
      LAYER met3 ;
        RECT 846.000 737.840 850.000 738.440 ;
    END
  END nonce[90]
  PIN nonce[91]
    DIRECTION INPUT ;
    USE SIGNAL ;
    ANTENNAGATEAREA 0.196500 ;
    PORT
      LAYER met2 ;
        RECT 386.490 846.000 386.770 850.000 ;
    END
  END nonce[91]
  PIN nonce[92]
    DIRECTION INPUT ;
    USE SIGNAL ;
    ANTENNAGATEAREA 0.196500 ;
    PORT
      LAYER met2 ;
        RECT 647.310 846.000 647.590 850.000 ;
    END
  END nonce[92]
  PIN nonce[93]
    DIRECTION INPUT ;
    USE SIGNAL ;
    ANTENNAGATEAREA 0.196500 ;
    PORT
      LAYER met2 ;
        RECT 438.010 846.000 438.290 850.000 ;
    END
  END nonce[93]
  PIN nonce[94]
    DIRECTION INPUT ;
    USE SIGNAL ;
    ANTENNAGATEAREA 0.196500 ;
    PORT
      LAYER met3 ;
        RECT 0.000 176.840 4.000 177.440 ;
    END
  END nonce[94]
  PIN nonce[95]
    DIRECTION INPUT ;
    USE SIGNAL ;
    ANTENNAGATEAREA 0.196500 ;
    PORT
      LAYER met2 ;
        RECT 447.670 846.000 447.950 850.000 ;
    END
  END nonce[95]
  PIN nonce[96]
    DIRECTION INPUT ;
    USE SIGNAL ;
    ANTENNAGATEAREA 0.196500 ;
    PORT
      LAYER met2 ;
        RECT 302.770 846.000 303.050 850.000 ;
    END
  END nonce[96]
  PIN nonce[97]
    DIRECTION INPUT ;
    USE SIGNAL ;
    ANTENNAGATEAREA 0.126000 ;
    PORT
      LAYER met2 ;
        RECT 225.490 846.000 225.770 850.000 ;
    END
  END nonce[97]
  PIN nonce[98]
    DIRECTION INPUT ;
    USE SIGNAL ;
    ANTENNAGATEAREA 0.213000 ;
    PORT
      LAYER met3 ;
        RECT 0.000 295.840 4.000 296.440 ;
    END
  END nonce[98]
  PIN nonce[99]
    DIRECTION INPUT ;
    USE SIGNAL ;
    ANTENNAGATEAREA 0.196500 ;
    PORT
      LAYER met2 ;
        RECT 270.570 846.000 270.850 850.000 ;
    END
  END nonce[99]
  PIN nonce[9]
    DIRECTION INPUT ;
    USE SIGNAL ;
    ANTENNAGATEAREA 0.247500 ;
    PORT
      LAYER met2 ;
        RECT 573.250 846.000 573.530 850.000 ;
    END
  END nonce[9]
  PIN restart
    DIRECTION INPUT ;
    USE SIGNAL ;
    ANTENNAGATEAREA 0.196500 ;
    PORT
      LAYER met2 ;
        RECT 344.630 846.000 344.910 850.000 ;
    END
  END restart
  PIN rst_n
    DIRECTION INPUT ;
    USE SIGNAL ;
    ANTENNAGATEAREA 0.196500 ;
    PORT
      LAYER met2 ;
        RECT 370.390 846.000 370.670 850.000 ;
    END
  END rst_n
  PIN sel_type[0]
    DIRECTION INPUT ;
    USE SIGNAL ;
    ANTENNAGATEAREA 0.213000 ;
    PORT
      LAYER met2 ;
        RECT 483.090 846.000 483.370 850.000 ;
    END
  END sel_type[0]
  PIN sel_type[1]
    DIRECTION INPUT ;
    USE SIGNAL ;
    ANTENNAGATEAREA 0.213000 ;
    PORT
      LAYER met2 ;
        RECT 428.350 846.000 428.630 850.000 ;
    END
  END sel_type[1]
  PIN tag[0]
    DIRECTION OUTPUT ;
    USE SIGNAL ;
    ANTENNADIFFAREA 0.445500 ;
    PORT
      LAYER met3 ;
        RECT 846.000 833.040 850.000 833.640 ;
    END
  END tag[0]
  PIN tag[100]
    DIRECTION OUTPUT ;
    USE SIGNAL ;
    ANTENNADIFFAREA 0.445500 ;
    PORT
      LAYER met3 ;
        RECT 846.000 761.640 850.000 762.240 ;
    END
  END tag[100]
  PIN tag[101]
    DIRECTION OUTPUT ;
    USE SIGNAL ;
    ANTENNADIFFAREA 0.445500 ;
    PORT
      LAYER met2 ;
        RECT 589.350 846.000 589.630 850.000 ;
    END
  END tag[101]
  PIN tag[102]
    DIRECTION OUTPUT ;
    USE SIGNAL ;
    ANTENNADIFFAREA 0.445500 ;
    PORT
      LAYER met3 ;
        RECT 846.000 765.040 850.000 765.640 ;
    END
  END tag[102]
  PIN tag[103]
    DIRECTION OUTPUT ;
    USE SIGNAL ;
    ANTENNADIFFAREA 0.445500 ;
    PORT
      LAYER met3 ;
        RECT 846.000 778.640 850.000 779.240 ;
    END
  END tag[103]
  PIN tag[104]
    DIRECTION OUTPUT ;
    USE SIGNAL ;
    ANTENNADIFFAREA 0.445500 ;
    PORT
      LAYER met2 ;
        RECT 637.650 846.000 637.930 850.000 ;
    END
  END tag[104]
  PIN tag[105]
    DIRECTION OUTPUT ;
    USE SIGNAL ;
    ANTENNADIFFAREA 0.445500 ;
    PORT
      LAYER met3 ;
        RECT 846.000 843.240 850.000 843.840 ;
    END
  END tag[105]
  PIN tag[106]
    DIRECTION OUTPUT ;
    USE SIGNAL ;
    ANTENNADIFFAREA 0.445500 ;
    PORT
      LAYER met3 ;
        RECT 846.000 751.440 850.000 752.040 ;
    END
  END tag[106]
  PIN tag[107]
    DIRECTION OUTPUT ;
    USE SIGNAL ;
    ANTENNADIFFAREA 0.445500 ;
    PORT
      LAYER met3 ;
        RECT 846.000 768.440 850.000 769.040 ;
    END
  END tag[107]
  PIN tag[108]
    DIRECTION OUTPUT ;
    USE SIGNAL ;
    ANTENNADIFFAREA 0.445500 ;
    PORT
      LAYER met2 ;
        RECT 479.870 846.000 480.150 850.000 ;
    END
  END tag[108]
  PIN tag[109]
    DIRECTION OUTPUT ;
    USE SIGNAL ;
    ANTENNADIFFAREA 0.445500 ;
    PORT
      LAYER met3 ;
        RECT 846.000 788.840 850.000 789.440 ;
    END
  END tag[109]
  PIN tag[10]
    DIRECTION OUTPUT ;
    USE SIGNAL ;
    ANTENNADIFFAREA 0.445500 ;
    PORT
      LAYER met3 ;
        RECT 846.000 792.240 850.000 792.840 ;
    END
  END tag[10]
  PIN tag[110]
    DIRECTION OUTPUT ;
    USE SIGNAL ;
    ANTENNADIFFAREA 0.445500 ;
    PORT
      LAYER met3 ;
        RECT 846.000 785.440 850.000 786.040 ;
    END
  END tag[110]
  PIN tag[111]
    DIRECTION OUTPUT ;
    USE SIGNAL ;
    ANTENNADIFFAREA 0.445500 ;
    PORT
      LAYER met2 ;
        RECT 502.410 846.000 502.690 850.000 ;
    END
  END tag[111]
  PIN tag[112]
    DIRECTION OUTPUT ;
    USE SIGNAL ;
    ANTENNADIFFAREA 0.445500 ;
    PORT
      LAYER met3 ;
        RECT 846.000 799.040 850.000 799.640 ;
    END
  END tag[112]
  PIN tag[113]
    DIRECTION OUTPUT ;
    USE SIGNAL ;
    ANTENNADIFFAREA 0.445500 ;
    PORT
      LAYER met3 ;
        RECT 846.000 727.640 850.000 728.240 ;
    END
  END tag[113]
  PIN tag[114]
    DIRECTION OUTPUT ;
    USE SIGNAL ;
    ANTENNADIFFAREA 0.445500 ;
    PORT
      LAYER met3 ;
        RECT 846.000 802.440 850.000 803.040 ;
    END
  END tag[114]
  PIN tag[115]
    DIRECTION OUTPUT ;
    USE SIGNAL ;
    ANTENNADIFFAREA 0.445500 ;
    PORT
      LAYER met3 ;
        RECT 846.000 836.440 850.000 837.040 ;
    END
  END tag[115]
  PIN tag[116]
    DIRECTION OUTPUT ;
    USE SIGNAL ;
    ANTENNADIFFAREA 0.445500 ;
    PORT
      LAYER met2 ;
        RECT 334.970 846.000 335.250 850.000 ;
    END
  END tag[116]
  PIN tag[117]
    DIRECTION OUTPUT ;
    USE SIGNAL ;
    ANTENNADIFFAREA 0.445500 ;
    PORT
      LAYER met3 ;
        RECT 846.000 734.440 850.000 735.040 ;
    END
  END tag[117]
  PIN tag[118]
    DIRECTION OUTPUT ;
    USE SIGNAL ;
    ANTENNADIFFAREA 0.445500 ;
    PORT
      LAYER met2 ;
        RECT 608.670 846.000 608.950 850.000 ;
    END
  END tag[118]
  PIN tag[119]
    DIRECTION OUTPUT ;
    USE SIGNAL ;
    ANTENNADIFFAREA 0.445500 ;
    PORT
      LAYER met3 ;
        RECT 846.000 710.640 850.000 711.240 ;
    END
  END tag[119]
  PIN tag[11]
    DIRECTION OUTPUT ;
    USE SIGNAL ;
    ANTENNADIFFAREA 0.445500 ;
    PORT
      LAYER met3 ;
        RECT 846.000 700.440 850.000 701.040 ;
    END
  END tag[11]
  PIN tag[120]
    DIRECTION OUTPUT ;
    USE SIGNAL ;
    ANTENNADIFFAREA 0.445500 ;
    PORT
      LAYER met2 ;
        RECT 312.430 846.000 312.710 850.000 ;
    END
  END tag[120]
  PIN tag[121]
    DIRECTION OUTPUT ;
    USE SIGNAL ;
    ANTENNADIFFAREA 0.445500 ;
    PORT
      LAYER met2 ;
        RECT 653.750 846.000 654.030 850.000 ;
    END
  END tag[121]
  PIN tag[122]
    DIRECTION OUTPUT ;
    USE SIGNAL ;
    ANTENNADIFFAREA 0.445500 ;
    PORT
      LAYER met2 ;
        RECT 621.550 846.000 621.830 850.000 ;
    END
  END tag[122]
  PIN tag[123]
    DIRECTION OUTPUT ;
    USE SIGNAL ;
    ANTENNADIFFAREA 0.445500 ;
    PORT
      LAYER met2 ;
        RECT 663.410 846.000 663.690 850.000 ;
    END
  END tag[123]
  PIN tag[124]
    DIRECTION OUTPUT ;
    USE SIGNAL ;
    ANTENNADIFFAREA 0.445500 ;
    PORT
      LAYER met2 ;
        RECT 817.970 846.000 818.250 850.000 ;
    END
  END tag[124]
  PIN tag[125]
    DIRECTION OUTPUT ;
    USE SIGNAL ;
    ANTENNADIFFAREA 0.445500 ;
    PORT
      LAYER met2 ;
        RECT 763.230 846.000 763.510 850.000 ;
    END
  END tag[125]
  PIN tag[126]
    DIRECTION OUTPUT ;
    USE SIGNAL ;
    ANTENNADIFFAREA 0.445500 ;
    PORT
      LAYER met2 ;
        RECT 360.730 846.000 361.010 850.000 ;
    END
  END tag[126]
  PIN tag[127]
    DIRECTION OUTPUT ;
    USE SIGNAL ;
    ANTENNADIFFAREA 0.445500 ;
    PORT
      LAYER met2 ;
        RECT 602.230 846.000 602.510 850.000 ;
    END
  END tag[127]
  PIN tag[12]
    DIRECTION OUTPUT ;
    USE SIGNAL ;
    ANTENNADIFFAREA 0.445500 ;
    PORT
      LAYER met2 ;
        RECT 212.610 846.000 212.890 850.000 ;
    END
  END tag[12]
  PIN tag[13]
    DIRECTION OUTPUT ;
    USE SIGNAL ;
    ANTENNADIFFAREA 0.445500 ;
    PORT
      LAYER met2 ;
        RECT 702.050 846.000 702.330 850.000 ;
    END
  END tag[13]
  PIN tag[14]
    DIRECTION OUTPUT ;
    USE SIGNAL ;
    ANTENNADIFFAREA 0.445500 ;
    PORT
      LAYER met2 ;
        RECT 782.550 846.000 782.830 850.000 ;
    END
  END tag[14]
  PIN tag[15]
    DIRECTION OUTPUT ;
    USE SIGNAL ;
    ANTENNADIFFAREA 0.445500 ;
    PORT
      LAYER met2 ;
        RECT 215.830 846.000 216.110 850.000 ;
    END
  END tag[15]
  PIN tag[16]
    DIRECTION OUTPUT ;
    USE SIGNAL ;
    ANTENNADIFFAREA 0.445500 ;
    PORT
      LAYER met2 ;
        RECT 840.510 846.000 840.790 850.000 ;
    END
  END tag[16]
  PIN tag[17]
    DIRECTION OUTPUT ;
    USE SIGNAL ;
    ANTENNADIFFAREA 0.445500 ;
    PORT
      LAYER met2 ;
        RECT 792.210 846.000 792.490 850.000 ;
    END
  END tag[17]
  PIN tag[18]
    DIRECTION OUTPUT ;
    USE SIGNAL ;
    ANTENNADIFFAREA 0.445500 ;
    PORT
      LAYER met2 ;
        RECT 834.070 846.000 834.350 850.000 ;
    END
  END tag[18]
  PIN tag[19]
    DIRECTION OUTPUT ;
    USE SIGNAL ;
    ANTENNADIFFAREA 0.445500 ;
    PORT
      LAYER met2 ;
        RECT 692.390 846.000 692.670 850.000 ;
    END
  END tag[19]
  PIN tag[1]
    DIRECTION OUTPUT ;
    USE SIGNAL ;
    ANTENNADIFFAREA 0.445500 ;
    PORT
      LAYER met2 ;
        RECT 380.050 846.000 380.330 850.000 ;
    END
  END tag[1]
  PIN tag[20]
    DIRECTION OUTPUT ;
    USE SIGNAL ;
    ANTENNADIFFAREA 0.445500 ;
    PORT
      LAYER met2 ;
        RECT 299.550 846.000 299.830 850.000 ;
    END
  END tag[20]
  PIN tag[21]
    DIRECTION OUTPUT ;
    USE SIGNAL ;
    ANTENNADIFFAREA 0.445500 ;
    PORT
      LAYER met2 ;
        RECT 750.350 846.000 750.630 850.000 ;
    END
  END tag[21]
  PIN tag[22]
    DIRECTION OUTPUT ;
    USE SIGNAL ;
    ANTENNADIFFAREA 0.445500 ;
    PORT
      LAYER met2 ;
        RECT 531.390 846.000 531.670 850.000 ;
    END
  END tag[22]
  PIN tag[23]
    DIRECTION OUTPUT ;
    USE SIGNAL ;
    ANTENNADIFFAREA 0.445500 ;
    PORT
      LAYER met2 ;
        RECT 689.170 846.000 689.450 850.000 ;
    END
  END tag[23]
  PIN tag[24]
    DIRECTION OUTPUT ;
    USE SIGNAL ;
    ANTENNADIFFAREA 0.445500 ;
    PORT
      LAYER met2 ;
        RECT 389.710 846.000 389.990 850.000 ;
    END
  END tag[24]
  PIN tag[25]
    DIRECTION OUTPUT ;
    USE SIGNAL ;
    ANTENNADIFFAREA 0.445500 ;
    PORT
      LAYER met2 ;
        RECT 656.970 846.000 657.250 850.000 ;
    END
  END tag[25]
  PIN tag[26]
    DIRECTION OUTPUT ;
    USE SIGNAL ;
    ANTENNADIFFAREA 0.445500 ;
    PORT
      LAYER met2 ;
        RECT 618.330 846.000 618.610 850.000 ;
    END
  END tag[26]
  PIN tag[27]
    DIRECTION OUTPUT ;
    USE SIGNAL ;
    ANTENNADIFFAREA 0.445500 ;
    PORT
      LAYER met2 ;
        RECT 718.150 846.000 718.430 850.000 ;
    END
  END tag[27]
  PIN tag[28]
    DIRECTION OUTPUT ;
    USE SIGNAL ;
    ANTENNADIFFAREA 0.445500 ;
    PORT
      LAYER met2 ;
        RECT 743.910 846.000 744.190 850.000 ;
    END
  END tag[28]
  PIN tag[29]
    DIRECTION OUTPUT ;
    USE SIGNAL ;
    ANTENNADIFFAREA 0.445500 ;
    PORT
      LAYER met2 ;
        RECT 772.890 846.000 773.170 850.000 ;
    END
  END tag[29]
  PIN tag[2]
    DIRECTION OUTPUT ;
    USE SIGNAL ;
    ANTENNADIFFAREA 0.445500 ;
    PORT
      LAYER met2 ;
        RECT 798.650 846.000 798.930 850.000 ;
    END
  END tag[2]
  PIN tag[30]
    DIRECTION OUTPUT ;
    USE SIGNAL ;
    ANTENNADIFFAREA 0.445500 ;
    PORT
      LAYER met2 ;
        RECT 463.770 846.000 464.050 850.000 ;
    END
  END tag[30]
  PIN tag[31]
    DIRECTION OUTPUT ;
    USE SIGNAL ;
    ANTENNADIFFAREA 0.445500 ;
    PORT
      LAYER met2 ;
        RECT 280.230 846.000 280.510 850.000 ;
    END
  END tag[31]
  PIN tag[32]
    DIRECTION OUTPUT ;
    USE SIGNAL ;
    ANTENNADIFFAREA 0.445500 ;
    PORT
      LAYER met2 ;
        RECT 669.850 846.000 670.130 850.000 ;
    END
  END tag[32]
  PIN tag[33]
    DIRECTION OUTPUT ;
    USE SIGNAL ;
    ANTENNADIFFAREA 0.445500 ;
    PORT
      LAYER met2 ;
        RECT 257.690 846.000 257.970 850.000 ;
    END
  END tag[33]
  PIN tag[34]
    DIRECTION OUTPUT ;
    USE SIGNAL ;
    ANTENNADIFFAREA 0.445500 ;
    PORT
      LAYER met2 ;
        RECT 740.690 846.000 740.970 850.000 ;
    END
  END tag[34]
  PIN tag[35]
    DIRECTION OUTPUT ;
    USE SIGNAL ;
    ANTENNADIFFAREA 0.445500 ;
    PORT
      LAYER met2 ;
        RECT 714.930 846.000 715.210 850.000 ;
    END
  END tag[35]
  PIN tag[36]
    DIRECTION OUTPUT ;
    USE SIGNAL ;
    ANTENNADIFFAREA 0.445500 ;
    PORT
      LAYER met2 ;
        RECT 731.030 846.000 731.310 850.000 ;
    END
  END tag[36]
  PIN tag[37]
    DIRECTION OUTPUT ;
    USE SIGNAL ;
    ANTENNADIFFAREA 0.445500 ;
    PORT
      LAYER met2 ;
        RECT 244.810 846.000 245.090 850.000 ;
    END
  END tag[37]
  PIN tag[38]
    DIRECTION OUTPUT ;
    USE SIGNAL ;
    ANTENNADIFFAREA 0.445500 ;
    PORT
      LAYER met2 ;
        RECT 747.130 846.000 747.410 850.000 ;
    END
  END tag[38]
  PIN tag[39]
    DIRECTION OUTPUT ;
    USE SIGNAL ;
    ANTENNADIFFAREA 0.445500 ;
    PORT
      LAYER met2 ;
        RECT 695.610 846.000 695.890 850.000 ;
    END
  END tag[39]
  PIN tag[3]
    DIRECTION OUTPUT ;
    USE SIGNAL ;
    ANTENNADIFFAREA 0.445500 ;
    PORT
      LAYER met2 ;
        RECT 673.070 846.000 673.350 850.000 ;
    END
  END tag[3]
  PIN tag[40]
    DIRECTION OUTPUT ;
    USE SIGNAL ;
    ANTENNADIFFAREA 0.445500 ;
    PORT
      LAYER met2 ;
        RECT 660.190 846.000 660.470 850.000 ;
    END
  END tag[40]
  PIN tag[41]
    DIRECTION OUTPUT ;
    USE SIGNAL ;
    ANTENNADIFFAREA 0.445500 ;
    PORT
      LAYER met2 ;
        RECT 846.950 846.000 847.230 850.000 ;
    END
  END tag[41]
  PIN tag[42]
    DIRECTION OUTPUT ;
    USE SIGNAL ;
    ANTENNADIFFAREA 0.445500 ;
    PORT
      LAYER met2 ;
        RECT 824.410 846.000 824.690 850.000 ;
    END
  END tag[42]
  PIN tag[43]
    DIRECTION OUTPUT ;
    USE SIGNAL ;
    ANTENNADIFFAREA 0.445500 ;
    PORT
      LAYER met2 ;
        RECT 734.250 846.000 734.530 850.000 ;
    END
  END tag[43]
  PIN tag[44]
    DIRECTION OUTPUT ;
    USE SIGNAL ;
    ANTENNADIFFAREA 0.445500 ;
    PORT
      LAYER met2 ;
        RECT 228.710 846.000 228.990 850.000 ;
    END
  END tag[44]
  PIN tag[45]
    DIRECTION OUTPUT ;
    USE SIGNAL ;
    ANTENNADIFFAREA 0.445500 ;
    PORT
      LAYER met2 ;
        RECT 711.710 846.000 711.990 850.000 ;
    END
  END tag[45]
  PIN tag[46]
    DIRECTION OUTPUT ;
    USE SIGNAL ;
    ANTENNADIFFAREA 0.445500 ;
    PORT
      LAYER met2 ;
        RECT 779.330 846.000 779.610 850.000 ;
    END
  END tag[46]
  PIN tag[47]
    DIRECTION OUTPUT ;
    USE SIGNAL ;
    ANTENNADIFFAREA 0.445500 ;
    PORT
      LAYER met2 ;
        RECT 611.890 846.000 612.170 850.000 ;
    END
  END tag[47]
  PIN tag[48]
    DIRECTION OUTPUT ;
    USE SIGNAL ;
    ANTENNADIFFAREA 0.445500 ;
    PORT
      LAYER met2 ;
        RECT 788.990 846.000 789.270 850.000 ;
    END
  END tag[48]
  PIN tag[49]
    DIRECTION OUTPUT ;
    USE SIGNAL ;
    ANTENNADIFFAREA 0.445500 ;
    PORT
      LAYER met2 ;
        RECT 814.750 846.000 815.030 850.000 ;
    END
  END tag[49]
  PIN tag[4]
    DIRECTION OUTPUT ;
    USE SIGNAL ;
    ANTENNADIFFAREA 0.445500 ;
    PORT
      LAYER met2 ;
        RECT 808.310 846.000 808.590 850.000 ;
    END
  END tag[4]
  PIN tag[50]
    DIRECTION OUTPUT ;
    USE SIGNAL ;
    ANTENNADIFFAREA 0.445500 ;
    PORT
      LAYER met2 ;
        RECT 795.430 846.000 795.710 850.000 ;
    END
  END tag[50]
  PIN tag[51]
    DIRECTION OUTPUT ;
    USE SIGNAL ;
    ANTENNADIFFAREA 0.445500 ;
    PORT
      LAYER met2 ;
        RECT 679.510 846.000 679.790 850.000 ;
    END
  END tag[51]
  PIN tag[52]
    DIRECTION OUTPUT ;
    USE SIGNAL ;
    ANTENNADIFFAREA 0.445500 ;
    PORT
      LAYER met2 ;
        RECT 248.030 846.000 248.310 850.000 ;
    END
  END tag[52]
  PIN tag[53]
    DIRECTION OUTPUT ;
    USE SIGNAL ;
    ANTENNADIFFAREA 0.445500 ;
    PORT
      LAYER met2 ;
        RECT 766.450 846.000 766.730 850.000 ;
    END
  END tag[53]
  PIN tag[54]
    DIRECTION OUTPUT ;
    USE SIGNAL ;
    ANTENNADIFFAREA 0.445500 ;
    PORT
      LAYER met2 ;
        RECT 347.850 846.000 348.130 850.000 ;
    END
  END tag[54]
  PIN tag[55]
    DIRECTION OUTPUT ;
    USE SIGNAL ;
    ANTENNADIFFAREA 0.445500 ;
    PORT
      LAYER met2 ;
        RECT 843.730 846.000 844.010 850.000 ;
    END
  END tag[55]
  PIN tag[56]
    DIRECTION OUTPUT ;
    USE SIGNAL ;
    ANTENNADIFFAREA 0.445500 ;
    PORT
      LAYER met2 ;
        RECT 566.810 846.000 567.090 850.000 ;
    END
  END tag[56]
  PIN tag[57]
    DIRECTION OUTPUT ;
    USE SIGNAL ;
    ANTENNADIFFAREA 0.445500 ;
    PORT
      LAYER met2 ;
        RECT 666.630 846.000 666.910 850.000 ;
    END
  END tag[57]
  PIN tag[58]
    DIRECTION OUTPUT ;
    USE SIGNAL ;
    ANTENNADIFFAREA 0.445500 ;
    PORT
      LAYER met2 ;
        RECT 238.370 846.000 238.650 850.000 ;
    END
  END tag[58]
  PIN tag[59]
    DIRECTION OUTPUT ;
    USE SIGNAL ;
    ANTENNADIFFAREA 0.445500 ;
    PORT
      LAYER met2 ;
        RECT 685.950 846.000 686.230 850.000 ;
    END
  END tag[59]
  PIN tag[5]
    DIRECTION OUTPUT ;
    USE SIGNAL ;
    ANTENNADIFFAREA 0.445500 ;
    PORT
      LAYER met2 ;
        RECT 499.190 846.000 499.470 850.000 ;
    END
  END tag[5]
  PIN tag[60]
    DIRECTION OUTPUT ;
    USE SIGNAL ;
    ANTENNADIFFAREA 0.445500 ;
    PORT
      LAYER met2 ;
        RECT 776.110 846.000 776.390 850.000 ;
    END
  END tag[60]
  PIN tag[61]
    DIRECTION OUTPUT ;
    USE SIGNAL ;
    ANTENNADIFFAREA 0.445500 ;
    PORT
      LAYER met2 ;
        RECT 698.830 846.000 699.110 850.000 ;
    END
  END tag[61]
  PIN tag[62]
    DIRECTION OUTPUT ;
    USE SIGNAL ;
    ANTENNADIFFAREA 0.445500 ;
    PORT
      LAYER met2 ;
        RECT 582.910 846.000 583.190 850.000 ;
    END
  END tag[62]
  PIN tag[63]
    DIRECTION OUTPUT ;
    USE SIGNAL ;
    ANTENNADIFFAREA 0.445500 ;
    PORT
      LAYER met2 ;
        RECT 273.790 846.000 274.070 850.000 ;
    END
  END tag[63]
  PIN tag[64]
    DIRECTION OUTPUT ;
    USE SIGNAL ;
    ANTENNADIFFAREA 0.445500 ;
    PORT
      LAYER met2 ;
        RECT 615.110 846.000 615.390 850.000 ;
    END
  END tag[64]
  PIN tag[65]
    DIRECTION OUTPUT ;
    USE SIGNAL ;
    ANTENNADIFFAREA 0.445500 ;
    PORT
      LAYER met2 ;
        RECT 595.790 846.000 596.070 850.000 ;
    END
  END tag[65]
  PIN tag[66]
    DIRECTION OUTPUT ;
    USE SIGNAL ;
    ANTENNADIFFAREA 0.445500 ;
    PORT
      LAYER met2 ;
        RECT 737.470 846.000 737.750 850.000 ;
    END
  END tag[66]
  PIN tag[67]
    DIRECTION OUTPUT ;
    USE SIGNAL ;
    ANTENNADIFFAREA 0.445500 ;
    PORT
      LAYER met2 ;
        RECT 721.370 846.000 721.650 850.000 ;
    END
  END tag[67]
  PIN tag[68]
    DIRECTION OUTPUT ;
    USE SIGNAL ;
    ANTENNADIFFAREA 0.445500 ;
    PORT
      LAYER met2 ;
        RECT 724.590 846.000 724.870 850.000 ;
    END
  END tag[68]
  PIN tag[69]
    DIRECTION OUTPUT ;
    USE SIGNAL ;
    ANTENNADIFFAREA 0.445500 ;
    PORT
      LAYER met2 ;
        RECT 425.130 846.000 425.410 850.000 ;
    END
  END tag[69]
  PIN tag[6]
    DIRECTION OUTPUT ;
    USE SIGNAL ;
    ANTENNADIFFAREA 0.445500 ;
    PORT
      LAYER met2 ;
        RECT 827.630 846.000 827.910 850.000 ;
    END
  END tag[6]
  PIN tag[70]
    DIRECTION OUTPUT ;
    USE SIGNAL ;
    ANTENNADIFFAREA 0.445500 ;
    PORT
      LAYER met2 ;
        RECT 760.010 846.000 760.290 850.000 ;
    END
  END tag[70]
  PIN tag[71]
    DIRECTION OUTPUT ;
    USE SIGNAL ;
    ANTENNADIFFAREA 0.445500 ;
    PORT
      LAYER met2 ;
        RECT 708.490 846.000 708.770 850.000 ;
    END
  END tag[71]
  PIN tag[72]
    DIRECTION OUTPUT ;
    USE SIGNAL ;
    ANTENNADIFFAREA 0.445500 ;
    PORT
      LAYER met2 ;
        RECT 650.530 846.000 650.810 850.000 ;
    END
  END tag[72]
  PIN tag[73]
    DIRECTION OUTPUT ;
    USE SIGNAL ;
    ANTENNADIFFAREA 0.445500 ;
    PORT
      LAYER met2 ;
        RECT 811.530 846.000 811.810 850.000 ;
    END
  END tag[73]
  PIN tag[74]
    DIRECTION OUTPUT ;
    USE SIGNAL ;
    ANTENNADIFFAREA 0.445500 ;
    PORT
      LAYER met2 ;
        RECT 785.770 846.000 786.050 850.000 ;
    END
  END tag[74]
  PIN tag[75]
    DIRECTION OUTPUT ;
    USE SIGNAL ;
    ANTENNADIFFAREA 0.445500 ;
    PORT
      LAYER met2 ;
        RECT 805.090 846.000 805.370 850.000 ;
    END
  END tag[75]
  PIN tag[76]
    DIRECTION OUTPUT ;
    USE SIGNAL ;
    ANTENNADIFFAREA 0.445500 ;
    PORT
      LAYER met2 ;
        RECT 550.710 846.000 550.990 850.000 ;
    END
  END tag[76]
  PIN tag[77]
    DIRECTION OUTPUT ;
    USE SIGNAL ;
    ANTENNADIFFAREA 0.445500 ;
    PORT
      LAYER met2 ;
        RECT 705.270 846.000 705.550 850.000 ;
    END
  END tag[77]
  PIN tag[78]
    DIRECTION OUTPUT ;
    USE SIGNAL ;
    ANTENNADIFFAREA 0.445500 ;
    PORT
      LAYER met2 ;
        RECT 801.870 846.000 802.150 850.000 ;
    END
  END tag[78]
  PIN tag[79]
    DIRECTION OUTPUT ;
    USE SIGNAL ;
    ANTENNADIFFAREA 0.445500 ;
    PORT
      LAYER met2 ;
        RECT 586.130 846.000 586.410 850.000 ;
    END
  END tag[79]
  PIN tag[7]
    DIRECTION OUTPUT ;
    USE SIGNAL ;
    ANTENNADIFFAREA 0.445500 ;
    PORT
      LAYER met2 ;
        RECT 753.570 846.000 753.850 850.000 ;
    END
  END tag[7]
  PIN tag[80]
    DIRECTION OUTPUT ;
    USE SIGNAL ;
    ANTENNADIFFAREA 0.445500 ;
    PORT
      LAYER met2 ;
        RECT 837.290 846.000 837.570 850.000 ;
    END
  END tag[80]
  PIN tag[81]
    DIRECTION OUTPUT ;
    USE SIGNAL ;
    ANTENNADIFFAREA 0.445500 ;
    PORT
      LAYER met2 ;
        RECT 769.670 846.000 769.950 850.000 ;
    END
  END tag[81]
  PIN tag[82]
    DIRECTION OUTPUT ;
    USE SIGNAL ;
    ANTENNADIFFAREA 0.445500 ;
    PORT
      LAYER met2 ;
        RECT 830.850 846.000 831.130 850.000 ;
    END
  END tag[82]
  PIN tag[83]
    DIRECTION OUTPUT ;
    USE SIGNAL ;
    ANTENNADIFFAREA 0.445500 ;
    PORT
      LAYER met2 ;
        RECT 756.790 846.000 757.070 850.000 ;
    END
  END tag[83]
  PIN tag[84]
    DIRECTION OUTPUT ;
    USE SIGNAL ;
    ANTENNADIFFAREA 0.445500 ;
    PORT
      LAYER met2 ;
        RECT 392.930 846.000 393.210 850.000 ;
    END
  END tag[84]
  PIN tag[85]
    DIRECTION OUTPUT ;
    USE SIGNAL ;
    ANTENNADIFFAREA 0.445500 ;
    PORT
      LAYER met2 ;
        RECT 727.810 846.000 728.090 850.000 ;
    END
  END tag[85]
  PIN tag[86]
    DIRECTION OUTPUT ;
    USE SIGNAL ;
    ANTENNADIFFAREA 0.445500 ;
    PORT
      LAYER met2 ;
        RECT 627.990 846.000 628.270 850.000 ;
    END
  END tag[86]
  PIN tag[87]
    DIRECTION OUTPUT ;
    USE SIGNAL ;
    ANTENNADIFFAREA 0.445500 ;
    PORT
      LAYER met2 ;
        RECT 682.730 846.000 683.010 850.000 ;
    END
  END tag[87]
  PIN tag[88]
    DIRECTION OUTPUT ;
    USE SIGNAL ;
    ANTENNADIFFAREA 0.445500 ;
    PORT
      LAYER met2 ;
        RECT 305.990 846.000 306.270 850.000 ;
    END
  END tag[88]
  PIN tag[89]
    DIRECTION OUTPUT ;
    USE SIGNAL ;
    ANTENNADIFFAREA 0.445500 ;
    PORT
      LAYER met2 ;
        RECT 821.190 846.000 821.470 850.000 ;
    END
  END tag[89]
  PIN tag[8]
    DIRECTION OUTPUT ;
    USE SIGNAL ;
    ANTENNADIFFAREA 0.445500 ;
    PORT
      LAYER met2 ;
        RECT 676.290 846.000 676.570 850.000 ;
    END
  END tag[8]
  PIN tag[90]
    DIRECTION OUTPUT ;
    USE SIGNAL ;
    ANTENNADIFFAREA 0.445500 ;
    PORT
      LAYER met2 ;
        RECT 231.930 846.000 232.210 850.000 ;
    END
  END tag[90]
  PIN tag[91]
    DIRECTION OUTPUT ;
    USE SIGNAL ;
    ANTENNADIFFAREA 0.445500 ;
    PORT
      LAYER met3 ;
        RECT 0.000 775.240 4.000 775.840 ;
    END
  END tag[91]
  PIN tag[92]
    DIRECTION OUTPUT ;
    USE SIGNAL ;
    ANTENNADIFFAREA 0.445500 ;
    PORT
      LAYER met3 ;
        RECT 0.000 765.040 4.000 765.640 ;
    END
  END tag[92]
  PIN tag[93]
    DIRECTION OUTPUT ;
    USE SIGNAL ;
    ANTENNADIFFAREA 0.445500 ;
    PORT
      LAYER met3 ;
        RECT 0.000 700.440 4.000 701.040 ;
    END
  END tag[93]
  PIN tag[94]
    DIRECTION OUTPUT ;
    USE SIGNAL ;
    ANTENNADIFFAREA 0.445500 ;
    PORT
      LAYER met3 ;
        RECT 0.000 751.440 4.000 752.040 ;
    END
  END tag[94]
  PIN tag[95]
    DIRECTION OUTPUT ;
    USE SIGNAL ;
    ANTENNADIFFAREA 0.445500 ;
    PORT
      LAYER met3 ;
        RECT 0.000 731.040 4.000 731.640 ;
    END
  END tag[95]
  PIN tag[96]
    DIRECTION OUTPUT ;
    USE SIGNAL ;
    ANTENNADIFFAREA 0.445500 ;
    PORT
      LAYER met3 ;
        RECT 0.000 659.640 4.000 660.240 ;
    END
  END tag[96]
  PIN tag[97]
    DIRECTION OUTPUT ;
    USE SIGNAL ;
    ANTENNADIFFAREA 0.445500 ;
    PORT
      LAYER met3 ;
        RECT 0.000 557.640 4.000 558.240 ;
    END
  END tag[97]
  PIN tag[98]
    DIRECTION OUTPUT ;
    USE SIGNAL ;
    ANTENNADIFFAREA 0.445500 ;
    PORT
      LAYER met3 ;
        RECT 0.000 618.840 4.000 619.440 ;
    END
  END tag[98]
  PIN tag[99]
    DIRECTION OUTPUT ;
    USE SIGNAL ;
    ANTENNADIFFAREA 0.445500 ;
    PORT
      LAYER met3 ;
        RECT 0.000 693.640 4.000 694.240 ;
    END
  END tag[99]
  PIN tag[9]
    DIRECTION OUTPUT ;
    USE SIGNAL ;
    ANTENNADIFFAREA 0.445500 ;
    PORT
      LAYER met3 ;
        RECT 0.000 309.440 4.000 310.040 ;
    END
  END tag[9]
  PIN tag_in[0]
    DIRECTION INPUT ;
    USE SIGNAL ;
    ANTENNAGATEAREA 0.196500 ;
    PORT
      LAYER met3 ;
        RECT 0.000 629.040 4.000 629.640 ;
    END
  END tag_in[0]
  PIN tag_in[100]
    DIRECTION INPUT ;
    USE SIGNAL ;
    ANTENNAGATEAREA 0.196500 ;
    PORT
      LAYER met3 ;
        RECT 0.000 353.640 4.000 354.240 ;
    END
  END tag_in[100]
  PIN tag_in[101]
    DIRECTION INPUT ;
    USE SIGNAL ;
    ANTENNAGATEAREA 0.196500 ;
    PORT
      LAYER met3 ;
        RECT 0.000 401.240 4.000 401.840 ;
    END
  END tag_in[101]
  PIN tag_in[102]
    DIRECTION INPUT ;
    USE SIGNAL ;
    ANTENNAGATEAREA 0.196500 ;
    PORT
      LAYER met3 ;
        RECT 0.000 370.640 4.000 371.240 ;
    END
  END tag_in[102]
  PIN tag_in[103]
    DIRECTION INPUT ;
    USE SIGNAL ;
    ANTENNAGATEAREA 0.196500 ;
    PORT
      LAYER met3 ;
        RECT 0.000 357.040 4.000 357.640 ;
    END
  END tag_in[103]
  PIN tag_in[104]
    DIRECTION INPUT ;
    USE SIGNAL ;
    ANTENNAGATEAREA 0.196500 ;
    PORT
      LAYER met3 ;
        RECT 0.000 323.040 4.000 323.640 ;
    END
  END tag_in[104]
  PIN tag_in[105]
    DIRECTION INPUT ;
    USE SIGNAL ;
    ANTENNAGATEAREA 0.196500 ;
    PORT
      LAYER met3 ;
        RECT 0.000 428.440 4.000 429.040 ;
    END
  END tag_in[105]
  PIN tag_in[106]
    DIRECTION INPUT ;
    USE SIGNAL ;
    ANTENNAGATEAREA 0.196500 ;
    PORT
      LAYER met3 ;
        RECT 0.000 394.440 4.000 395.040 ;
    END
  END tag_in[106]
  PIN tag_in[107]
    DIRECTION INPUT ;
    USE SIGNAL ;
    ANTENNAGATEAREA 0.196500 ;
    PORT
      LAYER met3 ;
        RECT 0.000 431.840 4.000 432.440 ;
    END
  END tag_in[107]
  PIN tag_in[108]
    DIRECTION INPUT ;
    USE SIGNAL ;
    ANTENNAGATEAREA 0.196500 ;
    PORT
      LAYER met3 ;
        RECT 0.000 452.240 4.000 452.840 ;
    END
  END tag_in[108]
  PIN tag_in[109]
    DIRECTION INPUT ;
    USE SIGNAL ;
    ANTENNAGATEAREA 0.196500 ;
    PORT
      LAYER met3 ;
        RECT 0.000 411.440 4.000 412.040 ;
    END
  END tag_in[109]
  PIN tag_in[10]
    DIRECTION INPUT ;
    USE SIGNAL ;
    ANTENNAGATEAREA 0.196500 ;
    PORT
      LAYER met3 ;
        RECT 0.000 605.240 4.000 605.840 ;
    END
  END tag_in[10]
  PIN tag_in[110]
    DIRECTION INPUT ;
    USE SIGNAL ;
    ANTENNAGATEAREA 0.196500 ;
    PORT
      LAYER met3 ;
        RECT 0.000 387.640 4.000 388.240 ;
    END
  END tag_in[110]
  PIN tag_in[111]
    DIRECTION INPUT ;
    USE SIGNAL ;
    ANTENNAGATEAREA 0.196500 ;
    PORT
      LAYER met3 ;
        RECT 0.000 445.440 4.000 446.040 ;
    END
  END tag_in[111]
  PIN tag_in[112]
    DIRECTION INPUT ;
    USE SIGNAL ;
    ANTENNAGATEAREA 0.196500 ;
    PORT
      LAYER met3 ;
        RECT 0.000 384.240 4.000 384.840 ;
    END
  END tag_in[112]
  PIN tag_in[113]
    DIRECTION INPUT ;
    USE SIGNAL ;
    ANTENNAGATEAREA 0.196500 ;
    PORT
      LAYER met3 ;
        RECT 0.000 438.640 4.000 439.240 ;
    END
  END tag_in[113]
  PIN tag_in[114]
    DIRECTION INPUT ;
    USE SIGNAL ;
    ANTENNAGATEAREA 0.196500 ;
    PORT
      LAYER met3 ;
        RECT 0.000 329.840 4.000 330.440 ;
    END
  END tag_in[114]
  PIN tag_in[115]
    DIRECTION INPUT ;
    USE SIGNAL ;
    ANTENNAGATEAREA 0.196500 ;
    PORT
      LAYER met3 ;
        RECT 0.000 448.840 4.000 449.440 ;
    END
  END tag_in[115]
  PIN tag_in[116]
    DIRECTION INPUT ;
    USE SIGNAL ;
    ANTENNAGATEAREA 0.196500 ;
    PORT
      LAYER met3 ;
        RECT 0.000 360.440 4.000 361.040 ;
    END
  END tag_in[116]
  PIN tag_in[117]
    DIRECTION INPUT ;
    USE SIGNAL ;
    ANTENNAGATEAREA 0.196500 ;
    PORT
      LAYER met3 ;
        RECT 0.000 462.440 4.000 463.040 ;
    END
  END tag_in[117]
  PIN tag_in[118]
    DIRECTION INPUT ;
    USE SIGNAL ;
    ANTENNAGATEAREA 0.196500 ;
    PORT
      LAYER met3 ;
        RECT 0.000 465.840 4.000 466.440 ;
    END
  END tag_in[118]
  PIN tag_in[119]
    DIRECTION INPUT ;
    USE SIGNAL ;
    ANTENNAGATEAREA 0.196500 ;
    PORT
      LAYER met3 ;
        RECT 0.000 377.440 4.000 378.040 ;
    END
  END tag_in[119]
  PIN tag_in[11]
    DIRECTION INPUT ;
    USE SIGNAL ;
    ANTENNAGATEAREA 0.196500 ;
    PORT
      LAYER met3 ;
        RECT 0.000 680.040 4.000 680.640 ;
    END
  END tag_in[11]
  PIN tag_in[120]
    DIRECTION INPUT ;
    USE SIGNAL ;
    ANTENNAGATEAREA 0.196500 ;
    PORT
      LAYER met3 ;
        RECT 0.000 340.040 4.000 340.640 ;
    END
  END tag_in[120]
  PIN tag_in[121]
    DIRECTION INPUT ;
    USE SIGNAL ;
    ANTENNAGATEAREA 0.196500 ;
    PORT
      LAYER met3 ;
        RECT 0.000 319.640 4.000 320.240 ;
    END
  END tag_in[121]
  PIN tag_in[122]
    DIRECTION INPUT ;
    USE SIGNAL ;
    ANTENNAGATEAREA 0.196500 ;
    PORT
      LAYER met3 ;
        RECT 0.000 374.040 4.000 374.640 ;
    END
  END tag_in[122]
  PIN tag_in[123]
    DIRECTION INPUT ;
    USE SIGNAL ;
    ANTENNAGATEAREA 0.196500 ;
    PORT
      LAYER met3 ;
        RECT 0.000 421.640 4.000 422.240 ;
    END
  END tag_in[123]
  PIN tag_in[124]
    DIRECTION INPUT ;
    USE SIGNAL ;
    ANTENNAGATEAREA 0.196500 ;
    PORT
      LAYER met3 ;
        RECT 0.000 486.240 4.000 486.840 ;
    END
  END tag_in[124]
  PIN tag_in[125]
    DIRECTION INPUT ;
    USE SIGNAL ;
    ANTENNAGATEAREA 0.196500 ;
    PORT
      LAYER met3 ;
        RECT 0.000 476.040 4.000 476.640 ;
    END
  END tag_in[125]
  PIN tag_in[126]
    DIRECTION INPUT ;
    USE SIGNAL ;
    ANTENNAGATEAREA 0.196500 ;
    PORT
      LAYER met3 ;
        RECT 0.000 442.040 4.000 442.640 ;
    END
  END tag_in[126]
  PIN tag_in[127]
    DIRECTION INPUT ;
    USE SIGNAL ;
    ANTENNAGATEAREA 0.196500 ;
    PORT
      LAYER met3 ;
        RECT 0.000 479.440 4.000 480.040 ;
    END
  END tag_in[127]
  PIN tag_in[12]
    DIRECTION INPUT ;
    USE SIGNAL ;
    ANTENNAGATEAREA 0.196500 ;
    PORT
      LAYER met3 ;
        RECT 0.000 588.240 4.000 588.840 ;
    END
  END tag_in[12]
  PIN tag_in[13]
    DIRECTION INPUT ;
    USE SIGNAL ;
    ANTENNAGATEAREA 0.196500 ;
    PORT
      LAYER met3 ;
        RECT 0.000 656.240 4.000 656.840 ;
    END
  END tag_in[13]
  PIN tag_in[14]
    DIRECTION INPUT ;
    USE SIGNAL ;
    ANTENNAGATEAREA 0.196500 ;
    PORT
      LAYER met3 ;
        RECT 0.000 724.240 4.000 724.840 ;
    END
  END tag_in[14]
  PIN tag_in[15]
    DIRECTION INPUT ;
    USE SIGNAL ;
    ANTENNAGATEAREA 0.196500 ;
    PORT
      LAYER met3 ;
        RECT 0.000 646.040 4.000 646.640 ;
    END
  END tag_in[15]
  PIN tag_in[16]
    DIRECTION INPUT ;
    USE SIGNAL ;
    ANTENNAGATEAREA 0.196500 ;
    PORT
      LAYER met3 ;
        RECT 0.000 758.240 4.000 758.840 ;
    END
  END tag_in[16]
  PIN tag_in[17]
    DIRECTION INPUT ;
    USE SIGNAL ;
    ANTENNAGATEAREA 0.196500 ;
    PORT
      LAYER met3 ;
        RECT 0.000 632.440 4.000 633.040 ;
    END
  END tag_in[17]
  PIN tag_in[18]
    DIRECTION INPUT ;
    USE SIGNAL ;
    ANTENNAGATEAREA 0.196500 ;
    PORT
      LAYER met3 ;
        RECT 0.000 703.840 4.000 704.440 ;
    END
  END tag_in[18]
  PIN tag_in[19]
    DIRECTION INPUT ;
    USE SIGNAL ;
    ANTENNAGATEAREA 0.196500 ;
    PORT
      LAYER met3 ;
        RECT 0.000 554.240 4.000 554.840 ;
    END
  END tag_in[19]
  PIN tag_in[1]
    DIRECTION INPUT ;
    USE SIGNAL ;
    ANTENNAGATEAREA 0.196500 ;
    PORT
      LAYER met3 ;
        RECT 0.000 717.440 4.000 718.040 ;
    END
  END tag_in[1]
  PIN tag_in[20]
    DIRECTION INPUT ;
    USE SIGNAL ;
    ANTENNAGATEAREA 0.196500 ;
    PORT
      LAYER met3 ;
        RECT 0.000 578.040 4.000 578.640 ;
    END
  END tag_in[20]
  PIN tag_in[21]
    DIRECTION INPUT ;
    USE SIGNAL ;
    ANTENNAGATEAREA 0.196500 ;
    PORT
      LAYER met3 ;
        RECT 0.000 741.240 4.000 741.840 ;
    END
  END tag_in[21]
  PIN tag_in[22]
    DIRECTION INPUT ;
    USE SIGNAL ;
    ANTENNAGATEAREA 0.196500 ;
    PORT
      LAYER met3 ;
        RECT 0.000 737.840 4.000 738.440 ;
    END
  END tag_in[22]
  PIN tag_in[23]
    DIRECTION INPUT ;
    USE SIGNAL ;
    ANTENNAGATEAREA 0.196500 ;
    PORT
      LAYER met3 ;
        RECT 0.000 748.040 4.000 748.640 ;
    END
  END tag_in[23]
  PIN tag_in[24]
    DIRECTION INPUT ;
    USE SIGNAL ;
    ANTENNAGATEAREA 0.196500 ;
    PORT
      LAYER met3 ;
        RECT 0.000 567.840 4.000 568.440 ;
    END
  END tag_in[24]
  PIN tag_in[25]
    DIRECTION INPUT ;
    USE SIGNAL ;
    ANTENNAGATEAREA 0.196500 ;
    PORT
      LAYER met3 ;
        RECT 0.000 663.040 4.000 663.640 ;
    END
  END tag_in[25]
  PIN tag_in[26]
    DIRECTION INPUT ;
    USE SIGNAL ;
    ANTENNAGATEAREA 0.196500 ;
    PORT
      LAYER met3 ;
        RECT 0.000 710.640 4.000 711.240 ;
    END
  END tag_in[26]
  PIN tag_in[27]
    DIRECTION INPUT ;
    USE SIGNAL ;
    ANTENNAGATEAREA 0.196500 ;
    PORT
      LAYER met3 ;
        RECT 0.000 673.240 4.000 673.840 ;
    END
  END tag_in[27]
  PIN tag_in[28]
    DIRECTION INPUT ;
    USE SIGNAL ;
    ANTENNAGATEAREA 0.196500 ;
    PORT
      LAYER met3 ;
        RECT 0.000 649.440 4.000 650.040 ;
    END
  END tag_in[28]
  PIN tag_in[29]
    DIRECTION INPUT ;
    USE SIGNAL ;
    ANTENNAGATEAREA 0.196500 ;
    PORT
      LAYER met3 ;
        RECT 0.000 612.040 4.000 612.640 ;
    END
  END tag_in[29]
  PIN tag_in[2]
    DIRECTION INPUT ;
    USE SIGNAL ;
    ANTENNAGATEAREA 0.196500 ;
    PORT
      LAYER met3 ;
        RECT 0.000 714.040 4.000 714.640 ;
    END
  END tag_in[2]
  PIN tag_in[30]
    DIRECTION INPUT ;
    USE SIGNAL ;
    ANTENNAGATEAREA 0.196500 ;
    PORT
      LAYER met3 ;
        RECT 0.000 720.840 4.000 721.440 ;
    END
  END tag_in[30]
  PIN tag_in[31]
    DIRECTION INPUT ;
    USE SIGNAL ;
    ANTENNAGATEAREA 0.196500 ;
    PORT
      LAYER met3 ;
        RECT 0.000 574.640 4.000 575.240 ;
    END
  END tag_in[31]
  PIN tag_in[32]
    DIRECTION INPUT ;
    USE SIGNAL ;
    ANTENNAGATEAREA 0.196500 ;
    PORT
      LAYER met3 ;
        RECT 0.000 608.640 4.000 609.240 ;
    END
  END tag_in[32]
  PIN tag_in[33]
    DIRECTION INPUT ;
    USE SIGNAL ;
    ANTENNAGATEAREA 0.196500 ;
    PORT
      LAYER met3 ;
        RECT 0.000 408.040 4.000 408.640 ;
    END
  END tag_in[33]
  PIN tag_in[34]
    DIRECTION INPUT ;
    USE SIGNAL ;
    ANTENNAGATEAREA 0.196500 ;
    PORT
      LAYER met3 ;
        RECT 0.000 754.840 4.000 755.440 ;
    END
  END tag_in[34]
  PIN tag_in[35]
    DIRECTION INPUT ;
    USE SIGNAL ;
    ANTENNAGATEAREA 0.196500 ;
    PORT
      LAYER met3 ;
        RECT 0.000 530.440 4.000 531.040 ;
    END
  END tag_in[35]
  PIN tag_in[36]
    DIRECTION INPUT ;
    USE SIGNAL ;
    ANTENNAGATEAREA 0.196500 ;
    PORT
      LAYER met3 ;
        RECT 0.000 564.440 4.000 565.040 ;
    END
  END tag_in[36]
  PIN tag_in[37]
    DIRECTION INPUT ;
    USE SIGNAL ;
    ANTENNAGATEAREA 0.196500 ;
    PORT
      LAYER met3 ;
        RECT 0.000 666.440 4.000 667.040 ;
    END
  END tag_in[37]
  PIN tag_in[38]
    DIRECTION INPUT ;
    USE SIGNAL ;
    ANTENNAGATEAREA 0.196500 ;
    PORT
      LAYER met3 ;
        RECT 0.000 697.040 4.000 697.640 ;
    END
  END tag_in[38]
  PIN tag_in[39]
    DIRECTION INPUT ;
    USE SIGNAL ;
    ANTENNAGATEAREA 0.196500 ;
    PORT
      LAYER met3 ;
        RECT 0.000 523.640 4.000 524.240 ;
    END
  END tag_in[39]
  PIN tag_in[3]
    DIRECTION INPUT ;
    USE SIGNAL ;
    ANTENNAGATEAREA 0.196500 ;
    PORT
      LAYER met3 ;
        RECT 0.000 622.240 4.000 622.840 ;
    END
  END tag_in[3]
  PIN tag_in[40]
    DIRECTION INPUT ;
    USE SIGNAL ;
    ANTENNAGATEAREA 0.196500 ;
    PORT
      LAYER met3 ;
        RECT 0.000 676.640 4.000 677.240 ;
    END
  END tag_in[40]
  PIN tag_in[41]
    DIRECTION INPUT ;
    USE SIGNAL ;
    ANTENNAGATEAREA 0.196500 ;
    PORT
      LAYER met3 ;
        RECT 0.000 306.040 4.000 306.640 ;
    END
  END tag_in[41]
  PIN tag_in[42]
    DIRECTION INPUT ;
    USE SIGNAL ;
    ANTENNAGATEAREA 0.196500 ;
    PORT
      LAYER met3 ;
        RECT 0.000 635.840 4.000 636.440 ;
    END
  END tag_in[42]
  PIN tag_in[43]
    DIRECTION INPUT ;
    USE SIGNAL ;
    ANTENNAGATEAREA 0.196500 ;
    PORT
      LAYER met3 ;
        RECT 0.000 550.840 4.000 551.440 ;
    END
  END tag_in[43]
  PIN tag_in[44]
    DIRECTION INPUT ;
    USE SIGNAL ;
    ANTENNAGATEAREA 0.196500 ;
    PORT
      LAYER met3 ;
        RECT 0.000 683.440 4.000 684.040 ;
    END
  END tag_in[44]
  PIN tag_in[45]
    DIRECTION INPUT ;
    USE SIGNAL ;
    ANTENNAGATEAREA 0.196500 ;
    PORT
      LAYER met3 ;
        RECT 0.000 336.640 4.000 337.240 ;
    END
  END tag_in[45]
  PIN tag_in[46]
    DIRECTION INPUT ;
    USE SIGNAL ;
    ANTENNAGATEAREA 0.196500 ;
    PORT
      LAYER met3 ;
        RECT 0.000 591.640 4.000 592.240 ;
    END
  END tag_in[46]
  PIN tag_in[47]
    DIRECTION INPUT ;
    USE SIGNAL ;
    ANTENNAGATEAREA 0.196500 ;
    PORT
      LAYER met3 ;
        RECT 0.000 652.840 4.000 653.440 ;
    END
  END tag_in[47]
  PIN tag_in[48]
    DIRECTION INPUT ;
    USE SIGNAL ;
    ANTENNAGATEAREA 0.196500 ;
    PORT
      LAYER met3 ;
        RECT 0.000 561.040 4.000 561.640 ;
    END
  END tag_in[48]
  PIN tag_in[49]
    DIRECTION INPUT ;
    USE SIGNAL ;
    ANTENNAGATEAREA 0.196500 ;
    PORT
      LAYER met3 ;
        RECT 0.000 547.440 4.000 548.040 ;
    END
  END tag_in[49]
  PIN tag_in[4]
    DIRECTION INPUT ;
    USE SIGNAL ;
    ANTENNAGATEAREA 0.196500 ;
    PORT
      LAYER met3 ;
        RECT 0.000 601.840 4.000 602.440 ;
    END
  END tag_in[4]
  PIN tag_in[50]
    DIRECTION INPUT ;
    USE SIGNAL ;
    ANTENNAGATEAREA 0.196500 ;
    PORT
      LAYER met3 ;
        RECT 0.000 727.640 4.000 728.240 ;
    END
  END tag_in[50]
  PIN tag_in[51]
    DIRECTION INPUT ;
    USE SIGNAL ;
    ANTENNAGATEAREA 0.196500 ;
    PORT
      LAYER met3 ;
        RECT 0.000 615.440 4.000 616.040 ;
    END
  END tag_in[51]
  PIN tag_in[52]
    DIRECTION INPUT ;
    USE SIGNAL ;
    ANTENNAGATEAREA 0.196500 ;
    PORT
      LAYER met3 ;
        RECT 0.000 734.440 4.000 735.040 ;
    END
  END tag_in[52]
  PIN tag_in[53]
    DIRECTION INPUT ;
    USE SIGNAL ;
    ANTENNAGATEAREA 0.196500 ;
    PORT
      LAYER met3 ;
        RECT 0.000 625.640 4.000 626.240 ;
    END
  END tag_in[53]
  PIN tag_in[54]
    DIRECTION INPUT ;
    USE SIGNAL ;
    ANTENNAGATEAREA 0.196500 ;
    PORT
      LAYER met3 ;
        RECT 0.000 642.640 4.000 643.240 ;
    END
  END tag_in[54]
  PIN tag_in[55]
    DIRECTION INPUT ;
    USE SIGNAL ;
    ANTENNAGATEAREA 0.196500 ;
    PORT
      LAYER met3 ;
        RECT 0.000 768.440 4.000 769.040 ;
    END
  END tag_in[55]
  PIN tag_in[56]
    DIRECTION INPUT ;
    USE SIGNAL ;
    ANTENNAGATEAREA 0.196500 ;
    PORT
      LAYER met3 ;
        RECT 0.000 571.240 4.000 571.840 ;
    END
  END tag_in[56]
  PIN tag_in[57]
    DIRECTION INPUT ;
    USE SIGNAL ;
    ANTENNAGATEAREA 0.196500 ;
    PORT
      LAYER met3 ;
        RECT 0.000 316.240 4.000 316.840 ;
    END
  END tag_in[57]
  PIN tag_in[58]
    DIRECTION INPUT ;
    USE SIGNAL ;
    ANTENNAGATEAREA 0.196500 ;
    PORT
      LAYER met3 ;
        RECT 0.000 707.240 4.000 707.840 ;
    END
  END tag_in[58]
  PIN tag_in[59]
    DIRECTION INPUT ;
    USE SIGNAL ;
    ANTENNAGATEAREA 0.196500 ;
    PORT
      LAYER met3 ;
        RECT 0.000 686.840 4.000 687.440 ;
    END
  END tag_in[59]
  PIN tag_in[5]
    DIRECTION INPUT ;
    USE SIGNAL ;
    ANTENNAGATEAREA 0.196500 ;
    PORT
      LAYER met3 ;
        RECT 0.000 598.440 4.000 599.040 ;
    END
  END tag_in[5]
  PIN tag_in[60]
    DIRECTION INPUT ;
    USE SIGNAL ;
    ANTENNAGATEAREA 0.196500 ;
    PORT
      LAYER met3 ;
        RECT 0.000 669.840 4.000 670.440 ;
    END
  END tag_in[60]
  PIN tag_in[61]
    DIRECTION INPUT ;
    USE SIGNAL ;
    ANTENNAGATEAREA 0.196500 ;
    PORT
      LAYER met3 ;
        RECT 0.000 639.240 4.000 639.840 ;
    END
  END tag_in[61]
  PIN tag_in[62]
    DIRECTION INPUT ;
    USE SIGNAL ;
    ANTENNAGATEAREA 0.196500 ;
    PORT
      LAYER met3 ;
        RECT 0.000 581.440 4.000 582.040 ;
    END
  END tag_in[62]
  PIN tag_in[63]
    DIRECTION INPUT ;
    USE SIGNAL ;
    ANTENNAGATEAREA 0.196500 ;
    PORT
      LAYER met3 ;
        RECT 0.000 520.240 4.000 520.840 ;
    END
  END tag_in[63]
  PIN tag_in[64]
    DIRECTION INPUT ;
    USE SIGNAL ;
    ANTENNAGATEAREA 0.196500 ;
    PORT
      LAYER met3 ;
        RECT 0.000 533.840 4.000 534.440 ;
    END
  END tag_in[64]
  PIN tag_in[65]
    DIRECTION INPUT ;
    USE SIGNAL ;
    ANTENNAGATEAREA 0.196500 ;
    PORT
      LAYER met3 ;
        RECT 0.000 540.640 4.000 541.240 ;
    END
  END tag_in[65]
  PIN tag_in[66]
    DIRECTION INPUT ;
    USE SIGNAL ;
    ANTENNAGATEAREA 0.196500 ;
    PORT
      LAYER met3 ;
        RECT 0.000 414.840 4.000 415.440 ;
    END
  END tag_in[66]
  PIN tag_in[67]
    DIRECTION INPUT ;
    USE SIGNAL ;
    ANTENNAGATEAREA 0.196500 ;
    PORT
      LAYER met3 ;
        RECT 0.000 496.440 4.000 497.040 ;
    END
  END tag_in[67]
  PIN tag_in[68]
    DIRECTION INPUT ;
    USE SIGNAL ;
    ANTENNAGATEAREA 0.196500 ;
    PORT
      LAYER met3 ;
        RECT 0.000 499.840 4.000 500.440 ;
    END
  END tag_in[68]
  PIN tag_in[69]
    DIRECTION INPUT ;
    USE SIGNAL ;
    ANTENNAGATEAREA 0.196500 ;
    PORT
      LAYER met3 ;
        RECT 0.000 516.840 4.000 517.440 ;
    END
  END tag_in[69]
  PIN tag_in[6]
    DIRECTION INPUT ;
    USE SIGNAL ;
    ANTENNAGATEAREA 0.196500 ;
    PORT
      LAYER met3 ;
        RECT 0.000 584.840 4.000 585.440 ;
    END
  END tag_in[6]
  PIN tag_in[70]
    DIRECTION INPUT ;
    USE SIGNAL ;
    ANTENNAGATEAREA 0.196500 ;
    PORT
      LAYER met3 ;
        RECT 0.000 346.840 4.000 347.440 ;
    END
  END tag_in[70]
  PIN tag_in[71]
    DIRECTION INPUT ;
    USE SIGNAL ;
    ANTENNAGATEAREA 0.196500 ;
    PORT
      LAYER met3 ;
        RECT 0.000 404.640 4.000 405.240 ;
    END
  END tag_in[71]
  PIN tag_in[72]
    DIRECTION INPUT ;
    USE SIGNAL ;
    ANTENNAGATEAREA 0.196500 ;
    PORT
      LAYER met3 ;
        RECT 0.000 343.440 4.000 344.040 ;
    END
  END tag_in[72]
  PIN tag_in[73]
    DIRECTION INPUT ;
    USE SIGNAL ;
    ANTENNAGATEAREA 0.196500 ;
    PORT
      LAYER met3 ;
        RECT 0.000 350.240 4.000 350.840 ;
    END
  END tag_in[73]
  PIN tag_in[74]
    DIRECTION INPUT ;
    USE SIGNAL ;
    ANTENNAGATEAREA 0.196500 ;
    PORT
      LAYER met3 ;
        RECT 0.000 503.240 4.000 503.840 ;
    END
  END tag_in[74]
  PIN tag_in[75]
    DIRECTION INPUT ;
    USE SIGNAL ;
    ANTENNAGATEAREA 0.196500 ;
    PORT
      LAYER met3 ;
        RECT 0.000 493.040 4.000 493.640 ;
    END
  END tag_in[75]
  PIN tag_in[76]
    DIRECTION INPUT ;
    USE SIGNAL ;
    ANTENNAGATEAREA 0.196500 ;
    PORT
      LAYER met3 ;
        RECT 0.000 435.240 4.000 435.840 ;
    END
  END tag_in[76]
  PIN tag_in[77]
    DIRECTION INPUT ;
    USE SIGNAL ;
    ANTENNAGATEAREA 0.196500 ;
    PORT
      LAYER met3 ;
        RECT 0.000 312.840 4.000 313.440 ;
    END
  END tag_in[77]
  PIN tag_in[78]
    DIRECTION INPUT ;
    USE SIGNAL ;
    ANTENNAGATEAREA 0.213000 ;
    PORT
      LAYER met3 ;
        RECT 0.000 761.640 4.000 762.240 ;
    END
  END tag_in[78]
  PIN tag_in[79]
    DIRECTION INPUT ;
    USE SIGNAL ;
    ANTENNAGATEAREA 0.196500 ;
    PORT
      LAYER met3 ;
        RECT 0.000 489.640 4.000 490.240 ;
    END
  END tag_in[79]
  PIN tag_in[7]
    DIRECTION INPUT ;
    USE SIGNAL ;
    ANTENNAGATEAREA 0.196500 ;
    PORT
      LAYER met3 ;
        RECT 0.000 744.640 4.000 745.240 ;
    END
  END tag_in[7]
  PIN tag_in[80]
    DIRECTION INPUT ;
    USE SIGNAL ;
    ANTENNAGATEAREA 0.196500 ;
    PORT
      LAYER met3 ;
        RECT 0.000 380.840 4.000 381.440 ;
    END
  END tag_in[80]
  PIN tag_in[81]
    DIRECTION INPUT ;
    USE SIGNAL ;
    ANTENNAGATEAREA 0.196500 ;
    PORT
      LAYER met3 ;
        RECT 0.000 544.040 4.000 544.640 ;
    END
  END tag_in[81]
  PIN tag_in[82]
    DIRECTION INPUT ;
    USE SIGNAL ;
    ANTENNAGATEAREA 0.196500 ;
    PORT
      LAYER met3 ;
        RECT 0.000 513.440 4.000 514.040 ;
    END
  END tag_in[82]
  PIN tag_in[83]
    DIRECTION INPUT ;
    USE SIGNAL ;
    ANTENNAGATEAREA 0.196500 ;
    PORT
      LAYER met3 ;
        RECT 0.000 367.240 4.000 367.840 ;
    END
  END tag_in[83]
  PIN tag_in[84]
    DIRECTION INPUT ;
    USE SIGNAL ;
    ANTENNAGATEAREA 0.213000 ;
    PORT
      LAYER met3 ;
        RECT 0.000 771.840 4.000 772.440 ;
    END
  END tag_in[84]
  PIN tag_in[85]
    DIRECTION INPUT ;
    USE SIGNAL ;
    ANTENNAGATEAREA 0.196500 ;
    PORT
      LAYER met3 ;
        RECT 0.000 527.040 4.000 527.640 ;
    END
  END tag_in[85]
  PIN tag_in[86]
    DIRECTION INPUT ;
    USE SIGNAL ;
    ANTENNAGATEAREA 0.196500 ;
    PORT
      LAYER met3 ;
        RECT 0.000 506.640 4.000 507.240 ;
    END
  END tag_in[86]
  PIN tag_in[87]
    DIRECTION INPUT ;
    USE SIGNAL ;
    ANTENNAGATEAREA 0.196500 ;
    PORT
      LAYER met3 ;
        RECT 0.000 418.240 4.000 418.840 ;
    END
  END tag_in[87]
  PIN tag_in[88]
    DIRECTION INPUT ;
    USE SIGNAL ;
    ANTENNAGATEAREA 0.196500 ;
    PORT
      LAYER met3 ;
        RECT 0.000 397.840 4.000 398.440 ;
    END
  END tag_in[88]
  PIN tag_in[89]
    DIRECTION INPUT ;
    USE SIGNAL ;
    ANTENNAGATEAREA 0.196500 ;
    PORT
      LAYER met3 ;
        RECT 0.000 425.040 4.000 425.640 ;
    END
  END tag_in[89]
  PIN tag_in[8]
    DIRECTION INPUT ;
    USE SIGNAL ;
    ANTENNAGATEAREA 0.196500 ;
    PORT
      LAYER met3 ;
        RECT 0.000 690.240 4.000 690.840 ;
    END
  END tag_in[8]
  PIN tag_in[90]
    DIRECTION INPUT ;
    USE SIGNAL ;
    ANTENNAGATEAREA 0.196500 ;
    PORT
      LAYER met3 ;
        RECT 0.000 537.240 4.000 537.840 ;
    END
  END tag_in[90]
  PIN tag_in[91]
    DIRECTION INPUT ;
    USE SIGNAL ;
    ANTENNAGATEAREA 0.196500 ;
    PORT
      LAYER met3 ;
        RECT 0.000 510.040 4.000 510.640 ;
    END
  END tag_in[91]
  PIN tag_in[92]
    DIRECTION INPUT ;
    USE SIGNAL ;
    ANTENNAGATEAREA 0.196500 ;
    PORT
      LAYER met3 ;
        RECT 0.000 469.240 4.000 469.840 ;
    END
  END tag_in[92]
  PIN tag_in[93]
    DIRECTION INPUT ;
    USE SIGNAL ;
    ANTENNAGATEAREA 0.196500 ;
    PORT
      LAYER met3 ;
        RECT 0.000 391.040 4.000 391.640 ;
    END
  END tag_in[93]
  PIN tag_in[94]
    DIRECTION INPUT ;
    USE SIGNAL ;
    ANTENNAGATEAREA 0.196500 ;
    PORT
      LAYER met3 ;
        RECT 0.000 472.640 4.000 473.240 ;
    END
  END tag_in[94]
  PIN tag_in[95]
    DIRECTION INPUT ;
    USE SIGNAL ;
    ANTENNAGATEAREA 0.196500 ;
    PORT
      LAYER met3 ;
        RECT 0.000 482.840 4.000 483.440 ;
    END
  END tag_in[95]
  PIN tag_in[96]
    DIRECTION INPUT ;
    USE SIGNAL ;
    ANTENNAGATEAREA 0.196500 ;
    PORT
      LAYER met3 ;
        RECT 0.000 455.640 4.000 456.240 ;
    END
  END tag_in[96]
  PIN tag_in[97]
    DIRECTION INPUT ;
    USE SIGNAL ;
    ANTENNAGATEAREA 0.196500 ;
    PORT
      LAYER met3 ;
        RECT 0.000 459.040 4.000 459.640 ;
    END
  END tag_in[97]
  PIN tag_in[98]
    DIRECTION INPUT ;
    USE SIGNAL ;
    ANTENNAGATEAREA 0.196500 ;
    PORT
      LAYER met3 ;
        RECT 0.000 363.840 4.000 364.440 ;
    END
  END tag_in[98]
  PIN tag_in[99]
    DIRECTION INPUT ;
    USE SIGNAL ;
    ANTENNAGATEAREA 0.196500 ;
    PORT
      LAYER met3 ;
        RECT 0.000 326.440 4.000 327.040 ;
    END
  END tag_in[99]
  PIN tag_in[9]
    DIRECTION INPUT ;
    USE SIGNAL ;
    ANTENNAGATEAREA 0.196500 ;
    PORT
      LAYER met3 ;
        RECT 0.000 595.040 4.000 595.640 ;
    END
  END tag_in[9]
  PIN valid
    DIRECTION OUTPUT ;
    USE SIGNAL ;
    ANTENNADIFFAREA 0.445500 ;
    PORT
      LAYER met3 ;
        RECT 0.000 333.240 4.000 333.840 ;
    END
  END valid
  OBS
      LAYER nwell ;
        RECT 5.330 10.795 844.290 837.845 ;
      LAYER li1 ;
        RECT 5.520 10.795 844.100 837.845 ;
      LAYER met1 ;
        RECT 0.070 7.520 847.250 839.760 ;
      LAYER met2 ;
        RECT 0.100 845.720 205.890 847.125 ;
        RECT 206.730 845.720 209.110 847.125 ;
        RECT 209.950 845.720 212.330 847.125 ;
        RECT 213.170 845.720 215.550 847.125 ;
        RECT 216.390 845.720 218.770 847.125 ;
        RECT 219.610 845.720 221.990 847.125 ;
        RECT 222.830 845.720 225.210 847.125 ;
        RECT 226.050 845.720 228.430 847.125 ;
        RECT 229.270 845.720 231.650 847.125 ;
        RECT 232.490 845.720 234.870 847.125 ;
        RECT 235.710 845.720 238.090 847.125 ;
        RECT 238.930 845.720 241.310 847.125 ;
        RECT 242.150 845.720 244.530 847.125 ;
        RECT 245.370 845.720 247.750 847.125 ;
        RECT 248.590 845.720 250.970 847.125 ;
        RECT 251.810 845.720 254.190 847.125 ;
        RECT 255.030 845.720 257.410 847.125 ;
        RECT 258.250 845.720 260.630 847.125 ;
        RECT 261.470 845.720 263.850 847.125 ;
        RECT 264.690 845.720 267.070 847.125 ;
        RECT 267.910 845.720 270.290 847.125 ;
        RECT 271.130 845.720 273.510 847.125 ;
        RECT 274.350 845.720 276.730 847.125 ;
        RECT 277.570 845.720 279.950 847.125 ;
        RECT 280.790 845.720 283.170 847.125 ;
        RECT 284.010 845.720 286.390 847.125 ;
        RECT 287.230 845.720 289.610 847.125 ;
        RECT 290.450 845.720 292.830 847.125 ;
        RECT 293.670 845.720 296.050 847.125 ;
        RECT 296.890 845.720 299.270 847.125 ;
        RECT 300.110 845.720 302.490 847.125 ;
        RECT 303.330 845.720 305.710 847.125 ;
        RECT 306.550 845.720 308.930 847.125 ;
        RECT 309.770 845.720 312.150 847.125 ;
        RECT 312.990 845.720 315.370 847.125 ;
        RECT 316.210 845.720 318.590 847.125 ;
        RECT 319.430 845.720 321.810 847.125 ;
        RECT 322.650 845.720 325.030 847.125 ;
        RECT 325.870 845.720 328.250 847.125 ;
        RECT 329.090 845.720 331.470 847.125 ;
        RECT 332.310 845.720 334.690 847.125 ;
        RECT 335.530 845.720 337.910 847.125 ;
        RECT 338.750 845.720 341.130 847.125 ;
        RECT 341.970 845.720 344.350 847.125 ;
        RECT 345.190 845.720 347.570 847.125 ;
        RECT 348.410 845.720 350.790 847.125 ;
        RECT 351.630 845.720 354.010 847.125 ;
        RECT 354.850 845.720 357.230 847.125 ;
        RECT 358.070 845.720 360.450 847.125 ;
        RECT 361.290 845.720 363.670 847.125 ;
        RECT 364.510 845.720 366.890 847.125 ;
        RECT 367.730 845.720 370.110 847.125 ;
        RECT 370.950 845.720 373.330 847.125 ;
        RECT 374.170 845.720 376.550 847.125 ;
        RECT 377.390 845.720 379.770 847.125 ;
        RECT 380.610 845.720 382.990 847.125 ;
        RECT 383.830 845.720 386.210 847.125 ;
        RECT 387.050 845.720 389.430 847.125 ;
        RECT 390.270 845.720 392.650 847.125 ;
        RECT 393.490 845.720 395.870 847.125 ;
        RECT 396.710 845.720 399.090 847.125 ;
        RECT 399.930 845.720 402.310 847.125 ;
        RECT 403.150 845.720 405.530 847.125 ;
        RECT 406.370 845.720 408.750 847.125 ;
        RECT 409.590 845.720 411.970 847.125 ;
        RECT 412.810 845.720 415.190 847.125 ;
        RECT 416.030 845.720 418.410 847.125 ;
        RECT 419.250 845.720 421.630 847.125 ;
        RECT 422.470 845.720 424.850 847.125 ;
        RECT 425.690 845.720 428.070 847.125 ;
        RECT 428.910 845.720 431.290 847.125 ;
        RECT 432.130 845.720 434.510 847.125 ;
        RECT 435.350 845.720 437.730 847.125 ;
        RECT 438.570 845.720 440.950 847.125 ;
        RECT 441.790 845.720 444.170 847.125 ;
        RECT 445.010 845.720 447.390 847.125 ;
        RECT 448.230 845.720 450.610 847.125 ;
        RECT 451.450 845.720 453.830 847.125 ;
        RECT 454.670 845.720 457.050 847.125 ;
        RECT 457.890 845.720 460.270 847.125 ;
        RECT 461.110 845.720 463.490 847.125 ;
        RECT 464.330 845.720 466.710 847.125 ;
        RECT 467.550 845.720 469.930 847.125 ;
        RECT 470.770 845.720 473.150 847.125 ;
        RECT 473.990 845.720 476.370 847.125 ;
        RECT 477.210 845.720 479.590 847.125 ;
        RECT 480.430 845.720 482.810 847.125 ;
        RECT 483.650 845.720 486.030 847.125 ;
        RECT 486.870 845.720 489.250 847.125 ;
        RECT 490.090 845.720 492.470 847.125 ;
        RECT 493.310 845.720 495.690 847.125 ;
        RECT 496.530 845.720 498.910 847.125 ;
        RECT 499.750 845.720 502.130 847.125 ;
        RECT 502.970 845.720 505.350 847.125 ;
        RECT 506.190 845.720 508.570 847.125 ;
        RECT 509.410 845.720 511.790 847.125 ;
        RECT 512.630 845.720 515.010 847.125 ;
        RECT 515.850 845.720 518.230 847.125 ;
        RECT 519.070 845.720 521.450 847.125 ;
        RECT 522.290 845.720 524.670 847.125 ;
        RECT 525.510 845.720 527.890 847.125 ;
        RECT 528.730 845.720 531.110 847.125 ;
        RECT 531.950 845.720 534.330 847.125 ;
        RECT 535.170 845.720 537.550 847.125 ;
        RECT 538.390 845.720 540.770 847.125 ;
        RECT 541.610 845.720 543.990 847.125 ;
        RECT 544.830 845.720 547.210 847.125 ;
        RECT 548.050 845.720 550.430 847.125 ;
        RECT 551.270 845.720 553.650 847.125 ;
        RECT 554.490 845.720 556.870 847.125 ;
        RECT 557.710 845.720 560.090 847.125 ;
        RECT 560.930 845.720 563.310 847.125 ;
        RECT 564.150 845.720 566.530 847.125 ;
        RECT 567.370 845.720 569.750 847.125 ;
        RECT 570.590 845.720 572.970 847.125 ;
        RECT 573.810 845.720 576.190 847.125 ;
        RECT 577.030 845.720 579.410 847.125 ;
        RECT 580.250 845.720 582.630 847.125 ;
        RECT 583.470 845.720 585.850 847.125 ;
        RECT 586.690 845.720 589.070 847.125 ;
        RECT 589.910 845.720 592.290 847.125 ;
        RECT 593.130 845.720 595.510 847.125 ;
        RECT 596.350 845.720 598.730 847.125 ;
        RECT 599.570 845.720 601.950 847.125 ;
        RECT 602.790 845.720 605.170 847.125 ;
        RECT 606.010 845.720 608.390 847.125 ;
        RECT 609.230 845.720 611.610 847.125 ;
        RECT 612.450 845.720 614.830 847.125 ;
        RECT 615.670 845.720 618.050 847.125 ;
        RECT 618.890 845.720 621.270 847.125 ;
        RECT 622.110 845.720 624.490 847.125 ;
        RECT 625.330 845.720 627.710 847.125 ;
        RECT 628.550 845.720 630.930 847.125 ;
        RECT 631.770 845.720 634.150 847.125 ;
        RECT 634.990 845.720 637.370 847.125 ;
        RECT 638.210 845.720 640.590 847.125 ;
        RECT 641.430 845.720 643.810 847.125 ;
        RECT 644.650 845.720 647.030 847.125 ;
        RECT 647.870 845.720 650.250 847.125 ;
        RECT 651.090 845.720 653.470 847.125 ;
        RECT 654.310 845.720 656.690 847.125 ;
        RECT 657.530 845.720 659.910 847.125 ;
        RECT 660.750 845.720 663.130 847.125 ;
        RECT 663.970 845.720 666.350 847.125 ;
        RECT 667.190 845.720 669.570 847.125 ;
        RECT 670.410 845.720 672.790 847.125 ;
        RECT 673.630 845.720 676.010 847.125 ;
        RECT 676.850 845.720 679.230 847.125 ;
        RECT 680.070 845.720 682.450 847.125 ;
        RECT 683.290 845.720 685.670 847.125 ;
        RECT 686.510 845.720 688.890 847.125 ;
        RECT 689.730 845.720 692.110 847.125 ;
        RECT 692.950 845.720 695.330 847.125 ;
        RECT 696.170 845.720 698.550 847.125 ;
        RECT 699.390 845.720 701.770 847.125 ;
        RECT 702.610 845.720 704.990 847.125 ;
        RECT 705.830 845.720 708.210 847.125 ;
        RECT 709.050 845.720 711.430 847.125 ;
        RECT 712.270 845.720 714.650 847.125 ;
        RECT 715.490 845.720 717.870 847.125 ;
        RECT 718.710 845.720 721.090 847.125 ;
        RECT 721.930 845.720 724.310 847.125 ;
        RECT 725.150 845.720 727.530 847.125 ;
        RECT 728.370 845.720 730.750 847.125 ;
        RECT 731.590 845.720 733.970 847.125 ;
        RECT 734.810 845.720 737.190 847.125 ;
        RECT 738.030 845.720 740.410 847.125 ;
        RECT 741.250 845.720 743.630 847.125 ;
        RECT 744.470 845.720 746.850 847.125 ;
        RECT 747.690 845.720 750.070 847.125 ;
        RECT 750.910 845.720 753.290 847.125 ;
        RECT 754.130 845.720 756.510 847.125 ;
        RECT 757.350 845.720 759.730 847.125 ;
        RECT 760.570 845.720 762.950 847.125 ;
        RECT 763.790 845.720 766.170 847.125 ;
        RECT 767.010 845.720 769.390 847.125 ;
        RECT 770.230 845.720 772.610 847.125 ;
        RECT 773.450 845.720 775.830 847.125 ;
        RECT 776.670 845.720 779.050 847.125 ;
        RECT 779.890 845.720 782.270 847.125 ;
        RECT 783.110 845.720 785.490 847.125 ;
        RECT 786.330 845.720 788.710 847.125 ;
        RECT 789.550 845.720 791.930 847.125 ;
        RECT 792.770 845.720 795.150 847.125 ;
        RECT 795.990 845.720 798.370 847.125 ;
        RECT 799.210 845.720 801.590 847.125 ;
        RECT 802.430 845.720 804.810 847.125 ;
        RECT 805.650 845.720 808.030 847.125 ;
        RECT 808.870 845.720 811.250 847.125 ;
        RECT 812.090 845.720 814.470 847.125 ;
        RECT 815.310 845.720 817.690 847.125 ;
        RECT 818.530 845.720 820.910 847.125 ;
        RECT 821.750 845.720 824.130 847.125 ;
        RECT 824.970 845.720 827.350 847.125 ;
        RECT 828.190 845.720 830.570 847.125 ;
        RECT 831.410 845.720 833.790 847.125 ;
        RECT 834.630 845.720 837.010 847.125 ;
        RECT 837.850 845.720 840.230 847.125 ;
        RECT 841.070 845.720 843.450 847.125 ;
        RECT 844.290 845.720 846.670 847.125 ;
        RECT 0.100 4.280 847.220 845.720 ;
        RECT 0.650 0.155 3.030 4.280 ;
        RECT 3.870 0.155 6.250 4.280 ;
        RECT 7.090 0.155 9.470 4.280 ;
        RECT 10.310 0.155 12.690 4.280 ;
        RECT 13.530 0.155 15.910 4.280 ;
        RECT 16.750 0.155 19.130 4.280 ;
        RECT 19.970 0.155 22.350 4.280 ;
        RECT 23.190 0.155 25.570 4.280 ;
        RECT 26.410 0.155 28.790 4.280 ;
        RECT 29.630 0.155 32.010 4.280 ;
        RECT 32.850 0.155 35.230 4.280 ;
        RECT 36.070 0.155 38.450 4.280 ;
        RECT 39.290 0.155 41.670 4.280 ;
        RECT 42.510 0.155 44.890 4.280 ;
        RECT 45.730 0.155 48.110 4.280 ;
        RECT 48.950 0.155 51.330 4.280 ;
        RECT 52.170 0.155 54.550 4.280 ;
        RECT 55.390 0.155 57.770 4.280 ;
        RECT 58.610 0.155 60.990 4.280 ;
        RECT 61.830 0.155 64.210 4.280 ;
        RECT 65.050 0.155 67.430 4.280 ;
        RECT 68.270 0.155 70.650 4.280 ;
        RECT 71.490 0.155 73.870 4.280 ;
        RECT 74.710 0.155 77.090 4.280 ;
        RECT 77.930 0.155 80.310 4.280 ;
        RECT 81.150 0.155 83.530 4.280 ;
        RECT 84.370 0.155 86.750 4.280 ;
        RECT 87.590 0.155 89.970 4.280 ;
        RECT 90.810 0.155 93.190 4.280 ;
        RECT 94.030 0.155 96.410 4.280 ;
        RECT 97.250 0.155 99.630 4.280 ;
        RECT 100.470 0.155 102.850 4.280 ;
        RECT 103.690 0.155 106.070 4.280 ;
        RECT 106.910 0.155 109.290 4.280 ;
        RECT 110.130 0.155 112.510 4.280 ;
        RECT 113.350 0.155 115.730 4.280 ;
        RECT 116.570 0.155 118.950 4.280 ;
        RECT 119.790 0.155 122.170 4.280 ;
        RECT 123.010 0.155 125.390 4.280 ;
        RECT 126.230 0.155 128.610 4.280 ;
        RECT 129.450 0.155 131.830 4.280 ;
        RECT 132.670 0.155 135.050 4.280 ;
        RECT 135.890 0.155 138.270 4.280 ;
        RECT 139.110 0.155 141.490 4.280 ;
        RECT 142.330 0.155 144.710 4.280 ;
        RECT 145.550 0.155 147.930 4.280 ;
        RECT 148.770 0.155 151.150 4.280 ;
        RECT 151.990 0.155 154.370 4.280 ;
        RECT 155.210 0.155 157.590 4.280 ;
        RECT 158.430 0.155 160.810 4.280 ;
        RECT 161.650 0.155 164.030 4.280 ;
        RECT 164.870 0.155 167.250 4.280 ;
        RECT 168.090 0.155 170.470 4.280 ;
        RECT 171.310 0.155 173.690 4.280 ;
        RECT 174.530 0.155 176.910 4.280 ;
        RECT 177.750 0.155 180.130 4.280 ;
        RECT 180.970 0.155 183.350 4.280 ;
        RECT 184.190 0.155 186.570 4.280 ;
        RECT 187.410 0.155 189.790 4.280 ;
        RECT 190.630 0.155 193.010 4.280 ;
        RECT 193.850 0.155 196.230 4.280 ;
        RECT 197.070 0.155 199.450 4.280 ;
        RECT 200.290 0.155 202.670 4.280 ;
        RECT 203.510 0.155 205.890 4.280 ;
        RECT 206.730 0.155 209.110 4.280 ;
        RECT 209.950 0.155 212.330 4.280 ;
        RECT 213.170 0.155 215.550 4.280 ;
        RECT 216.390 0.155 218.770 4.280 ;
        RECT 219.610 0.155 221.990 4.280 ;
        RECT 222.830 0.155 225.210 4.280 ;
        RECT 226.050 0.155 228.430 4.280 ;
        RECT 229.270 0.155 231.650 4.280 ;
        RECT 232.490 0.155 234.870 4.280 ;
        RECT 235.710 0.155 238.090 4.280 ;
        RECT 238.930 0.155 241.310 4.280 ;
        RECT 242.150 0.155 244.530 4.280 ;
        RECT 245.370 0.155 247.750 4.280 ;
        RECT 248.590 0.155 250.970 4.280 ;
        RECT 251.810 0.155 254.190 4.280 ;
        RECT 255.030 0.155 257.410 4.280 ;
        RECT 258.250 0.155 260.630 4.280 ;
        RECT 261.470 0.155 263.850 4.280 ;
        RECT 264.690 0.155 267.070 4.280 ;
        RECT 267.910 0.155 270.290 4.280 ;
        RECT 271.130 0.155 273.510 4.280 ;
        RECT 274.350 0.155 276.730 4.280 ;
        RECT 277.570 0.155 279.950 4.280 ;
        RECT 280.790 0.155 283.170 4.280 ;
        RECT 284.010 0.155 286.390 4.280 ;
        RECT 287.230 0.155 289.610 4.280 ;
        RECT 290.450 0.155 292.830 4.280 ;
        RECT 293.670 0.155 296.050 4.280 ;
        RECT 296.890 0.155 299.270 4.280 ;
        RECT 300.110 0.155 302.490 4.280 ;
        RECT 303.330 0.155 305.710 4.280 ;
        RECT 306.550 0.155 308.930 4.280 ;
        RECT 309.770 0.155 312.150 4.280 ;
        RECT 312.990 0.155 315.370 4.280 ;
        RECT 316.210 0.155 318.590 4.280 ;
        RECT 319.430 0.155 321.810 4.280 ;
        RECT 322.650 0.155 325.030 4.280 ;
        RECT 325.870 0.155 328.250 4.280 ;
        RECT 329.090 0.155 331.470 4.280 ;
        RECT 332.310 0.155 334.690 4.280 ;
        RECT 335.530 0.155 337.910 4.280 ;
        RECT 338.750 0.155 341.130 4.280 ;
        RECT 341.970 0.155 344.350 4.280 ;
        RECT 345.190 0.155 347.570 4.280 ;
        RECT 348.410 0.155 350.790 4.280 ;
        RECT 351.630 0.155 354.010 4.280 ;
        RECT 354.850 0.155 357.230 4.280 ;
        RECT 358.070 0.155 360.450 4.280 ;
        RECT 361.290 0.155 363.670 4.280 ;
        RECT 364.510 0.155 366.890 4.280 ;
        RECT 367.730 0.155 370.110 4.280 ;
        RECT 370.950 0.155 373.330 4.280 ;
        RECT 374.170 0.155 376.550 4.280 ;
        RECT 377.390 0.155 379.770 4.280 ;
        RECT 380.610 0.155 382.990 4.280 ;
        RECT 383.830 0.155 386.210 4.280 ;
        RECT 387.050 0.155 389.430 4.280 ;
        RECT 390.270 0.155 392.650 4.280 ;
        RECT 393.490 0.155 395.870 4.280 ;
        RECT 396.710 0.155 399.090 4.280 ;
        RECT 399.930 0.155 402.310 4.280 ;
        RECT 403.150 0.155 405.530 4.280 ;
        RECT 406.370 0.155 408.750 4.280 ;
        RECT 409.590 0.155 411.970 4.280 ;
        RECT 412.810 0.155 415.190 4.280 ;
        RECT 416.030 0.155 418.410 4.280 ;
        RECT 419.250 0.155 421.630 4.280 ;
        RECT 422.470 0.155 424.850 4.280 ;
        RECT 425.690 0.155 428.070 4.280 ;
        RECT 428.910 0.155 431.290 4.280 ;
        RECT 432.130 0.155 434.510 4.280 ;
        RECT 435.350 0.155 437.730 4.280 ;
        RECT 438.570 0.155 440.950 4.280 ;
        RECT 441.790 0.155 444.170 4.280 ;
        RECT 445.010 0.155 447.390 4.280 ;
        RECT 448.230 0.155 450.610 4.280 ;
        RECT 451.450 0.155 453.830 4.280 ;
        RECT 454.670 0.155 457.050 4.280 ;
        RECT 457.890 0.155 460.270 4.280 ;
        RECT 461.110 0.155 463.490 4.280 ;
        RECT 464.330 0.155 466.710 4.280 ;
        RECT 467.550 0.155 469.930 4.280 ;
        RECT 470.770 0.155 473.150 4.280 ;
        RECT 473.990 0.155 476.370 4.280 ;
        RECT 477.210 0.155 479.590 4.280 ;
        RECT 480.430 0.155 482.810 4.280 ;
        RECT 483.650 0.155 486.030 4.280 ;
        RECT 486.870 0.155 489.250 4.280 ;
        RECT 490.090 0.155 492.470 4.280 ;
        RECT 493.310 0.155 495.690 4.280 ;
        RECT 496.530 0.155 498.910 4.280 ;
        RECT 499.750 0.155 502.130 4.280 ;
        RECT 502.970 0.155 505.350 4.280 ;
        RECT 506.190 0.155 508.570 4.280 ;
        RECT 509.410 0.155 511.790 4.280 ;
        RECT 512.630 0.155 515.010 4.280 ;
        RECT 515.850 0.155 518.230 4.280 ;
        RECT 519.070 0.155 521.450 4.280 ;
        RECT 522.290 0.155 524.670 4.280 ;
        RECT 525.510 0.155 527.890 4.280 ;
        RECT 528.730 0.155 531.110 4.280 ;
        RECT 531.950 0.155 534.330 4.280 ;
        RECT 535.170 0.155 537.550 4.280 ;
        RECT 538.390 0.155 540.770 4.280 ;
        RECT 541.610 0.155 543.990 4.280 ;
        RECT 544.830 0.155 547.210 4.280 ;
        RECT 548.050 0.155 550.430 4.280 ;
        RECT 551.270 0.155 553.650 4.280 ;
        RECT 554.490 0.155 556.870 4.280 ;
        RECT 557.710 0.155 560.090 4.280 ;
        RECT 560.930 0.155 563.310 4.280 ;
        RECT 564.150 0.155 566.530 4.280 ;
        RECT 567.370 0.155 569.750 4.280 ;
        RECT 570.590 0.155 572.970 4.280 ;
        RECT 573.810 0.155 576.190 4.280 ;
        RECT 577.030 0.155 579.410 4.280 ;
        RECT 580.250 0.155 582.630 4.280 ;
        RECT 583.470 0.155 585.850 4.280 ;
        RECT 586.690 0.155 589.070 4.280 ;
        RECT 589.910 0.155 592.290 4.280 ;
        RECT 593.130 0.155 595.510 4.280 ;
        RECT 596.350 0.155 598.730 4.280 ;
        RECT 599.570 0.155 601.950 4.280 ;
        RECT 602.790 0.155 605.170 4.280 ;
        RECT 606.010 0.155 608.390 4.280 ;
        RECT 609.230 0.155 611.610 4.280 ;
        RECT 612.450 0.155 614.830 4.280 ;
        RECT 615.670 0.155 618.050 4.280 ;
        RECT 618.890 0.155 621.270 4.280 ;
        RECT 622.110 0.155 624.490 4.280 ;
        RECT 625.330 0.155 627.710 4.280 ;
        RECT 628.550 0.155 630.930 4.280 ;
        RECT 631.770 0.155 634.150 4.280 ;
        RECT 634.990 0.155 637.370 4.280 ;
        RECT 638.210 0.155 640.590 4.280 ;
        RECT 641.430 0.155 643.810 4.280 ;
        RECT 644.650 0.155 647.030 4.280 ;
        RECT 647.870 0.155 650.250 4.280 ;
        RECT 651.090 0.155 653.470 4.280 ;
        RECT 654.310 0.155 656.690 4.280 ;
        RECT 657.530 0.155 659.910 4.280 ;
        RECT 660.750 0.155 663.130 4.280 ;
        RECT 663.970 0.155 666.350 4.280 ;
        RECT 667.190 0.155 669.570 4.280 ;
        RECT 670.410 0.155 672.790 4.280 ;
        RECT 673.630 0.155 676.010 4.280 ;
        RECT 676.850 0.155 679.230 4.280 ;
        RECT 680.070 0.155 682.450 4.280 ;
        RECT 683.290 0.155 685.670 4.280 ;
        RECT 686.510 0.155 688.890 4.280 ;
        RECT 689.730 0.155 692.110 4.280 ;
        RECT 692.950 0.155 695.330 4.280 ;
        RECT 696.170 0.155 698.550 4.280 ;
        RECT 699.390 0.155 701.770 4.280 ;
        RECT 702.610 0.155 704.990 4.280 ;
        RECT 705.830 0.155 708.210 4.280 ;
        RECT 709.050 0.155 711.430 4.280 ;
        RECT 712.270 0.155 714.650 4.280 ;
        RECT 715.490 0.155 717.870 4.280 ;
        RECT 718.710 0.155 721.090 4.280 ;
        RECT 721.930 0.155 724.310 4.280 ;
        RECT 725.150 0.155 727.530 4.280 ;
        RECT 728.370 0.155 730.750 4.280 ;
        RECT 731.590 0.155 733.970 4.280 ;
        RECT 734.810 0.155 737.190 4.280 ;
        RECT 738.030 0.155 740.410 4.280 ;
        RECT 741.250 0.155 743.630 4.280 ;
        RECT 744.470 0.155 746.850 4.280 ;
        RECT 747.690 0.155 750.070 4.280 ;
        RECT 750.910 0.155 753.290 4.280 ;
        RECT 754.130 0.155 756.510 4.280 ;
        RECT 757.350 0.155 759.730 4.280 ;
        RECT 760.570 0.155 762.950 4.280 ;
        RECT 763.790 0.155 766.170 4.280 ;
        RECT 767.010 0.155 769.390 4.280 ;
        RECT 770.230 0.155 772.610 4.280 ;
        RECT 773.450 0.155 775.830 4.280 ;
        RECT 776.670 0.155 779.050 4.280 ;
        RECT 779.890 0.155 782.270 4.280 ;
        RECT 783.110 0.155 785.490 4.280 ;
        RECT 786.330 0.155 788.710 4.280 ;
        RECT 789.550 0.155 791.930 4.280 ;
        RECT 792.770 0.155 795.150 4.280 ;
        RECT 795.990 0.155 798.370 4.280 ;
        RECT 799.210 0.155 801.590 4.280 ;
        RECT 802.430 0.155 804.810 4.280 ;
        RECT 805.650 0.155 808.030 4.280 ;
        RECT 808.870 0.155 811.250 4.280 ;
        RECT 812.090 0.155 814.470 4.280 ;
        RECT 815.310 0.155 817.690 4.280 ;
        RECT 818.530 0.155 820.910 4.280 ;
        RECT 821.750 0.155 824.130 4.280 ;
        RECT 824.970 0.155 827.350 4.280 ;
        RECT 828.190 0.155 830.570 4.280 ;
        RECT 831.410 0.155 833.790 4.280 ;
        RECT 834.630 0.155 837.010 4.280 ;
        RECT 837.850 0.155 840.230 4.280 ;
        RECT 841.070 0.155 843.450 4.280 ;
        RECT 844.290 0.155 846.670 4.280 ;
      LAYER met3 ;
        RECT 3.750 846.240 845.600 847.105 ;
        RECT 3.750 844.240 846.000 846.240 ;
        RECT 3.750 842.840 845.600 844.240 ;
        RECT 3.750 840.840 846.000 842.840 ;
        RECT 3.750 839.440 845.600 840.840 ;
        RECT 3.750 837.440 846.000 839.440 ;
        RECT 3.750 836.040 845.600 837.440 ;
        RECT 3.750 834.040 846.000 836.040 ;
        RECT 3.750 832.640 845.600 834.040 ;
        RECT 3.750 830.640 846.000 832.640 ;
        RECT 3.750 829.240 845.600 830.640 ;
        RECT 3.750 827.240 846.000 829.240 ;
        RECT 3.750 825.840 845.600 827.240 ;
        RECT 3.750 823.840 846.000 825.840 ;
        RECT 3.750 822.440 845.600 823.840 ;
        RECT 3.750 820.440 846.000 822.440 ;
        RECT 3.750 819.040 845.600 820.440 ;
        RECT 3.750 817.040 846.000 819.040 ;
        RECT 3.750 815.640 845.600 817.040 ;
        RECT 3.750 813.640 846.000 815.640 ;
        RECT 3.750 812.240 845.600 813.640 ;
        RECT 3.750 810.240 846.000 812.240 ;
        RECT 3.750 808.840 845.600 810.240 ;
        RECT 3.750 806.840 846.000 808.840 ;
        RECT 3.750 805.440 845.600 806.840 ;
        RECT 3.750 803.440 846.000 805.440 ;
        RECT 3.750 802.040 845.600 803.440 ;
        RECT 3.750 800.040 846.000 802.040 ;
        RECT 3.750 798.640 845.600 800.040 ;
        RECT 3.750 796.640 846.000 798.640 ;
        RECT 3.750 795.240 845.600 796.640 ;
        RECT 3.750 793.240 846.000 795.240 ;
        RECT 3.750 791.840 845.600 793.240 ;
        RECT 3.750 789.840 846.000 791.840 ;
        RECT 3.750 788.440 845.600 789.840 ;
        RECT 3.750 786.440 846.000 788.440 ;
        RECT 3.750 785.040 845.600 786.440 ;
        RECT 3.750 783.040 846.000 785.040 ;
        RECT 3.750 781.640 845.600 783.040 ;
        RECT 3.750 779.640 846.000 781.640 ;
        RECT 3.750 778.240 845.600 779.640 ;
        RECT 3.750 776.240 846.000 778.240 ;
        RECT 4.400 774.840 845.600 776.240 ;
        RECT 3.750 772.840 846.000 774.840 ;
        RECT 4.400 771.440 845.600 772.840 ;
        RECT 3.750 769.440 846.000 771.440 ;
        RECT 4.400 768.040 845.600 769.440 ;
        RECT 3.750 766.040 846.000 768.040 ;
        RECT 4.400 764.640 845.600 766.040 ;
        RECT 3.750 762.640 846.000 764.640 ;
        RECT 4.400 761.240 845.600 762.640 ;
        RECT 3.750 759.240 846.000 761.240 ;
        RECT 4.400 757.840 845.600 759.240 ;
        RECT 3.750 755.840 846.000 757.840 ;
        RECT 4.400 754.440 845.600 755.840 ;
        RECT 3.750 752.440 846.000 754.440 ;
        RECT 4.400 751.040 845.600 752.440 ;
        RECT 3.750 749.040 846.000 751.040 ;
        RECT 4.400 747.640 845.600 749.040 ;
        RECT 3.750 745.640 846.000 747.640 ;
        RECT 4.400 744.240 845.600 745.640 ;
        RECT 3.750 742.240 846.000 744.240 ;
        RECT 4.400 740.840 845.600 742.240 ;
        RECT 3.750 738.840 846.000 740.840 ;
        RECT 4.400 737.440 845.600 738.840 ;
        RECT 3.750 735.440 846.000 737.440 ;
        RECT 4.400 734.040 845.600 735.440 ;
        RECT 3.750 732.040 846.000 734.040 ;
        RECT 4.400 730.640 845.600 732.040 ;
        RECT 3.750 728.640 846.000 730.640 ;
        RECT 4.400 727.240 845.600 728.640 ;
        RECT 3.750 725.240 846.000 727.240 ;
        RECT 4.400 723.840 845.600 725.240 ;
        RECT 3.750 721.840 846.000 723.840 ;
        RECT 4.400 720.440 845.600 721.840 ;
        RECT 3.750 718.440 846.000 720.440 ;
        RECT 4.400 717.040 845.600 718.440 ;
        RECT 3.750 715.040 846.000 717.040 ;
        RECT 4.400 713.640 845.600 715.040 ;
        RECT 3.750 711.640 846.000 713.640 ;
        RECT 4.400 710.240 845.600 711.640 ;
        RECT 3.750 708.240 846.000 710.240 ;
        RECT 4.400 706.840 845.600 708.240 ;
        RECT 3.750 704.840 846.000 706.840 ;
        RECT 4.400 703.440 845.600 704.840 ;
        RECT 3.750 701.440 846.000 703.440 ;
        RECT 4.400 700.040 845.600 701.440 ;
        RECT 3.750 698.040 846.000 700.040 ;
        RECT 4.400 696.640 845.600 698.040 ;
        RECT 3.750 694.640 846.000 696.640 ;
        RECT 4.400 693.240 845.600 694.640 ;
        RECT 3.750 691.240 846.000 693.240 ;
        RECT 4.400 689.840 845.600 691.240 ;
        RECT 3.750 687.840 846.000 689.840 ;
        RECT 4.400 686.440 845.600 687.840 ;
        RECT 3.750 684.440 846.000 686.440 ;
        RECT 4.400 683.040 845.600 684.440 ;
        RECT 3.750 681.040 846.000 683.040 ;
        RECT 4.400 679.640 845.600 681.040 ;
        RECT 3.750 677.640 846.000 679.640 ;
        RECT 4.400 676.240 845.600 677.640 ;
        RECT 3.750 674.240 846.000 676.240 ;
        RECT 4.400 672.840 845.600 674.240 ;
        RECT 3.750 670.840 846.000 672.840 ;
        RECT 4.400 669.440 845.600 670.840 ;
        RECT 3.750 667.440 846.000 669.440 ;
        RECT 4.400 666.040 845.600 667.440 ;
        RECT 3.750 664.040 846.000 666.040 ;
        RECT 4.400 662.640 845.600 664.040 ;
        RECT 3.750 660.640 846.000 662.640 ;
        RECT 4.400 659.240 845.600 660.640 ;
        RECT 3.750 657.240 846.000 659.240 ;
        RECT 4.400 655.840 845.600 657.240 ;
        RECT 3.750 653.840 846.000 655.840 ;
        RECT 4.400 652.440 845.600 653.840 ;
        RECT 3.750 650.440 846.000 652.440 ;
        RECT 4.400 649.040 845.600 650.440 ;
        RECT 3.750 647.040 846.000 649.040 ;
        RECT 4.400 645.640 845.600 647.040 ;
        RECT 3.750 643.640 846.000 645.640 ;
        RECT 4.400 642.240 845.600 643.640 ;
        RECT 3.750 640.240 846.000 642.240 ;
        RECT 4.400 638.840 845.600 640.240 ;
        RECT 3.750 636.840 846.000 638.840 ;
        RECT 4.400 635.440 845.600 636.840 ;
        RECT 3.750 633.440 846.000 635.440 ;
        RECT 4.400 632.040 845.600 633.440 ;
        RECT 3.750 630.040 846.000 632.040 ;
        RECT 4.400 628.640 845.600 630.040 ;
        RECT 3.750 626.640 846.000 628.640 ;
        RECT 4.400 625.240 845.600 626.640 ;
        RECT 3.750 623.240 846.000 625.240 ;
        RECT 4.400 621.840 845.600 623.240 ;
        RECT 3.750 619.840 846.000 621.840 ;
        RECT 4.400 618.440 845.600 619.840 ;
        RECT 3.750 616.440 846.000 618.440 ;
        RECT 4.400 615.040 845.600 616.440 ;
        RECT 3.750 613.040 846.000 615.040 ;
        RECT 4.400 611.640 845.600 613.040 ;
        RECT 3.750 609.640 846.000 611.640 ;
        RECT 4.400 608.240 845.600 609.640 ;
        RECT 3.750 606.240 846.000 608.240 ;
        RECT 4.400 604.840 845.600 606.240 ;
        RECT 3.750 602.840 846.000 604.840 ;
        RECT 4.400 601.440 845.600 602.840 ;
        RECT 3.750 599.440 846.000 601.440 ;
        RECT 4.400 598.040 845.600 599.440 ;
        RECT 3.750 596.040 846.000 598.040 ;
        RECT 4.400 594.640 845.600 596.040 ;
        RECT 3.750 592.640 846.000 594.640 ;
        RECT 4.400 591.240 845.600 592.640 ;
        RECT 3.750 589.240 846.000 591.240 ;
        RECT 4.400 587.840 845.600 589.240 ;
        RECT 3.750 585.840 846.000 587.840 ;
        RECT 4.400 584.440 845.600 585.840 ;
        RECT 3.750 582.440 846.000 584.440 ;
        RECT 4.400 581.040 845.600 582.440 ;
        RECT 3.750 579.040 846.000 581.040 ;
        RECT 4.400 577.640 845.600 579.040 ;
        RECT 3.750 575.640 846.000 577.640 ;
        RECT 4.400 574.240 845.600 575.640 ;
        RECT 3.750 572.240 846.000 574.240 ;
        RECT 4.400 570.840 845.600 572.240 ;
        RECT 3.750 568.840 846.000 570.840 ;
        RECT 4.400 567.440 845.600 568.840 ;
        RECT 3.750 565.440 846.000 567.440 ;
        RECT 4.400 564.040 845.600 565.440 ;
        RECT 3.750 562.040 846.000 564.040 ;
        RECT 4.400 560.640 845.600 562.040 ;
        RECT 3.750 558.640 846.000 560.640 ;
        RECT 4.400 557.240 845.600 558.640 ;
        RECT 3.750 555.240 846.000 557.240 ;
        RECT 4.400 553.840 845.600 555.240 ;
        RECT 3.750 551.840 846.000 553.840 ;
        RECT 4.400 550.440 845.600 551.840 ;
        RECT 3.750 548.440 846.000 550.440 ;
        RECT 4.400 547.040 845.600 548.440 ;
        RECT 3.750 545.040 846.000 547.040 ;
        RECT 4.400 543.640 845.600 545.040 ;
        RECT 3.750 541.640 846.000 543.640 ;
        RECT 4.400 540.240 845.600 541.640 ;
        RECT 3.750 538.240 846.000 540.240 ;
        RECT 4.400 536.840 845.600 538.240 ;
        RECT 3.750 534.840 846.000 536.840 ;
        RECT 4.400 533.440 845.600 534.840 ;
        RECT 3.750 531.440 846.000 533.440 ;
        RECT 4.400 530.040 845.600 531.440 ;
        RECT 3.750 528.040 846.000 530.040 ;
        RECT 4.400 526.640 845.600 528.040 ;
        RECT 3.750 524.640 846.000 526.640 ;
        RECT 4.400 523.240 845.600 524.640 ;
        RECT 3.750 521.240 846.000 523.240 ;
        RECT 4.400 519.840 845.600 521.240 ;
        RECT 3.750 517.840 846.000 519.840 ;
        RECT 4.400 516.440 845.600 517.840 ;
        RECT 3.750 514.440 846.000 516.440 ;
        RECT 4.400 513.040 845.600 514.440 ;
        RECT 3.750 511.040 846.000 513.040 ;
        RECT 4.400 509.640 845.600 511.040 ;
        RECT 3.750 507.640 846.000 509.640 ;
        RECT 4.400 506.240 845.600 507.640 ;
        RECT 3.750 504.240 846.000 506.240 ;
        RECT 4.400 502.840 845.600 504.240 ;
        RECT 3.750 500.840 846.000 502.840 ;
        RECT 4.400 499.440 845.600 500.840 ;
        RECT 3.750 497.440 846.000 499.440 ;
        RECT 4.400 496.040 845.600 497.440 ;
        RECT 3.750 494.040 846.000 496.040 ;
        RECT 4.400 492.640 845.600 494.040 ;
        RECT 3.750 490.640 846.000 492.640 ;
        RECT 4.400 489.240 845.600 490.640 ;
        RECT 3.750 487.240 846.000 489.240 ;
        RECT 4.400 485.840 845.600 487.240 ;
        RECT 3.750 483.840 846.000 485.840 ;
        RECT 4.400 482.440 845.600 483.840 ;
        RECT 3.750 480.440 846.000 482.440 ;
        RECT 4.400 479.040 845.600 480.440 ;
        RECT 3.750 477.040 846.000 479.040 ;
        RECT 4.400 475.640 845.600 477.040 ;
        RECT 3.750 473.640 846.000 475.640 ;
        RECT 4.400 472.240 845.600 473.640 ;
        RECT 3.750 470.240 846.000 472.240 ;
        RECT 4.400 468.840 845.600 470.240 ;
        RECT 3.750 466.840 846.000 468.840 ;
        RECT 4.400 465.440 845.600 466.840 ;
        RECT 3.750 463.440 846.000 465.440 ;
        RECT 4.400 462.040 845.600 463.440 ;
        RECT 3.750 460.040 846.000 462.040 ;
        RECT 4.400 458.640 845.600 460.040 ;
        RECT 3.750 456.640 846.000 458.640 ;
        RECT 4.400 455.240 845.600 456.640 ;
        RECT 3.750 453.240 846.000 455.240 ;
        RECT 4.400 451.840 845.600 453.240 ;
        RECT 3.750 449.840 846.000 451.840 ;
        RECT 4.400 448.440 845.600 449.840 ;
        RECT 3.750 446.440 846.000 448.440 ;
        RECT 4.400 445.040 845.600 446.440 ;
        RECT 3.750 443.040 846.000 445.040 ;
        RECT 4.400 441.640 845.600 443.040 ;
        RECT 3.750 439.640 846.000 441.640 ;
        RECT 4.400 438.240 845.600 439.640 ;
        RECT 3.750 436.240 846.000 438.240 ;
        RECT 4.400 434.840 845.600 436.240 ;
        RECT 3.750 432.840 846.000 434.840 ;
        RECT 4.400 431.440 845.600 432.840 ;
        RECT 3.750 429.440 846.000 431.440 ;
        RECT 4.400 428.040 845.600 429.440 ;
        RECT 3.750 426.040 846.000 428.040 ;
        RECT 4.400 424.640 845.600 426.040 ;
        RECT 3.750 422.640 846.000 424.640 ;
        RECT 4.400 421.240 845.600 422.640 ;
        RECT 3.750 419.240 846.000 421.240 ;
        RECT 4.400 417.840 845.600 419.240 ;
        RECT 3.750 415.840 846.000 417.840 ;
        RECT 4.400 414.440 845.600 415.840 ;
        RECT 3.750 412.440 846.000 414.440 ;
        RECT 4.400 411.040 845.600 412.440 ;
        RECT 3.750 409.040 846.000 411.040 ;
        RECT 4.400 407.640 845.600 409.040 ;
        RECT 3.750 405.640 846.000 407.640 ;
        RECT 4.400 404.240 845.600 405.640 ;
        RECT 3.750 402.240 846.000 404.240 ;
        RECT 4.400 400.840 845.600 402.240 ;
        RECT 3.750 398.840 846.000 400.840 ;
        RECT 4.400 397.440 845.600 398.840 ;
        RECT 3.750 395.440 846.000 397.440 ;
        RECT 4.400 394.040 845.600 395.440 ;
        RECT 3.750 392.040 846.000 394.040 ;
        RECT 4.400 390.640 845.600 392.040 ;
        RECT 3.750 388.640 846.000 390.640 ;
        RECT 4.400 387.240 845.600 388.640 ;
        RECT 3.750 385.240 846.000 387.240 ;
        RECT 4.400 383.840 845.600 385.240 ;
        RECT 3.750 381.840 846.000 383.840 ;
        RECT 4.400 380.440 845.600 381.840 ;
        RECT 3.750 378.440 846.000 380.440 ;
        RECT 4.400 377.040 845.600 378.440 ;
        RECT 3.750 375.040 846.000 377.040 ;
        RECT 4.400 373.640 845.600 375.040 ;
        RECT 3.750 371.640 846.000 373.640 ;
        RECT 4.400 370.240 845.600 371.640 ;
        RECT 3.750 368.240 846.000 370.240 ;
        RECT 4.400 366.840 845.600 368.240 ;
        RECT 3.750 364.840 846.000 366.840 ;
        RECT 4.400 363.440 845.600 364.840 ;
        RECT 3.750 361.440 846.000 363.440 ;
        RECT 4.400 360.040 845.600 361.440 ;
        RECT 3.750 358.040 846.000 360.040 ;
        RECT 4.400 356.640 845.600 358.040 ;
        RECT 3.750 354.640 846.000 356.640 ;
        RECT 4.400 353.240 845.600 354.640 ;
        RECT 3.750 351.240 846.000 353.240 ;
        RECT 4.400 349.840 845.600 351.240 ;
        RECT 3.750 347.840 846.000 349.840 ;
        RECT 4.400 346.440 845.600 347.840 ;
        RECT 3.750 344.440 846.000 346.440 ;
        RECT 4.400 343.040 845.600 344.440 ;
        RECT 3.750 341.040 846.000 343.040 ;
        RECT 4.400 339.640 845.600 341.040 ;
        RECT 3.750 337.640 846.000 339.640 ;
        RECT 4.400 336.240 845.600 337.640 ;
        RECT 3.750 334.240 846.000 336.240 ;
        RECT 4.400 332.840 845.600 334.240 ;
        RECT 3.750 330.840 846.000 332.840 ;
        RECT 4.400 329.440 845.600 330.840 ;
        RECT 3.750 327.440 846.000 329.440 ;
        RECT 4.400 326.040 845.600 327.440 ;
        RECT 3.750 324.040 846.000 326.040 ;
        RECT 4.400 322.640 845.600 324.040 ;
        RECT 3.750 320.640 846.000 322.640 ;
        RECT 4.400 319.240 845.600 320.640 ;
        RECT 3.750 317.240 846.000 319.240 ;
        RECT 4.400 315.840 845.600 317.240 ;
        RECT 3.750 313.840 846.000 315.840 ;
        RECT 4.400 312.440 845.600 313.840 ;
        RECT 3.750 310.440 846.000 312.440 ;
        RECT 4.400 309.040 845.600 310.440 ;
        RECT 3.750 307.040 846.000 309.040 ;
        RECT 4.400 305.640 845.600 307.040 ;
        RECT 3.750 303.640 846.000 305.640 ;
        RECT 4.400 302.240 845.600 303.640 ;
        RECT 3.750 300.240 846.000 302.240 ;
        RECT 4.400 298.840 845.600 300.240 ;
        RECT 3.750 296.840 846.000 298.840 ;
        RECT 4.400 295.440 845.600 296.840 ;
        RECT 3.750 293.440 846.000 295.440 ;
        RECT 3.750 292.040 845.600 293.440 ;
        RECT 3.750 290.040 846.000 292.040 ;
        RECT 3.750 288.640 845.600 290.040 ;
        RECT 3.750 286.640 846.000 288.640 ;
        RECT 3.750 285.240 845.600 286.640 ;
        RECT 3.750 283.240 846.000 285.240 ;
        RECT 3.750 281.840 845.600 283.240 ;
        RECT 3.750 279.840 846.000 281.840 ;
        RECT 3.750 278.440 845.600 279.840 ;
        RECT 3.750 276.440 846.000 278.440 ;
        RECT 3.750 275.040 845.600 276.440 ;
        RECT 3.750 273.040 846.000 275.040 ;
        RECT 3.750 271.640 845.600 273.040 ;
        RECT 3.750 269.640 846.000 271.640 ;
        RECT 3.750 268.240 845.600 269.640 ;
        RECT 3.750 266.240 846.000 268.240 ;
        RECT 3.750 264.840 845.600 266.240 ;
        RECT 3.750 262.840 846.000 264.840 ;
        RECT 3.750 261.440 845.600 262.840 ;
        RECT 3.750 259.440 846.000 261.440 ;
        RECT 3.750 258.040 845.600 259.440 ;
        RECT 3.750 256.040 846.000 258.040 ;
        RECT 3.750 254.640 845.600 256.040 ;
        RECT 3.750 252.640 846.000 254.640 ;
        RECT 3.750 251.240 845.600 252.640 ;
        RECT 3.750 249.240 846.000 251.240 ;
        RECT 3.750 247.840 845.600 249.240 ;
        RECT 3.750 245.840 846.000 247.840 ;
        RECT 3.750 244.440 845.600 245.840 ;
        RECT 3.750 242.440 846.000 244.440 ;
        RECT 3.750 241.040 845.600 242.440 ;
        RECT 3.750 239.040 846.000 241.040 ;
        RECT 3.750 237.640 845.600 239.040 ;
        RECT 3.750 235.640 846.000 237.640 ;
        RECT 3.750 234.240 845.600 235.640 ;
        RECT 3.750 232.240 846.000 234.240 ;
        RECT 3.750 230.840 845.600 232.240 ;
        RECT 3.750 228.840 846.000 230.840 ;
        RECT 3.750 227.440 845.600 228.840 ;
        RECT 3.750 225.440 846.000 227.440 ;
        RECT 3.750 224.040 845.600 225.440 ;
        RECT 3.750 222.040 846.000 224.040 ;
        RECT 4.400 220.640 845.600 222.040 ;
        RECT 3.750 218.640 846.000 220.640 ;
        RECT 4.400 217.240 845.600 218.640 ;
        RECT 3.750 215.240 846.000 217.240 ;
        RECT 3.750 213.840 845.600 215.240 ;
        RECT 3.750 211.840 846.000 213.840 ;
        RECT 3.750 210.440 845.600 211.840 ;
        RECT 3.750 208.440 846.000 210.440 ;
        RECT 3.750 207.040 845.600 208.440 ;
        RECT 3.750 205.040 846.000 207.040 ;
        RECT 4.400 203.640 845.600 205.040 ;
        RECT 3.750 201.640 846.000 203.640 ;
        RECT 3.750 200.240 845.600 201.640 ;
        RECT 3.750 198.240 846.000 200.240 ;
        RECT 3.750 196.840 845.600 198.240 ;
        RECT 3.750 194.840 846.000 196.840 ;
        RECT 3.750 193.440 845.600 194.840 ;
        RECT 3.750 191.440 846.000 193.440 ;
        RECT 3.750 190.040 845.600 191.440 ;
        RECT 3.750 188.040 846.000 190.040 ;
        RECT 3.750 186.640 845.600 188.040 ;
        RECT 3.750 184.640 846.000 186.640 ;
        RECT 4.400 183.240 845.600 184.640 ;
        RECT 3.750 181.240 846.000 183.240 ;
        RECT 4.400 179.840 845.600 181.240 ;
        RECT 3.750 177.840 846.000 179.840 ;
        RECT 4.400 176.440 845.600 177.840 ;
        RECT 3.750 174.440 846.000 176.440 ;
        RECT 4.400 173.040 845.600 174.440 ;
        RECT 3.750 171.040 846.000 173.040 ;
        RECT 4.400 169.640 845.600 171.040 ;
        RECT 3.750 167.640 846.000 169.640 ;
        RECT 4.400 166.240 845.600 167.640 ;
        RECT 3.750 164.240 846.000 166.240 ;
        RECT 4.400 162.840 845.600 164.240 ;
        RECT 3.750 160.840 846.000 162.840 ;
        RECT 4.400 159.440 845.600 160.840 ;
        RECT 3.750 157.440 846.000 159.440 ;
        RECT 4.400 156.040 845.600 157.440 ;
        RECT 3.750 154.040 846.000 156.040 ;
        RECT 4.400 152.640 845.600 154.040 ;
        RECT 3.750 150.640 846.000 152.640 ;
        RECT 4.400 149.240 845.600 150.640 ;
        RECT 3.750 147.240 846.000 149.240 ;
        RECT 4.400 145.840 845.600 147.240 ;
        RECT 3.750 143.840 846.000 145.840 ;
        RECT 4.400 142.440 845.600 143.840 ;
        RECT 3.750 140.440 846.000 142.440 ;
        RECT 4.400 139.040 845.600 140.440 ;
        RECT 3.750 137.040 846.000 139.040 ;
        RECT 4.400 135.640 845.600 137.040 ;
        RECT 3.750 133.640 846.000 135.640 ;
        RECT 4.400 132.240 845.600 133.640 ;
        RECT 3.750 130.240 846.000 132.240 ;
        RECT 4.400 128.840 845.600 130.240 ;
        RECT 3.750 126.840 846.000 128.840 ;
        RECT 4.400 125.440 845.600 126.840 ;
        RECT 3.750 123.440 846.000 125.440 ;
        RECT 4.400 122.040 845.600 123.440 ;
        RECT 3.750 120.040 846.000 122.040 ;
        RECT 4.400 118.640 845.600 120.040 ;
        RECT 3.750 116.640 846.000 118.640 ;
        RECT 4.400 115.240 845.600 116.640 ;
        RECT 3.750 113.240 846.000 115.240 ;
        RECT 4.400 111.840 845.600 113.240 ;
        RECT 3.750 109.840 846.000 111.840 ;
        RECT 4.400 108.440 845.600 109.840 ;
        RECT 3.750 106.440 846.000 108.440 ;
        RECT 4.400 105.040 845.600 106.440 ;
        RECT 3.750 103.040 846.000 105.040 ;
        RECT 4.400 101.640 845.600 103.040 ;
        RECT 3.750 99.640 846.000 101.640 ;
        RECT 4.400 98.240 845.600 99.640 ;
        RECT 3.750 96.240 846.000 98.240 ;
        RECT 4.400 94.840 845.600 96.240 ;
        RECT 3.750 92.840 846.000 94.840 ;
        RECT 4.400 91.440 845.600 92.840 ;
        RECT 3.750 89.440 846.000 91.440 ;
        RECT 4.400 88.040 845.600 89.440 ;
        RECT 3.750 86.040 846.000 88.040 ;
        RECT 4.400 84.640 845.600 86.040 ;
        RECT 3.750 82.640 846.000 84.640 ;
        RECT 4.400 81.240 845.600 82.640 ;
        RECT 3.750 79.240 846.000 81.240 ;
        RECT 4.400 77.840 845.600 79.240 ;
        RECT 3.750 75.840 846.000 77.840 ;
        RECT 4.400 74.440 845.600 75.840 ;
        RECT 3.750 72.440 846.000 74.440 ;
        RECT 4.400 71.040 845.600 72.440 ;
        RECT 3.750 69.040 846.000 71.040 ;
        RECT 4.400 67.640 845.600 69.040 ;
        RECT 3.750 65.640 846.000 67.640 ;
        RECT 4.400 64.240 845.600 65.640 ;
        RECT 3.750 62.240 846.000 64.240 ;
        RECT 4.400 60.840 845.600 62.240 ;
        RECT 3.750 58.840 846.000 60.840 ;
        RECT 4.400 57.440 845.600 58.840 ;
        RECT 3.750 55.440 846.000 57.440 ;
        RECT 4.400 54.040 845.600 55.440 ;
        RECT 3.750 52.040 846.000 54.040 ;
        RECT 4.400 50.640 845.600 52.040 ;
        RECT 3.750 48.640 846.000 50.640 ;
        RECT 4.400 47.240 845.600 48.640 ;
        RECT 3.750 45.240 846.000 47.240 ;
        RECT 4.400 43.840 845.600 45.240 ;
        RECT 3.750 41.840 846.000 43.840 ;
        RECT 4.400 40.440 845.600 41.840 ;
        RECT 3.750 38.440 846.000 40.440 ;
        RECT 4.400 37.040 845.600 38.440 ;
        RECT 3.750 35.040 846.000 37.040 ;
        RECT 4.400 33.640 845.600 35.040 ;
        RECT 3.750 31.640 846.000 33.640 ;
        RECT 4.400 30.240 845.600 31.640 ;
        RECT 3.750 28.240 846.000 30.240 ;
        RECT 4.400 26.840 845.600 28.240 ;
        RECT 3.750 24.840 846.000 26.840 ;
        RECT 4.400 23.440 845.600 24.840 ;
        RECT 3.750 21.440 846.000 23.440 ;
        RECT 4.400 20.040 845.600 21.440 ;
        RECT 3.750 18.040 846.000 20.040 ;
        RECT 4.400 16.640 845.600 18.040 ;
        RECT 3.750 14.640 846.000 16.640 ;
        RECT 4.400 13.240 845.600 14.640 ;
        RECT 3.750 11.240 846.000 13.240 ;
        RECT 4.400 9.840 845.600 11.240 ;
        RECT 3.750 7.840 846.000 9.840 ;
        RECT 4.400 6.440 845.600 7.840 ;
        RECT 3.750 4.440 846.000 6.440 ;
        RECT 4.400 3.040 845.600 4.440 ;
        RECT 3.750 1.040 846.000 3.040 ;
        RECT 4.400 0.175 845.600 1.040 ;
      LAYER met4 ;
        RECT 3.975 19.895 20.640 836.225 ;
        RECT 23.040 19.895 23.940 836.225 ;
        RECT 26.340 19.895 174.240 836.225 ;
        RECT 176.640 19.895 177.540 836.225 ;
        RECT 179.940 19.895 327.840 836.225 ;
        RECT 330.240 19.895 331.140 836.225 ;
        RECT 333.540 19.895 481.440 836.225 ;
        RECT 483.840 19.895 484.740 836.225 ;
        RECT 487.140 19.895 635.040 836.225 ;
        RECT 637.440 19.895 638.340 836.225 ;
        RECT 640.740 19.895 788.640 836.225 ;
        RECT 791.040 19.895 791.940 836.225 ;
        RECT 794.340 19.895 841.505 836.225 ;
  END
END xoodyakcore
END LIBRARY

